VERSION 5.8 ;
BUSBITCHARS "[]" ;
DIVIDERCHAR "/" ;
UNITS
    DATABASE MICRONS 1000 ;
END UNITS

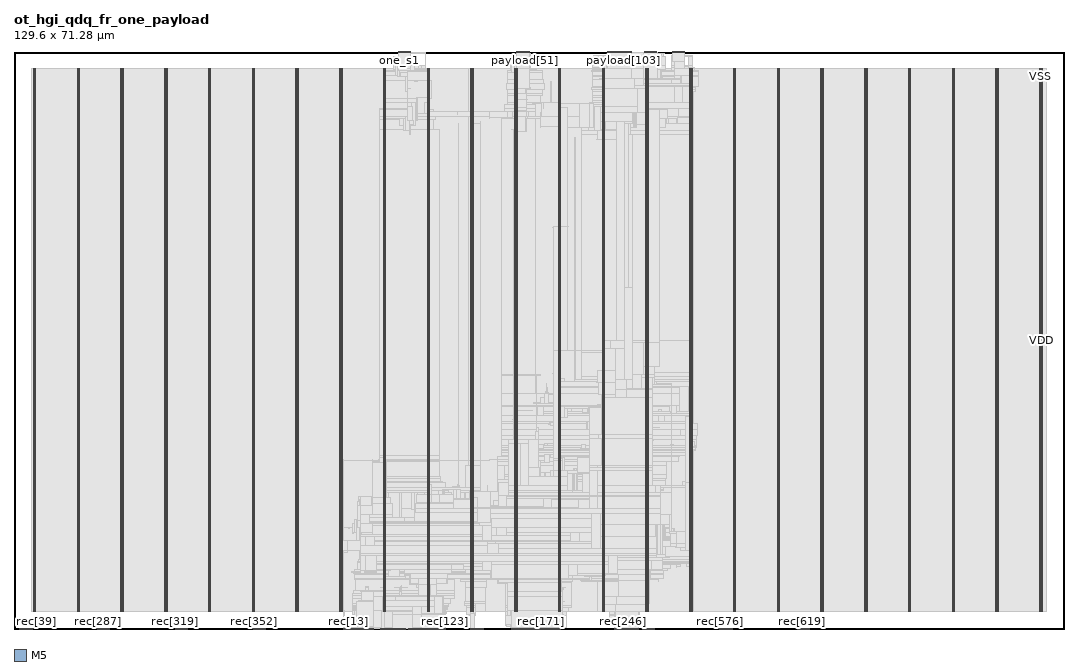
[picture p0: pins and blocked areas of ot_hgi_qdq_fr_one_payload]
MACRO ot_hgi_qdq_fr_one_payload
  FOREIGN ot_hgi_qdq_fr_one_payload 0 0 ;
  CLASS BLOCK ;
  SIZE 129.6 BY 71.28 ;
  PIN clk
    DIRECTION INPUT ;
    USE SIGNAL ;
    PORT
      LAYER M5 ;
        RECT  40.656 0 40.68 0.084 ;
    END
  END clk
  PIN nfault
    DIRECTION OUTPUT ;
    USE SIGNAL ;
    PORT
      LAYER M5 ;
        RECT  47.472 71.196 47.496 71.28 ;
    END
  END nfault
  PIN one_s1
    DIRECTION OUTPUT ;
    USE SIGNAL ;
    PORT
      LAYER M5 ;
        RECT  47.52 71.196 47.544 71.28 ;
    END
  END one_s1
  PIN payload[0]
    DIRECTION OUTPUT ;
    USE SIGNAL ;
    PORT
      LAYER M5 ;
        RECT  47.568 71.196 47.592 71.28 ;
    END
  END payload[0]
  PIN payload[100]
    DIRECTION OUTPUT ;
    USE SIGNAL ;
    PORT
      LAYER M5 ;
        RECT  75.024 71.196 75.048 71.28 ;
    END
  END payload[100]
  PIN payload[101]
    DIRECTION OUTPUT ;
    USE SIGNAL ;
    PORT
      LAYER M5 ;
        RECT  75.072 71.196 75.096 71.28 ;
    END
  END payload[101]
  PIN payload[102]
    DIRECTION OUTPUT ;
    USE SIGNAL ;
    PORT
      LAYER M5 ;
        RECT  75.12 71.196 75.144 71.28 ;
    END
  END payload[102]
  PIN payload[103]
    DIRECTION OUTPUT ;
    USE SIGNAL ;
    PORT
      LAYER M5 ;
        RECT  75.168 71.196 75.192 71.28 ;
    END
  END payload[103]
  PIN payload[104]
    DIRECTION OUTPUT ;
    USE SIGNAL ;
    PORT
      LAYER M5 ;
        RECT  75.216 71.196 75.24 71.28 ;
    END
  END payload[104]
  PIN payload[105]
    DIRECTION OUTPUT ;
    USE SIGNAL ;
    PORT
      LAYER M5 ;
        RECT  75.264 71.196 75.288 71.28 ;
    END
  END payload[105]
  PIN payload[106]
    DIRECTION OUTPUT ;
    USE SIGNAL ;
    PORT
      LAYER M5 ;
        RECT  75.312 71.196 75.336 71.28 ;
    END
  END payload[106]
  PIN payload[107]
    DIRECTION OUTPUT ;
    USE SIGNAL ;
    PORT
      LAYER M5 ;
        RECT  75.36 71.196 75.384 71.28 ;
    END
  END payload[107]
  PIN payload[108]
    DIRECTION OUTPUT ;
    USE SIGNAL ;
    PORT
      LAYER M5 ;
        RECT  75.408 71.196 75.432 71.28 ;
    END
  END payload[108]
  PIN payload[109]
    DIRECTION OUTPUT ;
    USE SIGNAL ;
    PORT
      LAYER M5 ;
        RECT  75.456 71.196 75.48 71.28 ;
    END
  END payload[109]
  PIN payload[10]
    DIRECTION OUTPUT ;
    USE SIGNAL ;
    PORT
      LAYER M5 ;
        RECT  48.048 71.196 48.072 71.28 ;
    END
  END payload[10]
  PIN payload[110]
    DIRECTION OUTPUT ;
    USE SIGNAL ;
    PORT
      LAYER M5 ;
        RECT  75.504 71.196 75.528 71.28 ;
    END
  END payload[110]
  PIN payload[111]
    DIRECTION OUTPUT ;
    USE SIGNAL ;
    PORT
      LAYER M5 ;
        RECT  75.552 71.196 75.576 71.28 ;
    END
  END payload[111]
  PIN payload[112]
    DIRECTION OUTPUT ;
    USE SIGNAL ;
    PORT
      LAYER M5 ;
        RECT  75.6 71.196 75.624 71.28 ;
    END
  END payload[112]
  PIN payload[113]
    DIRECTION OUTPUT ;
    USE SIGNAL ;
    PORT
      LAYER M5 ;
        RECT  75.648 71.196 75.672 71.28 ;
    END
  END payload[113]
  PIN payload[114]
    DIRECTION OUTPUT ;
    USE SIGNAL ;
    PORT
      LAYER M5 ;
        RECT  75.696 71.196 75.72 71.28 ;
    END
  END payload[114]
  PIN payload[115]
    DIRECTION OUTPUT ;
    USE SIGNAL ;
    PORT
      LAYER M5 ;
        RECT  75.744 71.196 75.768 71.28 ;
    END
  END payload[115]
  PIN payload[116]
    DIRECTION OUTPUT ;
    USE SIGNAL ;
    PORT
      LAYER M5 ;
        RECT  75.792 71.196 75.816 71.28 ;
    END
  END payload[116]
  PIN payload[117]
    DIRECTION OUTPUT ;
    USE SIGNAL ;
    PORT
      LAYER M5 ;
        RECT  75.84 71.196 75.864 71.28 ;
    END
  END payload[117]
  PIN payload[118]
    DIRECTION OUTPUT ;
    USE SIGNAL ;
    PORT
      LAYER M5 ;
        RECT  75.888 71.196 75.912 71.28 ;
    END
  END payload[118]
  PIN payload[119]
    DIRECTION OUTPUT ;
    USE SIGNAL ;
    PORT
      LAYER M5 ;
        RECT  75.936 71.196 75.96 71.28 ;
    END
  END payload[119]
  PIN payload[11]
    DIRECTION OUTPUT ;
    USE SIGNAL ;
    PORT
      LAYER M5 ;
        RECT  48.096 71.196 48.12 71.28 ;
    END
  END payload[11]
  PIN payload[120]
    DIRECTION OUTPUT ;
    USE SIGNAL ;
    PORT
      LAYER M5 ;
        RECT  75.984 71.196 76.008 71.28 ;
    END
  END payload[120]
  PIN payload[121]
    DIRECTION OUTPUT ;
    USE SIGNAL ;
    PORT
      LAYER M5 ;
        RECT  76.032 71.196 76.056 71.28 ;
    END
  END payload[121]
  PIN payload[122]
    DIRECTION OUTPUT ;
    USE SIGNAL ;
    PORT
      LAYER M5 ;
        RECT  76.08 71.196 76.104 71.28 ;
    END
  END payload[122]
  PIN payload[123]
    DIRECTION OUTPUT ;
    USE SIGNAL ;
    PORT
      LAYER M5 ;
        RECT  76.128 71.196 76.152 71.28 ;
    END
  END payload[123]
  PIN payload[124]
    DIRECTION OUTPUT ;
    USE SIGNAL ;
    PORT
      LAYER M5 ;
        RECT  76.176 71.196 76.2 71.28 ;
    END
  END payload[124]
  PIN payload[125]
    DIRECTION OUTPUT ;
    USE SIGNAL ;
    PORT
      LAYER M5 ;
        RECT  76.224 71.196 76.248 71.28 ;
    END
  END payload[125]
  PIN payload[126]
    DIRECTION OUTPUT ;
    USE SIGNAL ;
    PORT
      LAYER M5 ;
        RECT  77.808 71.196 77.832 71.28 ;
    END
  END payload[126]
  PIN payload[127]
    DIRECTION OUTPUT ;
    USE SIGNAL ;
    PORT
      LAYER M5 ;
        RECT  77.856 71.196 77.88 71.28 ;
    END
  END payload[127]
  PIN payload[128]
    DIRECTION OUTPUT ;
    USE SIGNAL ;
    PORT
      LAYER M5 ;
        RECT  77.904 71.196 77.928 71.28 ;
    END
  END payload[128]
  PIN payload[129]
    DIRECTION OUTPUT ;
    USE SIGNAL ;
    PORT
      LAYER M5 ;
        RECT  77.952 71.196 77.976 71.28 ;
    END
  END payload[129]
  PIN payload[12]
    DIRECTION OUTPUT ;
    USE SIGNAL ;
    PORT
      LAYER M5 ;
        RECT  48.144 71.196 48.168 71.28 ;
    END
  END payload[12]
  PIN payload[130]
    DIRECTION OUTPUT ;
    USE SIGNAL ;
    PORT
      LAYER M5 ;
        RECT  78 71.196 78.024 71.28 ;
    END
  END payload[130]
  PIN payload[131]
    DIRECTION OUTPUT ;
    USE SIGNAL ;
    PORT
      LAYER M5 ;
        RECT  78.048 71.196 78.072 71.28 ;
    END
  END payload[131]
  PIN payload[132]
    DIRECTION OUTPUT ;
    USE SIGNAL ;
    PORT
      LAYER M5 ;
        RECT  78.096 71.196 78.12 71.28 ;
    END
  END payload[132]
  PIN payload[133]
    DIRECTION OUTPUT ;
    USE SIGNAL ;
    PORT
      LAYER M5 ;
        RECT  78.144 71.196 78.168 71.28 ;
    END
  END payload[133]
  PIN payload[134]
    DIRECTION OUTPUT ;
    USE SIGNAL ;
    PORT
      LAYER M5 ;
        RECT  78.192 71.196 78.216 71.28 ;
    END
  END payload[134]
  PIN payload[135]
    DIRECTION OUTPUT ;
    USE SIGNAL ;
    PORT
      LAYER M5 ;
        RECT  78.24 71.196 78.264 71.28 ;
    END
  END payload[135]
  PIN payload[136]
    DIRECTION OUTPUT ;
    USE SIGNAL ;
    PORT
      LAYER M5 ;
        RECT  78.288 71.196 78.312 71.28 ;
    END
  END payload[136]
  PIN payload[137]
    DIRECTION OUTPUT ;
    USE SIGNAL ;
    PORT
      LAYER M5 ;
        RECT  78.336 71.196 78.36 71.28 ;
    END
  END payload[137]
  PIN payload[138]
    DIRECTION OUTPUT ;
    USE SIGNAL ;
    PORT
      LAYER M5 ;
        RECT  78.384 71.196 78.408 71.28 ;
    END
  END payload[138]
  PIN payload[139]
    DIRECTION OUTPUT ;
    USE SIGNAL ;
    PORT
      LAYER M5 ;
        RECT  78.432 71.196 78.456 71.28 ;
    END
  END payload[139]
  PIN payload[13]
    DIRECTION OUTPUT ;
    USE SIGNAL ;
    PORT
      LAYER M5 ;
        RECT  48.192 71.196 48.216 71.28 ;
    END
  END payload[13]
  PIN payload[140]
    DIRECTION OUTPUT ;
    USE SIGNAL ;
    PORT
      LAYER M5 ;
        RECT  78.48 71.196 78.504 71.28 ;
    END
  END payload[140]
  PIN payload[141]
    DIRECTION OUTPUT ;
    USE SIGNAL ;
    PORT
      LAYER M5 ;
        RECT  78.528 71.196 78.552 71.28 ;
    END
  END payload[141]
  PIN payload[142]
    DIRECTION OUTPUT ;
    USE SIGNAL ;
    PORT
      LAYER M5 ;
        RECT  78.576 71.196 78.6 71.28 ;
    END
  END payload[142]
  PIN payload[143]
    DIRECTION OUTPUT ;
    USE SIGNAL ;
    PORT
      LAYER M5 ;
        RECT  78.624 71.196 78.648 71.28 ;
    END
  END payload[143]
  PIN payload[144]
    DIRECTION OUTPUT ;
    USE SIGNAL ;
    PORT
      LAYER M5 ;
        RECT  78.672 71.196 78.696 71.28 ;
    END
  END payload[144]
  PIN payload[145]
    DIRECTION OUTPUT ;
    USE SIGNAL ;
    PORT
      LAYER M5 ;
        RECT  78.72 71.196 78.744 71.28 ;
    END
  END payload[145]
  PIN payload[146]
    DIRECTION OUTPUT ;
    USE SIGNAL ;
    PORT
      LAYER M5 ;
        RECT  78.768 71.196 78.792 71.28 ;
    END
  END payload[146]
  PIN payload[147]
    DIRECTION OUTPUT ;
    USE SIGNAL ;
    PORT
      LAYER M5 ;
        RECT  78.816 71.196 78.84 71.28 ;
    END
  END payload[147]
  PIN payload[148]
    DIRECTION OUTPUT ;
    USE SIGNAL ;
    PORT
      LAYER M5 ;
        RECT  78.864 71.196 78.888 71.28 ;
    END
  END payload[148]
  PIN payload[149]
    DIRECTION OUTPUT ;
    USE SIGNAL ;
    PORT
      LAYER M5 ;
        RECT  78.912 71.196 78.936 71.28 ;
    END
  END payload[149]
  PIN payload[14]
    DIRECTION OUTPUT ;
    USE SIGNAL ;
    PORT
      LAYER M5 ;
        RECT  48.24 71.196 48.264 71.28 ;
    END
  END payload[14]
  PIN payload[150]
    DIRECTION OUTPUT ;
    USE SIGNAL ;
    PORT
      LAYER M5 ;
        RECT  78.96 71.196 78.984 71.28 ;
    END
  END payload[150]
  PIN payload[151]
    DIRECTION OUTPUT ;
    USE SIGNAL ;
    PORT
      LAYER M5 ;
        RECT  79.008 71.196 79.032 71.28 ;
    END
  END payload[151]
  PIN payload[152]
    DIRECTION OUTPUT ;
    USE SIGNAL ;
    PORT
      LAYER M5 ;
        RECT  79.056 71.196 79.08 71.28 ;
    END
  END payload[152]
  PIN payload[153]
    DIRECTION OUTPUT ;
    USE SIGNAL ;
    PORT
      LAYER M5 ;
        RECT  79.104 71.196 79.128 71.28 ;
    END
  END payload[153]
  PIN payload[154]
    DIRECTION OUTPUT ;
    USE SIGNAL ;
    PORT
      LAYER M5 ;
        RECT  79.152 71.196 79.176 71.28 ;
    END
  END payload[154]
  PIN payload[155]
    DIRECTION OUTPUT ;
    USE SIGNAL ;
    PORT
      LAYER M5 ;
        RECT  79.2 71.196 79.224 71.28 ;
    END
  END payload[155]
  PIN payload[156]
    DIRECTION OUTPUT ;
    USE SIGNAL ;
    PORT
      LAYER M5 ;
        RECT  79.248 71.196 79.272 71.28 ;
    END
  END payload[156]
  PIN payload[157]
    DIRECTION OUTPUT ;
    USE SIGNAL ;
    PORT
      LAYER M5 ;
        RECT  79.296 71.196 79.32 71.28 ;
    END
  END payload[157]
  PIN payload[158]
    DIRECTION OUTPUT ;
    USE SIGNAL ;
    PORT
      LAYER M5 ;
        RECT  81.264 71.196 81.288 71.28 ;
    END
  END payload[158]
  PIN payload[159]
    DIRECTION OUTPUT ;
    USE SIGNAL ;
    PORT
      LAYER M5 ;
        RECT  81.312 71.196 81.336 71.28 ;
    END
  END payload[159]
  PIN payload[15]
    DIRECTION OUTPUT ;
    USE SIGNAL ;
    PORT
      LAYER M5 ;
        RECT  48.288 71.196 48.312 71.28 ;
    END
  END payload[15]
  PIN payload[160]
    DIRECTION OUTPUT ;
    USE SIGNAL ;
    PORT
      LAYER M5 ;
        RECT  81.36 71.196 81.384 71.28 ;
    END
  END payload[160]
  PIN payload[161]
    DIRECTION OUTPUT ;
    USE SIGNAL ;
    PORT
      LAYER M5 ;
        RECT  81.408 71.196 81.432 71.28 ;
    END
  END payload[161]
  PIN payload[162]
    DIRECTION OUTPUT ;
    USE SIGNAL ;
    PORT
      LAYER M5 ;
        RECT  81.456 71.196 81.48 71.28 ;
    END
  END payload[162]
  PIN payload[163]
    DIRECTION OUTPUT ;
    USE SIGNAL ;
    PORT
      LAYER M5 ;
        RECT  81.504 71.196 81.528 71.28 ;
    END
  END payload[163]
  PIN payload[164]
    DIRECTION OUTPUT ;
    USE SIGNAL ;
    PORT
      LAYER M5 ;
        RECT  81.552 71.196 81.576 71.28 ;
    END
  END payload[164]
  PIN payload[165]
    DIRECTION OUTPUT ;
    USE SIGNAL ;
    PORT
      LAYER M5 ;
        RECT  81.6 71.196 81.624 71.28 ;
    END
  END payload[165]
  PIN payload[166]
    DIRECTION OUTPUT ;
    USE SIGNAL ;
    PORT
      LAYER M5 ;
        RECT  81.648 71.196 81.672 71.28 ;
    END
  END payload[166]
  PIN payload[167]
    DIRECTION OUTPUT ;
    USE SIGNAL ;
    PORT
      LAYER M5 ;
        RECT  81.696 71.196 81.72 71.28 ;
    END
  END payload[167]
  PIN payload[168]
    DIRECTION OUTPUT ;
    USE SIGNAL ;
    PORT
      LAYER M5 ;
        RECT  81.744 71.196 81.768 71.28 ;
    END
  END payload[168]
  PIN payload[169]
    DIRECTION OUTPUT ;
    USE SIGNAL ;
    PORT
      LAYER M5 ;
        RECT  81.792 71.196 81.816 71.28 ;
    END
  END payload[169]
  PIN payload[16]
    DIRECTION OUTPUT ;
    USE SIGNAL ;
    PORT
      LAYER M5 ;
        RECT  48.336 71.196 48.36 71.28 ;
    END
  END payload[16]
  PIN payload[170]
    DIRECTION OUTPUT ;
    USE SIGNAL ;
    PORT
      LAYER M5 ;
        RECT  81.84 71.196 81.864 71.28 ;
    END
  END payload[170]
  PIN payload[171]
    DIRECTION OUTPUT ;
    USE SIGNAL ;
    PORT
      LAYER M5 ;
        RECT  81.888 71.196 81.912 71.28 ;
    END
  END payload[171]
  PIN payload[172]
    DIRECTION OUTPUT ;
    USE SIGNAL ;
    PORT
      LAYER M5 ;
        RECT  81.936 71.196 81.96 71.28 ;
    END
  END payload[172]
  PIN payload[173]
    DIRECTION OUTPUT ;
    USE SIGNAL ;
    PORT
      LAYER M5 ;
        RECT  81.984 71.196 82.008 71.28 ;
    END
  END payload[173]
  PIN payload[174]
    DIRECTION OUTPUT ;
    USE SIGNAL ;
    PORT
      LAYER M5 ;
        RECT  82.032 71.196 82.056 71.28 ;
    END
  END payload[174]
  PIN payload[175]
    DIRECTION OUTPUT ;
    USE SIGNAL ;
    PORT
      LAYER M5 ;
        RECT  82.08 71.196 82.104 71.28 ;
    END
  END payload[175]
  PIN payload[176]
    DIRECTION OUTPUT ;
    USE SIGNAL ;
    PORT
      LAYER M5 ;
        RECT  82.128 71.196 82.152 71.28 ;
    END
  END payload[176]
  PIN payload[177]
    DIRECTION OUTPUT ;
    USE SIGNAL ;
    PORT
      LAYER M5 ;
        RECT  82.176 71.196 82.2 71.28 ;
    END
  END payload[177]
  PIN payload[178]
    DIRECTION OUTPUT ;
    USE SIGNAL ;
    PORT
      LAYER M5 ;
        RECT  82.224 71.196 82.248 71.28 ;
    END
  END payload[178]
  PIN payload[179]
    DIRECTION OUTPUT ;
    USE SIGNAL ;
    PORT
      LAYER M5 ;
        RECT  82.272 71.196 82.296 71.28 ;
    END
  END payload[179]
  PIN payload[17]
    DIRECTION OUTPUT ;
    USE SIGNAL ;
    PORT
      LAYER M5 ;
        RECT  48.384 71.196 48.408 71.28 ;
    END
  END payload[17]
  PIN payload[180]
    DIRECTION OUTPUT ;
    USE SIGNAL ;
    PORT
      LAYER M5 ;
        RECT  82.32 71.196 82.344 71.28 ;
    END
  END payload[180]
  PIN payload[181]
    DIRECTION OUTPUT ;
    USE SIGNAL ;
    PORT
      LAYER M5 ;
        RECT  82.368 71.196 82.392 71.28 ;
    END
  END payload[181]
  PIN payload[182]
    DIRECTION OUTPUT ;
    USE SIGNAL ;
    PORT
      LAYER M5 ;
        RECT  82.416 71.196 82.44 71.28 ;
    END
  END payload[182]
  PIN payload[183]
    DIRECTION OUTPUT ;
    USE SIGNAL ;
    PORT
      LAYER M5 ;
        RECT  82.464 71.196 82.488 71.28 ;
    END
  END payload[183]
  PIN payload[184]
    DIRECTION OUTPUT ;
    USE SIGNAL ;
    PORT
      LAYER M5 ;
        RECT  82.512 71.196 82.536 71.28 ;
    END
  END payload[184]
  PIN payload[185]
    DIRECTION OUTPUT ;
    USE SIGNAL ;
    PORT
      LAYER M5 ;
        RECT  82.56 71.196 82.584 71.28 ;
    END
  END payload[185]
  PIN payload[186]
    DIRECTION OUTPUT ;
    USE SIGNAL ;
    PORT
      LAYER M5 ;
        RECT  82.608 71.196 82.632 71.28 ;
    END
  END payload[186]
  PIN payload[187]
    DIRECTION OUTPUT ;
    USE SIGNAL ;
    PORT
      LAYER M5 ;
        RECT  82.656 71.196 82.68 71.28 ;
    END
  END payload[187]
  PIN payload[188]
    DIRECTION OUTPUT ;
    USE SIGNAL ;
    PORT
      LAYER M5 ;
        RECT  82.704 71.196 82.728 71.28 ;
    END
  END payload[188]
  PIN payload[189]
    DIRECTION OUTPUT ;
    USE SIGNAL ;
    PORT
      LAYER M5 ;
        RECT  82.752 71.196 82.776 71.28 ;
    END
  END payload[189]
  PIN payload[18]
    DIRECTION OUTPUT ;
    USE SIGNAL ;
    PORT
      LAYER M5 ;
        RECT  48.432 71.196 48.456 71.28 ;
    END
  END payload[18]
  PIN payload[19]
    DIRECTION OUTPUT ;
    USE SIGNAL ;
    PORT
      LAYER M5 ;
        RECT  48.48 71.196 48.504 71.28 ;
    END
  END payload[19]
  PIN payload[1]
    DIRECTION OUTPUT ;
    USE SIGNAL ;
    PORT
      LAYER M5 ;
        RECT  47.616 71.196 47.64 71.28 ;
    END
  END payload[1]
  PIN payload[20]
    DIRECTION OUTPUT ;
    USE SIGNAL ;
    PORT
      LAYER M5 ;
        RECT  48.528 71.196 48.552 71.28 ;
    END
  END payload[20]
  PIN payload[21]
    DIRECTION OUTPUT ;
    USE SIGNAL ;
    PORT
      LAYER M5 ;
        RECT  48.576 71.196 48.6 71.28 ;
    END
  END payload[21]
  PIN payload[22]
    DIRECTION OUTPUT ;
    USE SIGNAL ;
    PORT
      LAYER M5 ;
        RECT  48.624 71.196 48.648 71.28 ;
    END
  END payload[22]
  PIN payload[23]
    DIRECTION OUTPUT ;
    USE SIGNAL ;
    PORT
      LAYER M5 ;
        RECT  48.672 71.196 48.696 71.28 ;
    END
  END payload[23]
  PIN payload[24]
    DIRECTION OUTPUT ;
    USE SIGNAL ;
    PORT
      LAYER M5 ;
        RECT  48.72 71.196 48.744 71.28 ;
    END
  END payload[24]
  PIN payload[25]
    DIRECTION OUTPUT ;
    USE SIGNAL ;
    PORT
      LAYER M5 ;
        RECT  48.768 71.196 48.792 71.28 ;
    END
  END payload[25]
  PIN payload[26]
    DIRECTION OUTPUT ;
    USE SIGNAL ;
    PORT
      LAYER M5 ;
        RECT  48.816 71.196 48.84 71.28 ;
    END
  END payload[26]
  PIN payload[27]
    DIRECTION OUTPUT ;
    USE SIGNAL ;
    PORT
      LAYER M5 ;
        RECT  48.864 71.196 48.888 71.28 ;
    END
  END payload[27]
  PIN payload[28]
    DIRECTION OUTPUT ;
    USE SIGNAL ;
    PORT
      LAYER M5 ;
        RECT  48.912 71.196 48.936 71.28 ;
    END
  END payload[28]
  PIN payload[29]
    DIRECTION OUTPUT ;
    USE SIGNAL ;
    PORT
      LAYER M5 ;
        RECT  48.96 71.196 48.984 71.28 ;
    END
  END payload[29]
  PIN payload[2]
    DIRECTION OUTPUT ;
    USE SIGNAL ;
    PORT
      LAYER M5 ;
        RECT  47.664 71.196 47.688 71.28 ;
    END
  END payload[2]
  PIN payload[30]
    DIRECTION OUTPUT ;
    USE SIGNAL ;
    PORT
      LAYER M5 ;
        RECT  62.064 71.196 62.088 71.28 ;
    END
  END payload[30]
  PIN payload[31]
    DIRECTION OUTPUT ;
    USE SIGNAL ;
    PORT
      LAYER M5 ;
        RECT  62.112 71.196 62.136 71.28 ;
    END
  END payload[31]
  PIN payload[32]
    DIRECTION OUTPUT ;
    USE SIGNAL ;
    PORT
      LAYER M5 ;
        RECT  62.16 71.196 62.184 71.28 ;
    END
  END payload[32]
  PIN payload[33]
    DIRECTION OUTPUT ;
    USE SIGNAL ;
    PORT
      LAYER M5 ;
        RECT  62.208 71.196 62.232 71.28 ;
    END
  END payload[33]
  PIN payload[34]
    DIRECTION OUTPUT ;
    USE SIGNAL ;
    PORT
      LAYER M5 ;
        RECT  62.256 71.196 62.28 71.28 ;
    END
  END payload[34]
  PIN payload[35]
    DIRECTION OUTPUT ;
    USE SIGNAL ;
    PORT
      LAYER M5 ;
        RECT  62.304 71.196 62.328 71.28 ;
    END
  END payload[35]
  PIN payload[36]
    DIRECTION OUTPUT ;
    USE SIGNAL ;
    PORT
      LAYER M5 ;
        RECT  62.352 71.196 62.376 71.28 ;
    END
  END payload[36]
  PIN payload[37]
    DIRECTION OUTPUT ;
    USE SIGNAL ;
    PORT
      LAYER M5 ;
        RECT  62.4 71.196 62.424 71.28 ;
    END
  END payload[37]
  PIN payload[38]
    DIRECTION OUTPUT ;
    USE SIGNAL ;
    PORT
      LAYER M5 ;
        RECT  62.448 71.196 62.472 71.28 ;
    END
  END payload[38]
  PIN payload[39]
    DIRECTION OUTPUT ;
    USE SIGNAL ;
    PORT
      LAYER M5 ;
        RECT  62.496 71.196 62.52 71.28 ;
    END
  END payload[39]
  PIN payload[3]
    DIRECTION OUTPUT ;
    USE SIGNAL ;
    PORT
      LAYER M5 ;
        RECT  47.712 71.196 47.736 71.28 ;
    END
  END payload[3]
  PIN payload[40]
    DIRECTION OUTPUT ;
    USE SIGNAL ;
    PORT
      LAYER M5 ;
        RECT  62.544 71.196 62.568 71.28 ;
    END
  END payload[40]
  PIN payload[41]
    DIRECTION OUTPUT ;
    USE SIGNAL ;
    PORT
      LAYER M5 ;
        RECT  62.592 71.196 62.616 71.28 ;
    END
  END payload[41]
  PIN payload[42]
    DIRECTION OUTPUT ;
    USE SIGNAL ;
    PORT
      LAYER M5 ;
        RECT  62.64 71.196 62.664 71.28 ;
    END
  END payload[42]
  PIN payload[43]
    DIRECTION OUTPUT ;
    USE SIGNAL ;
    PORT
      LAYER M5 ;
        RECT  62.688 71.196 62.712 71.28 ;
    END
  END payload[43]
  PIN payload[44]
    DIRECTION OUTPUT ;
    USE SIGNAL ;
    PORT
      LAYER M5 ;
        RECT  62.736 71.196 62.76 71.28 ;
    END
  END payload[44]
  PIN payload[45]
    DIRECTION OUTPUT ;
    USE SIGNAL ;
    PORT
      LAYER M5 ;
        RECT  62.784 71.196 62.808 71.28 ;
    END
  END payload[45]
  PIN payload[46]
    DIRECTION OUTPUT ;
    USE SIGNAL ;
    PORT
      LAYER M5 ;
        RECT  62.832 71.196 62.856 71.28 ;
    END
  END payload[46]
  PIN payload[47]
    DIRECTION OUTPUT ;
    USE SIGNAL ;
    PORT
      LAYER M5 ;
        RECT  62.88 71.196 62.904 71.28 ;
    END
  END payload[47]
  PIN payload[48]
    DIRECTION OUTPUT ;
    USE SIGNAL ;
    PORT
      LAYER M5 ;
        RECT  62.928 71.196 62.952 71.28 ;
    END
  END payload[48]
  PIN payload[49]
    DIRECTION OUTPUT ;
    USE SIGNAL ;
    PORT
      LAYER M5 ;
        RECT  62.976 71.196 63 71.28 ;
    END
  END payload[49]
  PIN payload[4]
    DIRECTION OUTPUT ;
    USE SIGNAL ;
    PORT
      LAYER M5 ;
        RECT  47.76 71.196 47.784 71.28 ;
    END
  END payload[4]
  PIN payload[50]
    DIRECTION OUTPUT ;
    USE SIGNAL ;
    PORT
      LAYER M5 ;
        RECT  63.024 71.196 63.048 71.28 ;
    END
  END payload[50]
  PIN payload[51]
    DIRECTION OUTPUT ;
    USE SIGNAL ;
    PORT
      LAYER M5 ;
        RECT  63.072 71.196 63.096 71.28 ;
    END
  END payload[51]
  PIN payload[52]
    DIRECTION OUTPUT ;
    USE SIGNAL ;
    PORT
      LAYER M5 ;
        RECT  63.12 71.196 63.144 71.28 ;
    END
  END payload[52]
  PIN payload[53]
    DIRECTION OUTPUT ;
    USE SIGNAL ;
    PORT
      LAYER M5 ;
        RECT  63.168 71.196 63.192 71.28 ;
    END
  END payload[53]
  PIN payload[54]
    DIRECTION OUTPUT ;
    USE SIGNAL ;
    PORT
      LAYER M5 ;
        RECT  63.216 71.196 63.24 71.28 ;
    END
  END payload[54]
  PIN payload[55]
    DIRECTION OUTPUT ;
    USE SIGNAL ;
    PORT
      LAYER M5 ;
        RECT  63.264 71.196 63.288 71.28 ;
    END
  END payload[55]
  PIN payload[56]
    DIRECTION OUTPUT ;
    USE SIGNAL ;
    PORT
      LAYER M5 ;
        RECT  63.312 71.196 63.336 71.28 ;
    END
  END payload[56]
  PIN payload[57]
    DIRECTION OUTPUT ;
    USE SIGNAL ;
    PORT
      LAYER M5 ;
        RECT  63.36 71.196 63.384 71.28 ;
    END
  END payload[57]
  PIN payload[58]
    DIRECTION OUTPUT ;
    USE SIGNAL ;
    PORT
      LAYER M5 ;
        RECT  63.408 71.196 63.432 71.28 ;
    END
  END payload[58]
  PIN payload[59]
    DIRECTION OUTPUT ;
    USE SIGNAL ;
    PORT
      LAYER M5 ;
        RECT  63.456 71.196 63.48 71.28 ;
    END
  END payload[59]
  PIN payload[5]
    DIRECTION OUTPUT ;
    USE SIGNAL ;
    PORT
      LAYER M5 ;
        RECT  47.808 71.196 47.832 71.28 ;
    END
  END payload[5]
  PIN payload[60]
    DIRECTION OUTPUT ;
    USE SIGNAL ;
    PORT
      LAYER M5 ;
        RECT  63.504 71.196 63.528 71.28 ;
    END
  END payload[60]
  PIN payload[61]
    DIRECTION OUTPUT ;
    USE SIGNAL ;
    PORT
      LAYER M5 ;
        RECT  63.552 71.196 63.576 71.28 ;
    END
  END payload[61]
  PIN payload[62]
    DIRECTION OUTPUT ;
    USE SIGNAL ;
    PORT
      LAYER M5 ;
        RECT  73.2 71.196 73.224 71.28 ;
    END
  END payload[62]
  PIN payload[63]
    DIRECTION OUTPUT ;
    USE SIGNAL ;
    PORT
      LAYER M5 ;
        RECT  73.248 71.196 73.272 71.28 ;
    END
  END payload[63]
  PIN payload[64]
    DIRECTION OUTPUT ;
    USE SIGNAL ;
    PORT
      LAYER M5 ;
        RECT  73.296 71.196 73.32 71.28 ;
    END
  END payload[64]
  PIN payload[65]
    DIRECTION OUTPUT ;
    USE SIGNAL ;
    PORT
      LAYER M5 ;
        RECT  73.344 71.196 73.368 71.28 ;
    END
  END payload[65]
  PIN payload[66]
    DIRECTION OUTPUT ;
    USE SIGNAL ;
    PORT
      LAYER M5 ;
        RECT  73.392 71.196 73.416 71.28 ;
    END
  END payload[66]
  PIN payload[67]
    DIRECTION OUTPUT ;
    USE SIGNAL ;
    PORT
      LAYER M5 ;
        RECT  73.44 71.196 73.464 71.28 ;
    END
  END payload[67]
  PIN payload[68]
    DIRECTION OUTPUT ;
    USE SIGNAL ;
    PORT
      LAYER M5 ;
        RECT  73.488 71.196 73.512 71.28 ;
    END
  END payload[68]
  PIN payload[69]
    DIRECTION OUTPUT ;
    USE SIGNAL ;
    PORT
      LAYER M5 ;
        RECT  73.536 71.196 73.56 71.28 ;
    END
  END payload[69]
  PIN payload[6]
    DIRECTION OUTPUT ;
    USE SIGNAL ;
    PORT
      LAYER M5 ;
        RECT  47.856 71.196 47.88 71.28 ;
    END
  END payload[6]
  PIN payload[70]
    DIRECTION OUTPUT ;
    USE SIGNAL ;
    PORT
      LAYER M5 ;
        RECT  73.584 71.196 73.608 71.28 ;
    END
  END payload[70]
  PIN payload[71]
    DIRECTION OUTPUT ;
    USE SIGNAL ;
    PORT
      LAYER M5 ;
        RECT  73.632 71.196 73.656 71.28 ;
    END
  END payload[71]
  PIN payload[72]
    DIRECTION OUTPUT ;
    USE SIGNAL ;
    PORT
      LAYER M5 ;
        RECT  73.68 71.196 73.704 71.28 ;
    END
  END payload[72]
  PIN payload[73]
    DIRECTION OUTPUT ;
    USE SIGNAL ;
    PORT
      LAYER M5 ;
        RECT  73.728 71.196 73.752 71.28 ;
    END
  END payload[73]
  PIN payload[74]
    DIRECTION OUTPUT ;
    USE SIGNAL ;
    PORT
      LAYER M5 ;
        RECT  73.776 71.196 73.8 71.28 ;
    END
  END payload[74]
  PIN payload[75]
    DIRECTION OUTPUT ;
    USE SIGNAL ;
    PORT
      LAYER M5 ;
        RECT  73.824 71.196 73.848 71.28 ;
    END
  END payload[75]
  PIN payload[76]
    DIRECTION OUTPUT ;
    USE SIGNAL ;
    PORT
      LAYER M5 ;
        RECT  73.872 71.196 73.896 71.28 ;
    END
  END payload[76]
  PIN payload[77]
    DIRECTION OUTPUT ;
    USE SIGNAL ;
    PORT
      LAYER M5 ;
        RECT  73.92 71.196 73.944 71.28 ;
    END
  END payload[77]
  PIN payload[78]
    DIRECTION OUTPUT ;
    USE SIGNAL ;
    PORT
      LAYER M5 ;
        RECT  73.968 71.196 73.992 71.28 ;
    END
  END payload[78]
  PIN payload[79]
    DIRECTION OUTPUT ;
    USE SIGNAL ;
    PORT
      LAYER M5 ;
        RECT  74.016 71.196 74.04 71.28 ;
    END
  END payload[79]
  PIN payload[7]
    DIRECTION OUTPUT ;
    USE SIGNAL ;
    PORT
      LAYER M5 ;
        RECT  47.904 71.196 47.928 71.28 ;
    END
  END payload[7]
  PIN payload[80]
    DIRECTION OUTPUT ;
    USE SIGNAL ;
    PORT
      LAYER M5 ;
        RECT  74.064 71.196 74.088 71.28 ;
    END
  END payload[80]
  PIN payload[81]
    DIRECTION OUTPUT ;
    USE SIGNAL ;
    PORT
      LAYER M5 ;
        RECT  74.112 71.196 74.136 71.28 ;
    END
  END payload[81]
  PIN payload[82]
    DIRECTION OUTPUT ;
    USE SIGNAL ;
    PORT
      LAYER M5 ;
        RECT  74.16 71.196 74.184 71.28 ;
    END
  END payload[82]
  PIN payload[83]
    DIRECTION OUTPUT ;
    USE SIGNAL ;
    PORT
      LAYER M5 ;
        RECT  74.208 71.196 74.232 71.28 ;
    END
  END payload[83]
  PIN payload[84]
    DIRECTION OUTPUT ;
    USE SIGNAL ;
    PORT
      LAYER M5 ;
        RECT  74.256 71.196 74.28 71.28 ;
    END
  END payload[84]
  PIN payload[85]
    DIRECTION OUTPUT ;
    USE SIGNAL ;
    PORT
      LAYER M5 ;
        RECT  74.304 71.196 74.328 71.28 ;
    END
  END payload[85]
  PIN payload[86]
    DIRECTION OUTPUT ;
    USE SIGNAL ;
    PORT
      LAYER M5 ;
        RECT  74.352 71.196 74.376 71.28 ;
    END
  END payload[86]
  PIN payload[87]
    DIRECTION OUTPUT ;
    USE SIGNAL ;
    PORT
      LAYER M5 ;
        RECT  74.4 71.196 74.424 71.28 ;
    END
  END payload[87]
  PIN payload[88]
    DIRECTION OUTPUT ;
    USE SIGNAL ;
    PORT
      LAYER M5 ;
        RECT  74.448 71.196 74.472 71.28 ;
    END
  END payload[88]
  PIN payload[89]
    DIRECTION OUTPUT ;
    USE SIGNAL ;
    PORT
      LAYER M5 ;
        RECT  74.496 71.196 74.52 71.28 ;
    END
  END payload[89]
  PIN payload[8]
    DIRECTION OUTPUT ;
    USE SIGNAL ;
    PORT
      LAYER M5 ;
        RECT  47.952 71.196 47.976 71.28 ;
    END
  END payload[8]
  PIN payload[90]
    DIRECTION OUTPUT ;
    USE SIGNAL ;
    PORT
      LAYER M5 ;
        RECT  74.544 71.196 74.568 71.28 ;
    END
  END payload[90]
  PIN payload[91]
    DIRECTION OUTPUT ;
    USE SIGNAL ;
    PORT
      LAYER M5 ;
        RECT  74.592 71.196 74.616 71.28 ;
    END
  END payload[91]
  PIN payload[92]
    DIRECTION OUTPUT ;
    USE SIGNAL ;
    PORT
      LAYER M5 ;
        RECT  74.64 71.196 74.664 71.28 ;
    END
  END payload[92]
  PIN payload[93]
    DIRECTION OUTPUT ;
    USE SIGNAL ;
    PORT
      LAYER M5 ;
        RECT  74.688 71.196 74.712 71.28 ;
    END
  END payload[93]
  PIN payload[94]
    DIRECTION OUTPUT ;
    USE SIGNAL ;
    PORT
      LAYER M5 ;
        RECT  74.736 71.196 74.76 71.28 ;
    END
  END payload[94]
  PIN payload[95]
    DIRECTION OUTPUT ;
    USE SIGNAL ;
    PORT
      LAYER M5 ;
        RECT  74.784 71.196 74.808 71.28 ;
    END
  END payload[95]
  PIN payload[96]
    DIRECTION OUTPUT ;
    USE SIGNAL ;
    PORT
      LAYER M5 ;
        RECT  74.832 71.196 74.856 71.28 ;
    END
  END payload[96]
  PIN payload[97]
    DIRECTION OUTPUT ;
    USE SIGNAL ;
    PORT
      LAYER M5 ;
        RECT  74.88 71.196 74.904 71.28 ;
    END
  END payload[97]
  PIN payload[98]
    DIRECTION OUTPUT ;
    USE SIGNAL ;
    PORT
      LAYER M5 ;
        RECT  74.928 71.196 74.952 71.28 ;
    END
  END payload[98]
  PIN payload[99]
    DIRECTION OUTPUT ;
    USE SIGNAL ;
    PORT
      LAYER M5 ;
        RECT  74.976 71.196 75 71.28 ;
    END
  END payload[99]
  PIN payload[9]
    DIRECTION OUTPUT ;
    USE SIGNAL ;
    PORT
      LAYER M5 ;
        RECT  48 71.196 48.024 71.28 ;
    END
  END payload[9]
  PIN rec[0]
    DIRECTION INPUT ;
    USE SIGNAL ;
    PORT
      LAYER M5 ;
        RECT  40.704 0 40.728 0.084 ;
    END
  END rec[0]
  PIN rec[100]
    DIRECTION INPUT ;
    USE SIGNAL ;
    PORT
      LAYER M5 ;
        RECT  52.032 0 52.056 0.084 ;
    END
  END rec[100]
  PIN rec[101]
    DIRECTION INPUT ;
    USE SIGNAL ;
    PORT
      LAYER M5 ;
        RECT  52.08 0 52.104 0.084 ;
    END
  END rec[101]
  PIN rec[102]
    DIRECTION INPUT ;
    USE SIGNAL ;
    PORT
      LAYER M5 ;
        RECT  52.128 0 52.152 0.084 ;
    END
  END rec[102]
  PIN rec[103]
    DIRECTION INPUT ;
    USE SIGNAL ;
    PORT
      LAYER M5 ;
        RECT  52.176 0 52.2 0.084 ;
    END
  END rec[103]
  PIN rec[104]
    DIRECTION INPUT ;
    USE SIGNAL ;
    PORT
      LAYER M5 ;
        RECT  52.224 0 52.248 0.084 ;
    END
  END rec[104]
  PIN rec[105]
    DIRECTION INPUT ;
    USE SIGNAL ;
    PORT
      LAYER M5 ;
        RECT  52.272 0 52.296 0.084 ;
    END
  END rec[105]
  PIN rec[106]
    DIRECTION INPUT ;
    USE SIGNAL ;
    PORT
      LAYER M5 ;
        RECT  52.32 0 52.344 0.084 ;
    END
  END rec[106]
  PIN rec[107]
    DIRECTION INPUT ;
    USE SIGNAL ;
    PORT
      LAYER M5 ;
        RECT  52.368 0 52.392 0.084 ;
    END
  END rec[107]
  PIN rec[108]
    DIRECTION INPUT ;
    USE SIGNAL ;
    PORT
      LAYER M5 ;
        RECT  52.416 0 52.44 0.084 ;
    END
  END rec[108]
  PIN rec[109]
    DIRECTION INPUT ;
    USE SIGNAL ;
    PORT
      LAYER M5 ;
        RECT  52.464 0 52.488 0.084 ;
    END
  END rec[109]
  PIN rec[10]
    DIRECTION INPUT ;
    USE SIGNAL ;
    PORT
      LAYER M5 ;
        RECT  41.184 0 41.208 0.084 ;
    END
  END rec[10]
  PIN rec[110]
    DIRECTION INPUT ;
    USE SIGNAL ;
    PORT
      LAYER M5 ;
        RECT  52.512 0 52.536 0.084 ;
    END
  END rec[110]
  PIN rec[111]
    DIRECTION INPUT ;
    USE SIGNAL ;
    PORT
      LAYER M5 ;
        RECT  52.56 0 52.584 0.084 ;
    END
  END rec[111]
  PIN rec[112]
    DIRECTION INPUT ;
    USE SIGNAL ;
    PORT
      LAYER M5 ;
        RECT  52.608 0 52.632 0.084 ;
    END
  END rec[112]
  PIN rec[113]
    DIRECTION INPUT ;
    USE SIGNAL ;
    PORT
      LAYER M5 ;
        RECT  52.656 0 52.68 0.084 ;
    END
  END rec[113]
  PIN rec[114]
    DIRECTION INPUT ;
    USE SIGNAL ;
    PORT
      LAYER M5 ;
        RECT  52.704 0 52.728 0.084 ;
    END
  END rec[114]
  PIN rec[115]
    DIRECTION INPUT ;
    USE SIGNAL ;
    PORT
      LAYER M5 ;
        RECT  52.752 0 52.776 0.084 ;
    END
  END rec[115]
  PIN rec[116]
    DIRECTION INPUT ;
    USE SIGNAL ;
    PORT
      LAYER M5 ;
        RECT  52.8 0 52.824 0.084 ;
    END
  END rec[116]
  PIN rec[117]
    DIRECTION INPUT ;
    USE SIGNAL ;
    PORT
      LAYER M5 ;
        RECT  52.848 0 52.872 0.084 ;
    END
  END rec[117]
  PIN rec[118]
    DIRECTION INPUT ;
    USE SIGNAL ;
    PORT
      LAYER M5 ;
        RECT  52.896 0 52.92 0.084 ;
    END
  END rec[118]
  PIN rec[119]
    DIRECTION INPUT ;
    USE SIGNAL ;
    PORT
      LAYER M5 ;
        RECT  52.944 0 52.968 0.084 ;
    END
  END rec[119]
  PIN rec[11]
    DIRECTION INPUT ;
    USE SIGNAL ;
    PORT
      LAYER M5 ;
        RECT  41.232 0 41.256 0.084 ;
    END
  END rec[11]
  PIN rec[120]
    DIRECTION INPUT ;
    USE SIGNAL ;
    PORT
      LAYER M5 ;
        RECT  52.992 0 53.016 0.084 ;
    END
  END rec[120]
  PIN rec[121]
    DIRECTION INPUT ;
    USE SIGNAL ;
    PORT
      LAYER M5 ;
        RECT  53.04 0 53.064 0.084 ;
    END
  END rec[121]
  PIN rec[122]
    DIRECTION INPUT ;
    USE SIGNAL ;
    PORT
      LAYER M5 ;
        RECT  53.088 0 53.112 0.084 ;
    END
  END rec[122]
  PIN rec[123]
    DIRECTION INPUT ;
    USE SIGNAL ;
    PORT
      LAYER M5 ;
        RECT  53.136 0 53.16 0.084 ;
    END
  END rec[123]
  PIN rec[124]
    DIRECTION INPUT ;
    USE SIGNAL ;
    PORT
      LAYER M5 ;
        RECT  53.184 0 53.208 0.084 ;
    END
  END rec[124]
  PIN rec[125]
    DIRECTION INPUT ;
    USE SIGNAL ;
    PORT
      LAYER M5 ;
        RECT  53.232 0 53.256 0.084 ;
    END
  END rec[125]
  PIN rec[126]
    DIRECTION INPUT ;
    USE SIGNAL ;
    PORT
      LAYER M5 ;
        RECT  53.28 0 53.304 0.084 ;
    END
  END rec[126]
  PIN rec[127]
    DIRECTION INPUT ;
    USE SIGNAL ;
    PORT
      LAYER M5 ;
        RECT  62.928 0 62.952 0.084 ;
    END
  END rec[127]
  PIN rec[128]
    DIRECTION INPUT ;
    USE SIGNAL ;
    PORT
      LAYER M5 ;
        RECT  62.976 0 63 0.084 ;
    END
  END rec[128]
  PIN rec[129]
    DIRECTION INPUT ;
    USE SIGNAL ;
    PORT
      LAYER M5 ;
        RECT  63.024 0 63.048 0.084 ;
    END
  END rec[129]
  PIN rec[12]
    DIRECTION INPUT ;
    USE SIGNAL ;
    PORT
      LAYER M5 ;
        RECT  41.28 0 41.304 0.084 ;
    END
  END rec[12]
  PIN rec[130]
    DIRECTION INPUT ;
    USE SIGNAL ;
    PORT
      LAYER M5 ;
        RECT  63.072 0 63.096 0.084 ;
    END
  END rec[130]
  PIN rec[131]
    DIRECTION INPUT ;
    USE SIGNAL ;
    PORT
      LAYER M5 ;
        RECT  63.12 0 63.144 0.084 ;
    END
  END rec[131]
  PIN rec[132]
    DIRECTION INPUT ;
    USE SIGNAL ;
    PORT
      LAYER M5 ;
        RECT  63.168 0 63.192 0.084 ;
    END
  END rec[132]
  PIN rec[133]
    DIRECTION INPUT ;
    USE SIGNAL ;
    PORT
      LAYER M5 ;
        RECT  63.216 0 63.24 0.084 ;
    END
  END rec[133]
  PIN rec[134]
    DIRECTION INPUT ;
    USE SIGNAL ;
    PORT
      LAYER M5 ;
        RECT  63.264 0 63.288 0.084 ;
    END
  END rec[134]
  PIN rec[135]
    DIRECTION INPUT ;
    USE SIGNAL ;
    PORT
      LAYER M5 ;
        RECT  63.312 0 63.336 0.084 ;
    END
  END rec[135]
  PIN rec[136]
    DIRECTION INPUT ;
    USE SIGNAL ;
    PORT
      LAYER M5 ;
        RECT  63.36 0 63.384 0.084 ;
    END
  END rec[136]
  PIN rec[137]
    DIRECTION INPUT ;
    USE SIGNAL ;
    PORT
      LAYER M5 ;
        RECT  63.408 0 63.432 0.084 ;
    END
  END rec[137]
  PIN rec[138]
    DIRECTION INPUT ;
    USE SIGNAL ;
    PORT
      LAYER M5 ;
        RECT  63.456 0 63.48 0.084 ;
    END
  END rec[138]
  PIN rec[139]
    DIRECTION INPUT ;
    USE SIGNAL ;
    PORT
      LAYER M5 ;
        RECT  63.504 0 63.528 0.084 ;
    END
  END rec[139]
  PIN rec[13]
    DIRECTION INPUT ;
    USE SIGNAL ;
    PORT
      LAYER M5 ;
        RECT  41.328 0 41.352 0.084 ;
    END
  END rec[13]
  PIN rec[140]
    DIRECTION INPUT ;
    USE SIGNAL ;
    PORT
      LAYER M5 ;
        RECT  63.552 0 63.576 0.084 ;
    END
  END rec[140]
  PIN rec[141]
    DIRECTION INPUT ;
    USE SIGNAL ;
    PORT
      LAYER M5 ;
        RECT  63.6 0 63.624 0.084 ;
    END
  END rec[141]
  PIN rec[142]
    DIRECTION INPUT ;
    USE SIGNAL ;
    PORT
      LAYER M5 ;
        RECT  63.648 0 63.672 0.084 ;
    END
  END rec[142]
  PIN rec[143]
    DIRECTION INPUT ;
    USE SIGNAL ;
    PORT
      LAYER M5 ;
        RECT  63.696 0 63.72 0.084 ;
    END
  END rec[143]
  PIN rec[144]
    DIRECTION INPUT ;
    USE SIGNAL ;
    PORT
      LAYER M5 ;
        RECT  63.744 0 63.768 0.084 ;
    END
  END rec[144]
  PIN rec[145]
    DIRECTION INPUT ;
    USE SIGNAL ;
    PORT
      LAYER M5 ;
        RECT  63.792 0 63.816 0.084 ;
    END
  END rec[145]
  PIN rec[146]
    DIRECTION INPUT ;
    USE SIGNAL ;
    PORT
      LAYER M5 ;
        RECT  63.84 0 63.864 0.084 ;
    END
  END rec[146]
  PIN rec[147]
    DIRECTION INPUT ;
    USE SIGNAL ;
    PORT
      LAYER M5 ;
        RECT  63.888 0 63.912 0.084 ;
    END
  END rec[147]
  PIN rec[148]
    DIRECTION INPUT ;
    USE SIGNAL ;
    PORT
      LAYER M5 ;
        RECT  63.936 0 63.96 0.084 ;
    END
  END rec[148]
  PIN rec[149]
    DIRECTION INPUT ;
    USE SIGNAL ;
    PORT
      LAYER M5 ;
        RECT  63.984 0 64.008 0.084 ;
    END
  END rec[149]
  PIN rec[14]
    DIRECTION INPUT ;
    USE SIGNAL ;
    PORT
      LAYER M5 ;
        RECT  41.376 0 41.4 0.084 ;
    END
  END rec[14]
  PIN rec[150]
    DIRECTION INPUT ;
    USE SIGNAL ;
    PORT
      LAYER M5 ;
        RECT  64.032 0 64.056 0.084 ;
    END
  END rec[150]
  PIN rec[151]
    DIRECTION INPUT ;
    USE SIGNAL ;
    PORT
      LAYER M5 ;
        RECT  64.08 0 64.104 0.084 ;
    END
  END rec[151]
  PIN rec[152]
    DIRECTION INPUT ;
    USE SIGNAL ;
    PORT
      LAYER M5 ;
        RECT  64.128 0 64.152 0.084 ;
    END
  END rec[152]
  PIN rec[153]
    DIRECTION INPUT ;
    USE SIGNAL ;
    PORT
      LAYER M5 ;
        RECT  64.176 0 64.2 0.084 ;
    END
  END rec[153]
  PIN rec[154]
    DIRECTION INPUT ;
    USE SIGNAL ;
    PORT
      LAYER M5 ;
        RECT  64.224 0 64.248 0.084 ;
    END
  END rec[154]
  PIN rec[155]
    DIRECTION INPUT ;
    USE SIGNAL ;
    PORT
      LAYER M5 ;
        RECT  64.272 0 64.296 0.084 ;
    END
  END rec[155]
  PIN rec[156]
    DIRECTION INPUT ;
    USE SIGNAL ;
    PORT
      LAYER M5 ;
        RECT  64.32 0 64.344 0.084 ;
    END
  END rec[156]
  PIN rec[157]
    DIRECTION INPUT ;
    USE SIGNAL ;
    PORT
      LAYER M5 ;
        RECT  64.368 0 64.392 0.084 ;
    END
  END rec[157]
  PIN rec[158]
    DIRECTION INPUT ;
    USE SIGNAL ;
    PORT
      LAYER M5 ;
        RECT  64.416 0 64.44 0.084 ;
    END
  END rec[158]
  PIN rec[159]
    DIRECTION INPUT ;
    USE SIGNAL ;
    PORT
      LAYER M5 ;
        RECT  64.464 0 64.488 0.084 ;
    END
  END rec[159]
  PIN rec[15]
    DIRECTION INPUT ;
    USE SIGNAL ;
    PORT
      LAYER M5 ;
        RECT  41.424 0 41.448 0.084 ;
    END
  END rec[15]
  PIN rec[160]
    DIRECTION INPUT ;
    USE SIGNAL ;
    PORT
      LAYER M5 ;
        RECT  64.512 0 64.536 0.084 ;
    END
  END rec[160]
  PIN rec[161]
    DIRECTION INPUT ;
    USE SIGNAL ;
    PORT
      LAYER M5 ;
        RECT  64.56 0 64.584 0.084 ;
    END
  END rec[161]
  PIN rec[162]
    DIRECTION INPUT ;
    USE SIGNAL ;
    PORT
      LAYER M5 ;
        RECT  64.608 0 64.632 0.084 ;
    END
  END rec[162]
  PIN rec[163]
    DIRECTION INPUT ;
    USE SIGNAL ;
    PORT
      LAYER M5 ;
        RECT  64.656 0 64.68 0.084 ;
    END
  END rec[163]
  PIN rec[164]
    DIRECTION INPUT ;
    USE SIGNAL ;
    PORT
      LAYER M5 ;
        RECT  64.704 0 64.728 0.084 ;
    END
  END rec[164]
  PIN rec[165]
    DIRECTION INPUT ;
    USE SIGNAL ;
    PORT
      LAYER M5 ;
        RECT  64.752 0 64.776 0.084 ;
    END
  END rec[165]
  PIN rec[166]
    DIRECTION INPUT ;
    USE SIGNAL ;
    PORT
      LAYER M5 ;
        RECT  64.8 0 64.824 0.084 ;
    END
  END rec[166]
  PIN rec[167]
    DIRECTION INPUT ;
    USE SIGNAL ;
    PORT
      LAYER M5 ;
        RECT  64.848 0 64.872 0.084 ;
    END
  END rec[167]
  PIN rec[168]
    DIRECTION INPUT ;
    USE SIGNAL ;
    PORT
      LAYER M5 ;
        RECT  64.896 0 64.92 0.084 ;
    END
  END rec[168]
  PIN rec[169]
    DIRECTION INPUT ;
    USE SIGNAL ;
    PORT
      LAYER M5 ;
        RECT  64.944 0 64.968 0.084 ;
    END
  END rec[169]
  PIN rec[16]
    DIRECTION INPUT ;
    USE SIGNAL ;
    PORT
      LAYER M5 ;
        RECT  41.472 0 41.496 0.084 ;
    END
  END rec[16]
  PIN rec[170]
    DIRECTION INPUT ;
    USE SIGNAL ;
    PORT
      LAYER M5 ;
        RECT  64.992 0 65.016 0.084 ;
    END
  END rec[170]
  PIN rec[171]
    DIRECTION INPUT ;
    USE SIGNAL ;
    PORT
      LAYER M5 ;
        RECT  65.04 0 65.064 0.084 ;
    END
  END rec[171]
  PIN rec[172]
    DIRECTION INPUT ;
    USE SIGNAL ;
    PORT
      LAYER M5 ;
        RECT  65.088 0 65.112 0.084 ;
    END
  END rec[172]
  PIN rec[173]
    DIRECTION INPUT ;
    USE SIGNAL ;
    PORT
      LAYER M5 ;
        RECT  65.136 0 65.16 0.084 ;
    END
  END rec[173]
  PIN rec[174]
    DIRECTION INPUT ;
    USE SIGNAL ;
    PORT
      LAYER M5 ;
        RECT  65.184 0 65.208 0.084 ;
    END
  END rec[174]
  PIN rec[175]
    DIRECTION INPUT ;
    USE SIGNAL ;
    PORT
      LAYER M5 ;
        RECT  65.232 0 65.256 0.084 ;
    END
  END rec[175]
  PIN rec[176]
    DIRECTION INPUT ;
    USE SIGNAL ;
    PORT
      LAYER M5 ;
        RECT  65.28 0 65.304 0.084 ;
    END
  END rec[176]
  PIN rec[177]
    DIRECTION INPUT ;
    USE SIGNAL ;
    PORT
      LAYER M5 ;
        RECT  65.328 0 65.352 0.084 ;
    END
  END rec[177]
  PIN rec[178]
    DIRECTION INPUT ;
    USE SIGNAL ;
    PORT
      LAYER M5 ;
        RECT  65.376 0 65.4 0.084 ;
    END
  END rec[178]
  PIN rec[179]
    DIRECTION INPUT ;
    USE SIGNAL ;
    PORT
      LAYER M5 ;
        RECT  65.424 0 65.448 0.084 ;
    END
  END rec[179]
  PIN rec[17]
    DIRECTION INPUT ;
    USE SIGNAL ;
    PORT
      LAYER M5 ;
        RECT  41.52 0 41.544 0.084 ;
    END
  END rec[17]
  PIN rec[180]
    DIRECTION INPUT ;
    USE SIGNAL ;
    PORT
      LAYER M5 ;
        RECT  65.472 0 65.496 0.084 ;
    END
  END rec[180]
  PIN rec[181]
    DIRECTION INPUT ;
    USE SIGNAL ;
    PORT
      LAYER M5 ;
        RECT  65.52 0 65.544 0.084 ;
    END
  END rec[181]
  PIN rec[182]
    DIRECTION INPUT ;
    USE SIGNAL ;
    PORT
      LAYER M5 ;
        RECT  65.568 0 65.592 0.084 ;
    END
  END rec[182]
  PIN rec[183]
    DIRECTION INPUT ;
    USE SIGNAL ;
    PORT
      LAYER M5 ;
        RECT  65.616 0 65.64 0.084 ;
    END
  END rec[183]
  PIN rec[184]
    DIRECTION INPUT ;
    USE SIGNAL ;
    PORT
      LAYER M5 ;
        RECT  65.664 0 65.688 0.084 ;
    END
  END rec[184]
  PIN rec[185]
    DIRECTION INPUT ;
    USE SIGNAL ;
    PORT
      LAYER M5 ;
        RECT  65.712 0 65.736 0.084 ;
    END
  END rec[185]
  PIN rec[186]
    DIRECTION INPUT ;
    USE SIGNAL ;
    PORT
      LAYER M5 ;
        RECT  65.76 0 65.784 0.084 ;
    END
  END rec[186]
  PIN rec[187]
    DIRECTION INPUT ;
    USE SIGNAL ;
    PORT
      LAYER M5 ;
        RECT  65.808 0 65.832 0.084 ;
    END
  END rec[187]
  PIN rec[188]
    DIRECTION INPUT ;
    USE SIGNAL ;
    PORT
      LAYER M5 ;
        RECT  65.856 0 65.88 0.084 ;
    END
  END rec[188]
  PIN rec[189]
    DIRECTION INPUT ;
    USE SIGNAL ;
    PORT
      LAYER M5 ;
        RECT  65.904 0 65.928 0.084 ;
    END
  END rec[189]
  PIN rec[18]
    DIRECTION INPUT ;
    USE SIGNAL ;
    PORT
      LAYER M5 ;
        RECT  41.568 0 41.592 0.084 ;
    END
  END rec[18]
  PIN rec[190]
    DIRECTION INPUT ;
    USE SIGNAL ;
    PORT
      LAYER M5 ;
        RECT  65.952 0 65.976 0.084 ;
    END
  END rec[190]
  PIN rec[191]
    DIRECTION INPUT ;
    USE SIGNAL ;
    PORT
      LAYER M5 ;
        RECT  42.192 0 42.216 0.084 ;
    END
  END rec[191]
  PIN rec[192]
    DIRECTION INPUT ;
    USE SIGNAL ;
    PORT
      LAYER M5 ;
        RECT  42.24 0 42.264 0.084 ;
    END
  END rec[192]
  PIN rec[193]
    DIRECTION INPUT ;
    USE SIGNAL ;
    PORT
      LAYER M5 ;
        RECT  42.288 0 42.312 0.084 ;
    END
  END rec[193]
  PIN rec[194]
    DIRECTION INPUT ;
    USE SIGNAL ;
    PORT
      LAYER M5 ;
        RECT  42.336 0 42.36 0.084 ;
    END
  END rec[194]
  PIN rec[195]
    DIRECTION INPUT ;
    USE SIGNAL ;
    PORT
      LAYER M5 ;
        RECT  42.384 0 42.408 0.084 ;
    END
  END rec[195]
  PIN rec[196]
    DIRECTION INPUT ;
    USE SIGNAL ;
    PORT
      LAYER M5 ;
        RECT  42.432 0 42.456 0.084 ;
    END
  END rec[196]
  PIN rec[197]
    DIRECTION INPUT ;
    USE SIGNAL ;
    PORT
      LAYER M5 ;
        RECT  42.48 0 42.504 0.084 ;
    END
  END rec[197]
  PIN rec[198]
    DIRECTION INPUT ;
    USE SIGNAL ;
    PORT
      LAYER M5 ;
        RECT  42.528 0 42.552 0.084 ;
    END
  END rec[198]
  PIN rec[199]
    DIRECTION INPUT ;
    USE SIGNAL ;
    PORT
      LAYER M5 ;
        RECT  42.576 0 42.6 0.084 ;
    END
  END rec[199]
  PIN rec[19]
    DIRECTION INPUT ;
    USE SIGNAL ;
    PORT
      LAYER M5 ;
        RECT  41.616 0 41.64 0.084 ;
    END
  END rec[19]
  PIN rec[1]
    DIRECTION INPUT ;
    USE SIGNAL ;
    PORT
      LAYER M5 ;
        RECT  40.752 0 40.776 0.084 ;
    END
  END rec[1]
  PIN rec[200]
    DIRECTION INPUT ;
    USE SIGNAL ;
    PORT
      LAYER M5 ;
        RECT  42.624 0 42.648 0.084 ;
    END
  END rec[200]
  PIN rec[201]
    DIRECTION INPUT ;
    USE SIGNAL ;
    PORT
      LAYER M5 ;
        RECT  42.672 0 42.696 0.084 ;
    END
  END rec[201]
  PIN rec[202]
    DIRECTION INPUT ;
    USE SIGNAL ;
    PORT
      LAYER M5 ;
        RECT  42.72 0 42.744 0.084 ;
    END
  END rec[202]
  PIN rec[203]
    DIRECTION INPUT ;
    USE SIGNAL ;
    PORT
      LAYER M5 ;
        RECT  42.768 0 42.792 0.084 ;
    END
  END rec[203]
  PIN rec[204]
    DIRECTION INPUT ;
    USE SIGNAL ;
    PORT
      LAYER M5 ;
        RECT  42.816 0 42.84 0.084 ;
    END
  END rec[204]
  PIN rec[205]
    DIRECTION INPUT ;
    USE SIGNAL ;
    PORT
      LAYER M5 ;
        RECT  42.864 0 42.888 0.084 ;
    END
  END rec[205]
  PIN rec[206]
    DIRECTION INPUT ;
    USE SIGNAL ;
    PORT
      LAYER M5 ;
        RECT  42.912 0 42.936 0.084 ;
    END
  END rec[206]
  PIN rec[207]
    DIRECTION INPUT ;
    USE SIGNAL ;
    PORT
      LAYER M5 ;
        RECT  42.96 0 42.984 0.084 ;
    END
  END rec[207]
  PIN rec[208]
    DIRECTION INPUT ;
    USE SIGNAL ;
    PORT
      LAYER M5 ;
        RECT  43.008 0 43.032 0.084 ;
    END
  END rec[208]
  PIN rec[209]
    DIRECTION INPUT ;
    USE SIGNAL ;
    PORT
      LAYER M5 ;
        RECT  43.056 0 43.08 0.084 ;
    END
  END rec[209]
  PIN rec[20]
    DIRECTION INPUT ;
    USE SIGNAL ;
    PORT
      LAYER M5 ;
        RECT  41.664 0 41.688 0.084 ;
    END
  END rec[20]
  PIN rec[210]
    DIRECTION INPUT ;
    USE SIGNAL ;
    PORT
      LAYER M5 ;
        RECT  43.104 0 43.128 0.084 ;
    END
  END rec[210]
  PIN rec[211]
    DIRECTION INPUT ;
    USE SIGNAL ;
    PORT
      LAYER M5 ;
        RECT  43.152 0 43.176 0.084 ;
    END
  END rec[211]
  PIN rec[212]
    DIRECTION INPUT ;
    USE SIGNAL ;
    PORT
      LAYER M5 ;
        RECT  43.2 0 43.224 0.084 ;
    END
  END rec[212]
  PIN rec[213]
    DIRECTION INPUT ;
    USE SIGNAL ;
    PORT
      LAYER M5 ;
        RECT  43.248 0 43.272 0.084 ;
    END
  END rec[213]
  PIN rec[214]
    DIRECTION INPUT ;
    USE SIGNAL ;
    PORT
      LAYER M5 ;
        RECT  43.296 0 43.32 0.084 ;
    END
  END rec[214]
  PIN rec[215]
    DIRECTION INPUT ;
    USE SIGNAL ;
    PORT
      LAYER M5 ;
        RECT  43.344 0 43.368 0.084 ;
    END
  END rec[215]
  PIN rec[216]
    DIRECTION INPUT ;
    USE SIGNAL ;
    PORT
      LAYER M5 ;
        RECT  43.392 0 43.416 0.084 ;
    END
  END rec[216]
  PIN rec[217]
    DIRECTION INPUT ;
    USE SIGNAL ;
    PORT
      LAYER M5 ;
        RECT  43.44 0 43.464 0.084 ;
    END
  END rec[217]
  PIN rec[218]
    DIRECTION INPUT ;
    USE SIGNAL ;
    PORT
      LAYER M5 ;
        RECT  43.488 0 43.512 0.084 ;
    END
  END rec[218]
  PIN rec[219]
    DIRECTION INPUT ;
    USE SIGNAL ;
    PORT
      LAYER M5 ;
        RECT  43.536 0 43.56 0.084 ;
    END
  END rec[219]
  PIN rec[21]
    DIRECTION INPUT ;
    USE SIGNAL ;
    PORT
      LAYER M5 ;
        RECT  41.712 0 41.736 0.084 ;
    END
  END rec[21]
  PIN rec[220]
    DIRECTION INPUT ;
    USE SIGNAL ;
    PORT
      LAYER M5 ;
        RECT  43.584 0 43.608 0.084 ;
    END
  END rec[220]
  PIN rec[221]
    DIRECTION INPUT ;
    USE SIGNAL ;
    PORT
      LAYER M5 ;
        RECT  43.632 0 43.656 0.084 ;
    END
  END rec[221]
  PIN rec[222]
    DIRECTION INPUT ;
    USE SIGNAL ;
    PORT
      LAYER M5 ;
        RECT  43.68 0 43.704 0.084 ;
    END
  END rec[222]
  PIN rec[223]
    DIRECTION INPUT ;
    USE SIGNAL ;
    PORT
      LAYER M5 ;
        RECT  74.064 0 74.088 0.084 ;
    END
  END rec[223]
  PIN rec[224]
    DIRECTION INPUT ;
    USE SIGNAL ;
    PORT
      LAYER M5 ;
        RECT  74.112 0 74.136 0.084 ;
    END
  END rec[224]
  PIN rec[225]
    DIRECTION INPUT ;
    USE SIGNAL ;
    PORT
      LAYER M5 ;
        RECT  74.16 0 74.184 0.084 ;
    END
  END rec[225]
  PIN rec[226]
    DIRECTION INPUT ;
    USE SIGNAL ;
    PORT
      LAYER M5 ;
        RECT  74.208 0 74.232 0.084 ;
    END
  END rec[226]
  PIN rec[227]
    DIRECTION INPUT ;
    USE SIGNAL ;
    PORT
      LAYER M5 ;
        RECT  74.256 0 74.28 0.084 ;
    END
  END rec[227]
  PIN rec[228]
    DIRECTION INPUT ;
    USE SIGNAL ;
    PORT
      LAYER M5 ;
        RECT  74.304 0 74.328 0.084 ;
    END
  END rec[228]
  PIN rec[229]
    DIRECTION INPUT ;
    USE SIGNAL ;
    PORT
      LAYER M5 ;
        RECT  74.352 0 74.376 0.084 ;
    END
  END rec[229]
  PIN rec[22]
    DIRECTION INPUT ;
    USE SIGNAL ;
    PORT
      LAYER M5 ;
        RECT  41.76 0 41.784 0.084 ;
    END
  END rec[22]
  PIN rec[230]
    DIRECTION INPUT ;
    USE SIGNAL ;
    PORT
      LAYER M5 ;
        RECT  74.4 0 74.424 0.084 ;
    END
  END rec[230]
  PIN rec[231]
    DIRECTION INPUT ;
    USE SIGNAL ;
    PORT
      LAYER M5 ;
        RECT  74.448 0 74.472 0.084 ;
    END
  END rec[231]
  PIN rec[232]
    DIRECTION INPUT ;
    USE SIGNAL ;
    PORT
      LAYER M5 ;
        RECT  74.496 0 74.52 0.084 ;
    END
  END rec[232]
  PIN rec[233]
    DIRECTION INPUT ;
    USE SIGNAL ;
    PORT
      LAYER M5 ;
        RECT  74.544 0 74.568 0.084 ;
    END
  END rec[233]
  PIN rec[234]
    DIRECTION INPUT ;
    USE SIGNAL ;
    PORT
      LAYER M5 ;
        RECT  74.592 0 74.616 0.084 ;
    END
  END rec[234]
  PIN rec[235]
    DIRECTION INPUT ;
    USE SIGNAL ;
    PORT
      LAYER M5 ;
        RECT  74.64 0 74.664 0.084 ;
    END
  END rec[235]
  PIN rec[236]
    DIRECTION INPUT ;
    USE SIGNAL ;
    PORT
      LAYER M5 ;
        RECT  74.688 0 74.712 0.084 ;
    END
  END rec[236]
  PIN rec[237]
    DIRECTION INPUT ;
    USE SIGNAL ;
    PORT
      LAYER M5 ;
        RECT  74.736 0 74.76 0.084 ;
    END
  END rec[237]
  PIN rec[238]
    DIRECTION INPUT ;
    USE SIGNAL ;
    PORT
      LAYER M5 ;
        RECT  74.784 0 74.808 0.084 ;
    END
  END rec[238]
  PIN rec[239]
    DIRECTION INPUT ;
    USE SIGNAL ;
    PORT
      LAYER M5 ;
        RECT  74.832 0 74.856 0.084 ;
    END
  END rec[239]
  PIN rec[23]
    DIRECTION INPUT ;
    USE SIGNAL ;
    PORT
      LAYER M5 ;
        RECT  41.808 0 41.832 0.084 ;
    END
  END rec[23]
  PIN rec[240]
    DIRECTION INPUT ;
    USE SIGNAL ;
    PORT
      LAYER M5 ;
        RECT  74.88 0 74.904 0.084 ;
    END
  END rec[240]
  PIN rec[241]
    DIRECTION INPUT ;
    USE SIGNAL ;
    PORT
      LAYER M5 ;
        RECT  74.928 0 74.952 0.084 ;
    END
  END rec[241]
  PIN rec[242]
    DIRECTION INPUT ;
    USE SIGNAL ;
    PORT
      LAYER M5 ;
        RECT  74.976 0 75 0.084 ;
    END
  END rec[242]
  PIN rec[243]
    DIRECTION INPUT ;
    USE SIGNAL ;
    PORT
      LAYER M5 ;
        RECT  75.024 0 75.048 0.084 ;
    END
  END rec[243]
  PIN rec[244]
    DIRECTION INPUT ;
    USE SIGNAL ;
    PORT
      LAYER M5 ;
        RECT  75.072 0 75.096 0.084 ;
    END
  END rec[244]
  PIN rec[245]
    DIRECTION INPUT ;
    USE SIGNAL ;
    PORT
      LAYER M5 ;
        RECT  75.12 0 75.144 0.084 ;
    END
  END rec[245]
  PIN rec[246]
    DIRECTION INPUT ;
    USE SIGNAL ;
    PORT
      LAYER M5 ;
        RECT  75.168 0 75.192 0.084 ;
    END
  END rec[246]
  PIN rec[247]
    DIRECTION INPUT ;
    USE SIGNAL ;
    PORT
      LAYER M5 ;
        RECT  75.216 0 75.24 0.084 ;
    END
  END rec[247]
  PIN rec[248]
    DIRECTION INPUT ;
    USE SIGNAL ;
    PORT
      LAYER M5 ;
        RECT  75.264 0 75.288 0.084 ;
    END
  END rec[248]
  PIN rec[249]
    DIRECTION INPUT ;
    USE SIGNAL ;
    PORT
      LAYER M5 ;
        RECT  75.312 0 75.336 0.084 ;
    END
  END rec[249]
  PIN rec[24]
    DIRECTION INPUT ;
    USE SIGNAL ;
    PORT
      LAYER M5 ;
        RECT  41.856 0 41.88 0.084 ;
    END
  END rec[24]
  PIN rec[250]
    DIRECTION INPUT ;
    USE SIGNAL ;
    PORT
      LAYER M5 ;
        RECT  75.36 0 75.384 0.084 ;
    END
  END rec[250]
  PIN rec[251]
    DIRECTION INPUT ;
    USE SIGNAL ;
    PORT
      LAYER M5 ;
        RECT  75.408 0 75.432 0.084 ;
    END
  END rec[251]
  PIN rec[252]
    DIRECTION INPUT ;
    USE SIGNAL ;
    PORT
      LAYER M5 ;
        RECT  75.456 0 75.48 0.084 ;
    END
  END rec[252]
  PIN rec[253]
    DIRECTION INPUT ;
    USE SIGNAL ;
    PORT
      LAYER M5 ;
        RECT  75.504 0 75.528 0.084 ;
    END
  END rec[253]
  PIN rec[254]
    DIRECTION INPUT ;
    USE SIGNAL ;
    PORT
      LAYER M5 ;
        RECT  75.552 0 75.576 0.084 ;
    END
  END rec[254]
  PIN rec[255]
    DIRECTION INPUT ;
    USE SIGNAL ;
    PORT
      LAYER M5 ;
        RECT  56.4 0 56.424 0.084 ;
    END
  END rec[255]
  PIN rec[256]
    DIRECTION INPUT ;
    USE SIGNAL ;
    PORT
      LAYER M5 ;
        RECT  56.448 0 56.472 0.084 ;
    END
  END rec[256]
  PIN rec[257]
    DIRECTION INPUT ;
    USE SIGNAL ;
    PORT
      LAYER M5 ;
        RECT  56.496 0 56.52 0.084 ;
    END
  END rec[257]
  PIN rec[258]
    DIRECTION INPUT ;
    USE SIGNAL ;
    PORT
      LAYER M5 ;
        RECT  56.544 0 56.568 0.084 ;
    END
  END rec[258]
  PIN rec[259]
    DIRECTION INPUT ;
    USE SIGNAL ;
    PORT
      LAYER M5 ;
        RECT  56.592 0 56.616 0.084 ;
    END
  END rec[259]
  PIN rec[25]
    DIRECTION INPUT ;
    USE SIGNAL ;
    PORT
      LAYER M5 ;
        RECT  41.904 0 41.928 0.084 ;
    END
  END rec[25]
  PIN rec[260]
    DIRECTION INPUT ;
    USE SIGNAL ;
    PORT
      LAYER M5 ;
        RECT  56.64 0 56.664 0.084 ;
    END
  END rec[260]
  PIN rec[261]
    DIRECTION INPUT ;
    USE SIGNAL ;
    PORT
      LAYER M5 ;
        RECT  56.688 0 56.712 0.084 ;
    END
  END rec[261]
  PIN rec[262]
    DIRECTION INPUT ;
    USE SIGNAL ;
    PORT
      LAYER M5 ;
        RECT  56.736 0 56.76 0.084 ;
    END
  END rec[262]
  PIN rec[263]
    DIRECTION INPUT ;
    USE SIGNAL ;
    PORT
      LAYER M5 ;
        RECT  56.784 0 56.808 0.084 ;
    END
  END rec[263]
  PIN rec[264]
    DIRECTION INPUT ;
    USE SIGNAL ;
    PORT
      LAYER M5 ;
        RECT  56.832 0 56.856 0.084 ;
    END
  END rec[264]
  PIN rec[265]
    DIRECTION INPUT ;
    USE SIGNAL ;
    PORT
      LAYER M5 ;
        RECT  56.88 0 56.904 0.084 ;
    END
  END rec[265]
  PIN rec[266]
    DIRECTION INPUT ;
    USE SIGNAL ;
    PORT
      LAYER M5 ;
        RECT  56.928 0 56.952 0.084 ;
    END
  END rec[266]
  PIN rec[267]
    DIRECTION INPUT ;
    USE SIGNAL ;
    PORT
      LAYER M5 ;
        RECT  56.976 0 57 0.084 ;
    END
  END rec[267]
  PIN rec[268]
    DIRECTION INPUT ;
    USE SIGNAL ;
    PORT
      LAYER M5 ;
        RECT  57.024 0 57.048 0.084 ;
    END
  END rec[268]
  PIN rec[269]
    DIRECTION INPUT ;
    USE SIGNAL ;
    PORT
      LAYER M5 ;
        RECT  57.072 0 57.096 0.084 ;
    END
  END rec[269]
  PIN rec[26]
    DIRECTION INPUT ;
    USE SIGNAL ;
    PORT
      LAYER M5 ;
        RECT  41.952 0 41.976 0.084 ;
    END
  END rec[26]
  PIN rec[270]
    DIRECTION INPUT ;
    USE SIGNAL ;
    PORT
      LAYER M5 ;
        RECT  57.12 0 57.144 0.084 ;
    END
  END rec[270]
  PIN rec[271]
    DIRECTION INPUT ;
    USE SIGNAL ;
    PORT
      LAYER M5 ;
        RECT  57.168 0 57.192 0.084 ;
    END
  END rec[271]
  PIN rec[272]
    DIRECTION INPUT ;
    USE SIGNAL ;
    PORT
      LAYER M5 ;
        RECT  57.216 0 57.24 0.084 ;
    END
  END rec[272]
  PIN rec[273]
    DIRECTION INPUT ;
    USE SIGNAL ;
    PORT
      LAYER M5 ;
        RECT  57.264 0 57.288 0.084 ;
    END
  END rec[273]
  PIN rec[274]
    DIRECTION INPUT ;
    USE SIGNAL ;
    PORT
      LAYER M5 ;
        RECT  57.312 0 57.336 0.084 ;
    END
  END rec[274]
  PIN rec[275]
    DIRECTION INPUT ;
    USE SIGNAL ;
    PORT
      LAYER M5 ;
        RECT  57.36 0 57.384 0.084 ;
    END
  END rec[275]
  PIN rec[276]
    DIRECTION INPUT ;
    USE SIGNAL ;
    PORT
      LAYER M5 ;
        RECT  57.408 0 57.432 0.084 ;
    END
  END rec[276]
  PIN rec[277]
    DIRECTION INPUT ;
    USE SIGNAL ;
    PORT
      LAYER M5 ;
        RECT  57.456 0 57.48 0.084 ;
    END
  END rec[277]
  PIN rec[278]
    DIRECTION INPUT ;
    USE SIGNAL ;
    PORT
      LAYER M5 ;
        RECT  57.504 0 57.528 0.084 ;
    END
  END rec[278]
  PIN rec[279]
    DIRECTION INPUT ;
    USE SIGNAL ;
    PORT
      LAYER M5 ;
        RECT  57.552 0 57.576 0.084 ;
    END
  END rec[279]
  PIN rec[27]
    DIRECTION INPUT ;
    USE SIGNAL ;
    PORT
      LAYER M5 ;
        RECT  42 0 42.024 0.084 ;
    END
  END rec[27]
  PIN rec[280]
    DIRECTION INPUT ;
    USE SIGNAL ;
    PORT
      LAYER M5 ;
        RECT  57.6 0 57.624 0.084 ;
    END
  END rec[280]
  PIN rec[281]
    DIRECTION INPUT ;
    USE SIGNAL ;
    PORT
      LAYER M5 ;
        RECT  57.648 0 57.672 0.084 ;
    END
  END rec[281]
  PIN rec[282]
    DIRECTION INPUT ;
    USE SIGNAL ;
    PORT
      LAYER M5 ;
        RECT  57.696 0 57.72 0.084 ;
    END
  END rec[282]
  PIN rec[283]
    DIRECTION INPUT ;
    USE SIGNAL ;
    PORT
      LAYER M5 ;
        RECT  57.744 0 57.768 0.084 ;
    END
  END rec[283]
  PIN rec[284]
    DIRECTION INPUT ;
    USE SIGNAL ;
    PORT
      LAYER M5 ;
        RECT  57.792 0 57.816 0.084 ;
    END
  END rec[284]
  PIN rec[285]
    DIRECTION INPUT ;
    USE SIGNAL ;
    PORT
      LAYER M5 ;
        RECT  57.84 0 57.864 0.084 ;
    END
  END rec[285]
  PIN rec[286]
    DIRECTION INPUT ;
    USE SIGNAL ;
    PORT
      LAYER M5 ;
        RECT  57.888 0 57.912 0.084 ;
    END
  END rec[286]
  PIN rec[287]
    DIRECTION INPUT ;
    USE SIGNAL ;
    PORT
      LAYER M5 ;
        RECT  10.32 0 10.344 0.084 ;
    END
  END rec[287]
  PIN rec[288]
    DIRECTION INPUT ;
    USE SIGNAL ;
    PORT
      LAYER M5 ;
        RECT  10.368 0 10.392 0.084 ;
    END
  END rec[288]
  PIN rec[289]
    DIRECTION INPUT ;
    USE SIGNAL ;
    PORT
      LAYER M5 ;
        RECT  10.416 0 10.44 0.084 ;
    END
  END rec[289]
  PIN rec[28]
    DIRECTION INPUT ;
    USE SIGNAL ;
    PORT
      LAYER M5 ;
        RECT  42.048 0 42.072 0.084 ;
    END
  END rec[28]
  PIN rec[290]
    DIRECTION INPUT ;
    USE SIGNAL ;
    PORT
      LAYER M5 ;
        RECT  10.464 0 10.488 0.084 ;
    END
  END rec[290]
  PIN rec[291]
    DIRECTION INPUT ;
    USE SIGNAL ;
    PORT
      LAYER M5 ;
        RECT  10.512 0 10.536 0.084 ;
    END
  END rec[291]
  PIN rec[292]
    DIRECTION INPUT ;
    USE SIGNAL ;
    PORT
      LAYER M5 ;
        RECT  10.56 0 10.584 0.084 ;
    END
  END rec[292]
  PIN rec[293]
    DIRECTION INPUT ;
    USE SIGNAL ;
    PORT
      LAYER M5 ;
        RECT  10.608 0 10.632 0.084 ;
    END
  END rec[293]
  PIN rec[294]
    DIRECTION INPUT ;
    USE SIGNAL ;
    PORT
      LAYER M5 ;
        RECT  10.656 0 10.68 0.084 ;
    END
  END rec[294]
  PIN rec[295]
    DIRECTION INPUT ;
    USE SIGNAL ;
    PORT
      LAYER M5 ;
        RECT  10.704 0 10.728 0.084 ;
    END
  END rec[295]
  PIN rec[296]
    DIRECTION INPUT ;
    USE SIGNAL ;
    PORT
      LAYER M5 ;
        RECT  10.752 0 10.776 0.084 ;
    END
  END rec[296]
  PIN rec[297]
    DIRECTION INPUT ;
    USE SIGNAL ;
    PORT
      LAYER M5 ;
        RECT  10.8 0 10.824 0.084 ;
    END
  END rec[297]
  PIN rec[298]
    DIRECTION INPUT ;
    USE SIGNAL ;
    PORT
      LAYER M5 ;
        RECT  10.848 0 10.872 0.084 ;
    END
  END rec[298]
  PIN rec[299]
    DIRECTION INPUT ;
    USE SIGNAL ;
    PORT
      LAYER M5 ;
        RECT  10.896 0 10.92 0.084 ;
    END
  END rec[299]
  PIN rec[29]
    DIRECTION INPUT ;
    USE SIGNAL ;
    PORT
      LAYER M5 ;
        RECT  42.096 0 42.12 0.084 ;
    END
  END rec[29]
  PIN rec[2]
    DIRECTION INPUT ;
    USE SIGNAL ;
    PORT
      LAYER M5 ;
        RECT  40.8 0 40.824 0.084 ;
    END
  END rec[2]
  PIN rec[300]
    DIRECTION INPUT ;
    USE SIGNAL ;
    PORT
      LAYER M5 ;
        RECT  10.944 0 10.968 0.084 ;
    END
  END rec[300]
  PIN rec[301]
    DIRECTION INPUT ;
    USE SIGNAL ;
    PORT
      LAYER M5 ;
        RECT  10.992 0 11.016 0.084 ;
    END
  END rec[301]
  PIN rec[302]
    DIRECTION INPUT ;
    USE SIGNAL ;
    PORT
      LAYER M5 ;
        RECT  11.04 0 11.064 0.084 ;
    END
  END rec[302]
  PIN rec[303]
    DIRECTION INPUT ;
    USE SIGNAL ;
    PORT
      LAYER M5 ;
        RECT  11.088 0 11.112 0.084 ;
    END
  END rec[303]
  PIN rec[304]
    DIRECTION INPUT ;
    USE SIGNAL ;
    PORT
      LAYER M5 ;
        RECT  11.136 0 11.16 0.084 ;
    END
  END rec[304]
  PIN rec[305]
    DIRECTION INPUT ;
    USE SIGNAL ;
    PORT
      LAYER M5 ;
        RECT  11.184 0 11.208 0.084 ;
    END
  END rec[305]
  PIN rec[306]
    DIRECTION INPUT ;
    USE SIGNAL ;
    PORT
      LAYER M5 ;
        RECT  11.232 0 11.256 0.084 ;
    END
  END rec[306]
  PIN rec[307]
    DIRECTION INPUT ;
    USE SIGNAL ;
    PORT
      LAYER M5 ;
        RECT  11.28 0 11.304 0.084 ;
    END
  END rec[307]
  PIN rec[308]
    DIRECTION INPUT ;
    USE SIGNAL ;
    PORT
      LAYER M5 ;
        RECT  11.328 0 11.352 0.084 ;
    END
  END rec[308]
  PIN rec[309]
    DIRECTION INPUT ;
    USE SIGNAL ;
    PORT
      LAYER M5 ;
        RECT  11.376 0 11.4 0.084 ;
    END
  END rec[309]
  PIN rec[30]
    DIRECTION INPUT ;
    USE SIGNAL ;
    PORT
      LAYER M5 ;
        RECT  42.144 0 42.168 0.084 ;
    END
  END rec[30]
  PIN rec[310]
    DIRECTION INPUT ;
    USE SIGNAL ;
    PORT
      LAYER M5 ;
        RECT  11.424 0 11.448 0.084 ;
    END
  END rec[310]
  PIN rec[311]
    DIRECTION INPUT ;
    USE SIGNAL ;
    PORT
      LAYER M5 ;
        RECT  11.472 0 11.496 0.084 ;
    END
  END rec[311]
  PIN rec[312]
    DIRECTION INPUT ;
    USE SIGNAL ;
    PORT
      LAYER M5 ;
        RECT  11.52 0 11.544 0.084 ;
    END
  END rec[312]
  PIN rec[313]
    DIRECTION INPUT ;
    USE SIGNAL ;
    PORT
      LAYER M5 ;
        RECT  11.568 0 11.592 0.084 ;
    END
  END rec[313]
  PIN rec[314]
    DIRECTION INPUT ;
    USE SIGNAL ;
    PORT
      LAYER M5 ;
        RECT  11.616 0 11.64 0.084 ;
    END
  END rec[314]
  PIN rec[315]
    DIRECTION INPUT ;
    USE SIGNAL ;
    PORT
      LAYER M5 ;
        RECT  11.664 0 11.688 0.084 ;
    END
  END rec[315]
  PIN rec[316]
    DIRECTION INPUT ;
    USE SIGNAL ;
    PORT
      LAYER M5 ;
        RECT  11.712 0 11.736 0.084 ;
    END
  END rec[316]
  PIN rec[317]
    DIRECTION INPUT ;
    USE SIGNAL ;
    PORT
      LAYER M5 ;
        RECT  11.76 0 11.784 0.084 ;
    END
  END rec[317]
  PIN rec[318]
    DIRECTION INPUT ;
    USE SIGNAL ;
    PORT
      LAYER M5 ;
        RECT  11.808 0 11.832 0.084 ;
    END
  END rec[318]
  PIN rec[319]
    DIRECTION INPUT ;
    USE SIGNAL ;
    PORT
      LAYER M5 ;
        RECT  19.92 0 19.944 0.084 ;
    END
  END rec[319]
  PIN rec[31]
    DIRECTION INPUT ;
    USE SIGNAL ;
    PORT
      LAYER M5 ;
        RECT  0.72 0 0.744 0.084 ;
    END
  END rec[31]
  PIN rec[320]
    DIRECTION INPUT ;
    USE SIGNAL ;
    PORT
      LAYER M5 ;
        RECT  19.968 0 19.992 0.084 ;
    END
  END rec[320]
  PIN rec[321]
    DIRECTION INPUT ;
    USE SIGNAL ;
    PORT
      LAYER M5 ;
        RECT  20.016 0 20.04 0.084 ;
    END
  END rec[321]
  PIN rec[322]
    DIRECTION INPUT ;
    USE SIGNAL ;
    PORT
      LAYER M5 ;
        RECT  20.064 0 20.088 0.084 ;
    END
  END rec[322]
  PIN rec[323]
    DIRECTION INPUT ;
    USE SIGNAL ;
    PORT
      LAYER M5 ;
        RECT  20.112 0 20.136 0.084 ;
    END
  END rec[323]
  PIN rec[324]
    DIRECTION INPUT ;
    USE SIGNAL ;
    PORT
      LAYER M5 ;
        RECT  20.16 0 20.184 0.084 ;
    END
  END rec[324]
  PIN rec[325]
    DIRECTION INPUT ;
    USE SIGNAL ;
    PORT
      LAYER M5 ;
        RECT  20.208 0 20.232 0.084 ;
    END
  END rec[325]
  PIN rec[326]
    DIRECTION INPUT ;
    USE SIGNAL ;
    PORT
      LAYER M5 ;
        RECT  20.256 0 20.28 0.084 ;
    END
  END rec[326]
  PIN rec[327]
    DIRECTION INPUT ;
    USE SIGNAL ;
    PORT
      LAYER M5 ;
        RECT  20.304 0 20.328 0.084 ;
    END
  END rec[327]
  PIN rec[328]
    DIRECTION INPUT ;
    USE SIGNAL ;
    PORT
      LAYER M5 ;
        RECT  20.352 0 20.376 0.084 ;
    END
  END rec[328]
  PIN rec[329]
    DIRECTION INPUT ;
    USE SIGNAL ;
    PORT
      LAYER M5 ;
        RECT  20.4 0 20.424 0.084 ;
    END
  END rec[329]
  PIN rec[32]
    DIRECTION INPUT ;
    USE SIGNAL ;
    PORT
      LAYER M5 ;
        RECT  0.768 0 0.792 0.084 ;
    END
  END rec[32]
  PIN rec[330]
    DIRECTION INPUT ;
    USE SIGNAL ;
    PORT
      LAYER M5 ;
        RECT  20.448 0 20.472 0.084 ;
    END
  END rec[330]
  PIN rec[331]
    DIRECTION INPUT ;
    USE SIGNAL ;
    PORT
      LAYER M5 ;
        RECT  20.496 0 20.52 0.084 ;
    END
  END rec[331]
  PIN rec[332]
    DIRECTION INPUT ;
    USE SIGNAL ;
    PORT
      LAYER M5 ;
        RECT  20.544 0 20.568 0.084 ;
    END
  END rec[332]
  PIN rec[333]
    DIRECTION INPUT ;
    USE SIGNAL ;
    PORT
      LAYER M5 ;
        RECT  20.592 0 20.616 0.084 ;
    END
  END rec[333]
  PIN rec[334]
    DIRECTION INPUT ;
    USE SIGNAL ;
    PORT
      LAYER M5 ;
        RECT  20.64 0 20.664 0.084 ;
    END
  END rec[334]
  PIN rec[335]
    DIRECTION INPUT ;
    USE SIGNAL ;
    PORT
      LAYER M5 ;
        RECT  20.688 0 20.712 0.084 ;
    END
  END rec[335]
  PIN rec[336]
    DIRECTION INPUT ;
    USE SIGNAL ;
    PORT
      LAYER M5 ;
        RECT  20.736 0 20.76 0.084 ;
    END
  END rec[336]
  PIN rec[337]
    DIRECTION INPUT ;
    USE SIGNAL ;
    PORT
      LAYER M5 ;
        RECT  20.784 0 20.808 0.084 ;
    END
  END rec[337]
  PIN rec[338]
    DIRECTION INPUT ;
    USE SIGNAL ;
    PORT
      LAYER M5 ;
        RECT  20.832 0 20.856 0.084 ;
    END
  END rec[338]
  PIN rec[339]
    DIRECTION INPUT ;
    USE SIGNAL ;
    PORT
      LAYER M5 ;
        RECT  20.88 0 20.904 0.084 ;
    END
  END rec[339]
  PIN rec[33]
    DIRECTION INPUT ;
    USE SIGNAL ;
    PORT
      LAYER M5 ;
        RECT  0.816 0 0.84 0.084 ;
    END
  END rec[33]
  PIN rec[340]
    DIRECTION INPUT ;
    USE SIGNAL ;
    PORT
      LAYER M5 ;
        RECT  20.928 0 20.952 0.084 ;
    END
  END rec[340]
  PIN rec[341]
    DIRECTION INPUT ;
    USE SIGNAL ;
    PORT
      LAYER M5 ;
        RECT  20.976 0 21 0.084 ;
    END
  END rec[341]
  PIN rec[342]
    DIRECTION INPUT ;
    USE SIGNAL ;
    PORT
      LAYER M5 ;
        RECT  21.024 0 21.048 0.084 ;
    END
  END rec[342]
  PIN rec[343]
    DIRECTION INPUT ;
    USE SIGNAL ;
    PORT
      LAYER M5 ;
        RECT  21.072 0 21.096 0.084 ;
    END
  END rec[343]
  PIN rec[344]
    DIRECTION INPUT ;
    USE SIGNAL ;
    PORT
      LAYER M5 ;
        RECT  21.12 0 21.144 0.084 ;
    END
  END rec[344]
  PIN rec[345]
    DIRECTION INPUT ;
    USE SIGNAL ;
    PORT
      LAYER M5 ;
        RECT  21.168 0 21.192 0.084 ;
    END
  END rec[345]
  PIN rec[346]
    DIRECTION INPUT ;
    USE SIGNAL ;
    PORT
      LAYER M5 ;
        RECT  21.216 0 21.24 0.084 ;
    END
  END rec[346]
  PIN rec[347]
    DIRECTION INPUT ;
    USE SIGNAL ;
    PORT
      LAYER M5 ;
        RECT  21.264 0 21.288 0.084 ;
    END
  END rec[347]
  PIN rec[348]
    DIRECTION INPUT ;
    USE SIGNAL ;
    PORT
      LAYER M5 ;
        RECT  21.312 0 21.336 0.084 ;
    END
  END rec[348]
  PIN rec[349]
    DIRECTION INPUT ;
    USE SIGNAL ;
    PORT
      LAYER M5 ;
        RECT  21.36 0 21.384 0.084 ;
    END
  END rec[349]
  PIN rec[34]
    DIRECTION INPUT ;
    USE SIGNAL ;
    PORT
      LAYER M5 ;
        RECT  0.864 0 0.888 0.084 ;
    END
  END rec[34]
  PIN rec[350]
    DIRECTION INPUT ;
    USE SIGNAL ;
    PORT
      LAYER M5 ;
        RECT  21.408 0 21.432 0.084 ;
    END
  END rec[350]
  PIN rec[351]
    DIRECTION INPUT ;
    USE SIGNAL ;
    PORT
      LAYER M5 ;
        RECT  29.52 0 29.544 0.084 ;
    END
  END rec[351]
  PIN rec[352]
    DIRECTION INPUT ;
    USE SIGNAL ;
    PORT
      LAYER M5 ;
        RECT  29.568 0 29.592 0.084 ;
    END
  END rec[352]
  PIN rec[353]
    DIRECTION INPUT ;
    USE SIGNAL ;
    PORT
      LAYER M5 ;
        RECT  29.616 0 29.64 0.084 ;
    END
  END rec[353]
  PIN rec[354]
    DIRECTION INPUT ;
    USE SIGNAL ;
    PORT
      LAYER M5 ;
        RECT  29.664 0 29.688 0.084 ;
    END
  END rec[354]
  PIN rec[355]
    DIRECTION INPUT ;
    USE SIGNAL ;
    PORT
      LAYER M5 ;
        RECT  29.712 0 29.736 0.084 ;
    END
  END rec[355]
  PIN rec[356]
    DIRECTION INPUT ;
    USE SIGNAL ;
    PORT
      LAYER M5 ;
        RECT  29.76 0 29.784 0.084 ;
    END
  END rec[356]
  PIN rec[357]
    DIRECTION INPUT ;
    USE SIGNAL ;
    PORT
      LAYER M5 ;
        RECT  29.808 0 29.832 0.084 ;
    END
  END rec[357]
  PIN rec[358]
    DIRECTION INPUT ;
    USE SIGNAL ;
    PORT
      LAYER M5 ;
        RECT  29.856 0 29.88 0.084 ;
    END
  END rec[358]
  PIN rec[359]
    DIRECTION INPUT ;
    USE SIGNAL ;
    PORT
      LAYER M5 ;
        RECT  29.904 0 29.928 0.084 ;
    END
  END rec[359]
  PIN rec[35]
    DIRECTION INPUT ;
    USE SIGNAL ;
    PORT
      LAYER M5 ;
        RECT  0.912 0 0.936 0.084 ;
    END
  END rec[35]
  PIN rec[360]
    DIRECTION INPUT ;
    USE SIGNAL ;
    PORT
      LAYER M5 ;
        RECT  29.952 0 29.976 0.084 ;
    END
  END rec[360]
  PIN rec[361]
    DIRECTION INPUT ;
    USE SIGNAL ;
    PORT
      LAYER M5 ;
        RECT  30 0 30.024 0.084 ;
    END
  END rec[361]
  PIN rec[362]
    DIRECTION INPUT ;
    USE SIGNAL ;
    PORT
      LAYER M5 ;
        RECT  30.048 0 30.072 0.084 ;
    END
  END rec[362]
  PIN rec[363]
    DIRECTION INPUT ;
    USE SIGNAL ;
    PORT
      LAYER M5 ;
        RECT  30.096 0 30.12 0.084 ;
    END
  END rec[363]
  PIN rec[364]
    DIRECTION INPUT ;
    USE SIGNAL ;
    PORT
      LAYER M5 ;
        RECT  30.144 0 30.168 0.084 ;
    END
  END rec[364]
  PIN rec[365]
    DIRECTION INPUT ;
    USE SIGNAL ;
    PORT
      LAYER M5 ;
        RECT  30.192 0 30.216 0.084 ;
    END
  END rec[365]
  PIN rec[366]
    DIRECTION INPUT ;
    USE SIGNAL ;
    PORT
      LAYER M5 ;
        RECT  30.24 0 30.264 0.084 ;
    END
  END rec[366]
  PIN rec[367]
    DIRECTION INPUT ;
    USE SIGNAL ;
    PORT
      LAYER M5 ;
        RECT  30.288 0 30.312 0.084 ;
    END
  END rec[367]
  PIN rec[368]
    DIRECTION INPUT ;
    USE SIGNAL ;
    PORT
      LAYER M5 ;
        RECT  30.336 0 30.36 0.084 ;
    END
  END rec[368]
  PIN rec[369]
    DIRECTION INPUT ;
    USE SIGNAL ;
    PORT
      LAYER M5 ;
        RECT  30.384 0 30.408 0.084 ;
    END
  END rec[369]
  PIN rec[36]
    DIRECTION INPUT ;
    USE SIGNAL ;
    PORT
      LAYER M5 ;
        RECT  0.96 0 0.984 0.084 ;
    END
  END rec[36]
  PIN rec[370]
    DIRECTION INPUT ;
    USE SIGNAL ;
    PORT
      LAYER M5 ;
        RECT  30.432 0 30.456 0.084 ;
    END
  END rec[370]
  PIN rec[371]
    DIRECTION INPUT ;
    USE SIGNAL ;
    PORT
      LAYER M5 ;
        RECT  30.48 0 30.504 0.084 ;
    END
  END rec[371]
  PIN rec[372]
    DIRECTION INPUT ;
    USE SIGNAL ;
    PORT
      LAYER M5 ;
        RECT  30.528 0 30.552 0.084 ;
    END
  END rec[372]
  PIN rec[373]
    DIRECTION INPUT ;
    USE SIGNAL ;
    PORT
      LAYER M5 ;
        RECT  30.576 0 30.6 0.084 ;
    END
  END rec[373]
  PIN rec[374]
    DIRECTION INPUT ;
    USE SIGNAL ;
    PORT
      LAYER M5 ;
        RECT  30.624 0 30.648 0.084 ;
    END
  END rec[374]
  PIN rec[375]
    DIRECTION INPUT ;
    USE SIGNAL ;
    PORT
      LAYER M5 ;
        RECT  30.672 0 30.696 0.084 ;
    END
  END rec[375]
  PIN rec[376]
    DIRECTION INPUT ;
    USE SIGNAL ;
    PORT
      LAYER M5 ;
        RECT  30.72 0 30.744 0.084 ;
    END
  END rec[376]
  PIN rec[377]
    DIRECTION INPUT ;
    USE SIGNAL ;
    PORT
      LAYER M5 ;
        RECT  30.768 0 30.792 0.084 ;
    END
  END rec[377]
  PIN rec[378]
    DIRECTION INPUT ;
    USE SIGNAL ;
    PORT
      LAYER M5 ;
        RECT  30.816 0 30.84 0.084 ;
    END
  END rec[378]
  PIN rec[379]
    DIRECTION INPUT ;
    USE SIGNAL ;
    PORT
      LAYER M5 ;
        RECT  30.864 0 30.888 0.084 ;
    END
  END rec[379]
  PIN rec[37]
    DIRECTION INPUT ;
    USE SIGNAL ;
    PORT
      LAYER M5 ;
        RECT  1.008 0 1.032 0.084 ;
    END
  END rec[37]
  PIN rec[380]
    DIRECTION INPUT ;
    USE SIGNAL ;
    PORT
      LAYER M5 ;
        RECT  30.912 0 30.936 0.084 ;
    END
  END rec[380]
  PIN rec[381]
    DIRECTION INPUT ;
    USE SIGNAL ;
    PORT
      LAYER M5 ;
        RECT  30.96 0 30.984 0.084 ;
    END
  END rec[381]
  PIN rec[382]
    DIRECTION INPUT ;
    USE SIGNAL ;
    PORT
      LAYER M5 ;
        RECT  31.008 0 31.032 0.084 ;
    END
  END rec[382]
  PIN rec[383]
    DIRECTION INPUT ;
    USE SIGNAL ;
    PORT
      LAYER M5 ;
        RECT  66 0 66.024 0.084 ;
    END
  END rec[383]
  PIN rec[384]
    DIRECTION INPUT ;
    USE SIGNAL ;
    PORT
      LAYER M5 ;
        RECT  66.048 0 66.072 0.084 ;
    END
  END rec[384]
  PIN rec[385]
    DIRECTION INPUT ;
    USE SIGNAL ;
    PORT
      LAYER M5 ;
        RECT  66.096 0 66.12 0.084 ;
    END
  END rec[385]
  PIN rec[386]
    DIRECTION INPUT ;
    USE SIGNAL ;
    PORT
      LAYER M5 ;
        RECT  66.144 0 66.168 0.084 ;
    END
  END rec[386]
  PIN rec[387]
    DIRECTION INPUT ;
    USE SIGNAL ;
    PORT
      LAYER M5 ;
        RECT  66.192 0 66.216 0.084 ;
    END
  END rec[387]
  PIN rec[388]
    DIRECTION INPUT ;
    USE SIGNAL ;
    PORT
      LAYER M5 ;
        RECT  66.24 0 66.264 0.084 ;
    END
  END rec[388]
  PIN rec[389]
    DIRECTION INPUT ;
    USE SIGNAL ;
    PORT
      LAYER M5 ;
        RECT  66.288 0 66.312 0.084 ;
    END
  END rec[389]
  PIN rec[38]
    DIRECTION INPUT ;
    USE SIGNAL ;
    PORT
      LAYER M5 ;
        RECT  1.056 0 1.08 0.084 ;
    END
  END rec[38]
  PIN rec[390]
    DIRECTION INPUT ;
    USE SIGNAL ;
    PORT
      LAYER M5 ;
        RECT  66.336 0 66.36 0.084 ;
    END
  END rec[390]
  PIN rec[391]
    DIRECTION INPUT ;
    USE SIGNAL ;
    PORT
      LAYER M5 ;
        RECT  66.384 0 66.408 0.084 ;
    END
  END rec[391]
  PIN rec[392]
    DIRECTION INPUT ;
    USE SIGNAL ;
    PORT
      LAYER M5 ;
        RECT  66.432 0 66.456 0.084 ;
    END
  END rec[392]
  PIN rec[393]
    DIRECTION INPUT ;
    USE SIGNAL ;
    PORT
      LAYER M5 ;
        RECT  66.48 0 66.504 0.084 ;
    END
  END rec[393]
  PIN rec[394]
    DIRECTION INPUT ;
    USE SIGNAL ;
    PORT
      LAYER M5 ;
        RECT  66.528 0 66.552 0.084 ;
    END
  END rec[394]
  PIN rec[395]
    DIRECTION INPUT ;
    USE SIGNAL ;
    PORT
      LAYER M5 ;
        RECT  66.576 0 66.6 0.084 ;
    END
  END rec[395]
  PIN rec[396]
    DIRECTION INPUT ;
    USE SIGNAL ;
    PORT
      LAYER M5 ;
        RECT  66.624 0 66.648 0.084 ;
    END
  END rec[396]
  PIN rec[397]
    DIRECTION INPUT ;
    USE SIGNAL ;
    PORT
      LAYER M5 ;
        RECT  66.672 0 66.696 0.084 ;
    END
  END rec[397]
  PIN rec[398]
    DIRECTION INPUT ;
    USE SIGNAL ;
    PORT
      LAYER M5 ;
        RECT  66.72 0 66.744 0.084 ;
    END
  END rec[398]
  PIN rec[399]
    DIRECTION INPUT ;
    USE SIGNAL ;
    PORT
      LAYER M5 ;
        RECT  66.768 0 66.792 0.084 ;
    END
  END rec[399]
  PIN rec[39]
    DIRECTION INPUT ;
    USE SIGNAL ;
    PORT
      LAYER M5 ;
        RECT  1.104 0 1.128 0.084 ;
    END
  END rec[39]
  PIN rec[3]
    DIRECTION INPUT ;
    USE SIGNAL ;
    PORT
      LAYER M5 ;
        RECT  40.848 0 40.872 0.084 ;
    END
  END rec[3]
  PIN rec[400]
    DIRECTION INPUT ;
    USE SIGNAL ;
    PORT
      LAYER M5 ;
        RECT  66.816 0 66.84 0.084 ;
    END
  END rec[400]
  PIN rec[401]
    DIRECTION INPUT ;
    USE SIGNAL ;
    PORT
      LAYER M5 ;
        RECT  66.864 0 66.888 0.084 ;
    END
  END rec[401]
  PIN rec[402]
    DIRECTION INPUT ;
    USE SIGNAL ;
    PORT
      LAYER M5 ;
        RECT  66.912 0 66.936 0.084 ;
    END
  END rec[402]
  PIN rec[403]
    DIRECTION INPUT ;
    USE SIGNAL ;
    PORT
      LAYER M5 ;
        RECT  66.96 0 66.984 0.084 ;
    END
  END rec[403]
  PIN rec[404]
    DIRECTION INPUT ;
    USE SIGNAL ;
    PORT
      LAYER M5 ;
        RECT  67.008 0 67.032 0.084 ;
    END
  END rec[404]
  PIN rec[405]
    DIRECTION INPUT ;
    USE SIGNAL ;
    PORT
      LAYER M5 ;
        RECT  67.056 0 67.08 0.084 ;
    END
  END rec[405]
  PIN rec[406]
    DIRECTION INPUT ;
    USE SIGNAL ;
    PORT
      LAYER M5 ;
        RECT  67.104 0 67.128 0.084 ;
    END
  END rec[406]
  PIN rec[407]
    DIRECTION INPUT ;
    USE SIGNAL ;
    PORT
      LAYER M5 ;
        RECT  67.152 0 67.176 0.084 ;
    END
  END rec[407]
  PIN rec[408]
    DIRECTION INPUT ;
    USE SIGNAL ;
    PORT
      LAYER M5 ;
        RECT  67.2 0 67.224 0.084 ;
    END
  END rec[408]
  PIN rec[409]
    DIRECTION INPUT ;
    USE SIGNAL ;
    PORT
      LAYER M5 ;
        RECT  67.248 0 67.272 0.084 ;
    END
  END rec[409]
  PIN rec[40]
    DIRECTION INPUT ;
    USE SIGNAL ;
    PORT
      LAYER M5 ;
        RECT  1.152 0 1.176 0.084 ;
    END
  END rec[40]
  PIN rec[410]
    DIRECTION INPUT ;
    USE SIGNAL ;
    PORT
      LAYER M5 ;
        RECT  67.296 0 67.32 0.084 ;
    END
  END rec[410]
  PIN rec[411]
    DIRECTION INPUT ;
    USE SIGNAL ;
    PORT
      LAYER M5 ;
        RECT  67.344 0 67.368 0.084 ;
    END
  END rec[411]
  PIN rec[412]
    DIRECTION INPUT ;
    USE SIGNAL ;
    PORT
      LAYER M5 ;
        RECT  67.392 0 67.416 0.084 ;
    END
  END rec[412]
  PIN rec[413]
    DIRECTION INPUT ;
    USE SIGNAL ;
    PORT
      LAYER M5 ;
        RECT  67.44 0 67.464 0.084 ;
    END
  END rec[413]
  PIN rec[414]
    DIRECTION INPUT ;
    USE SIGNAL ;
    PORT
      LAYER M5 ;
        RECT  67.488 0 67.512 0.084 ;
    END
  END rec[414]
  PIN rec[415]
    DIRECTION INPUT ;
    USE SIGNAL ;
    PORT
      LAYER M5 ;
        RECT  61.392 0 61.416 0.084 ;
    END
  END rec[415]
  PIN rec[416]
    DIRECTION INPUT ;
    USE SIGNAL ;
    PORT
      LAYER M5 ;
        RECT  61.44 0 61.464 0.084 ;
    END
  END rec[416]
  PIN rec[417]
    DIRECTION INPUT ;
    USE SIGNAL ;
    PORT
      LAYER M5 ;
        RECT  61.488 0 61.512 0.084 ;
    END
  END rec[417]
  PIN rec[418]
    DIRECTION INPUT ;
    USE SIGNAL ;
    PORT
      LAYER M5 ;
        RECT  61.536 0 61.56 0.084 ;
    END
  END rec[418]
  PIN rec[419]
    DIRECTION INPUT ;
    USE SIGNAL ;
    PORT
      LAYER M5 ;
        RECT  61.584 0 61.608 0.084 ;
    END
  END rec[419]
  PIN rec[41]
    DIRECTION INPUT ;
    USE SIGNAL ;
    PORT
      LAYER M5 ;
        RECT  1.2 0 1.224 0.084 ;
    END
  END rec[41]
  PIN rec[420]
    DIRECTION INPUT ;
    USE SIGNAL ;
    PORT
      LAYER M5 ;
        RECT  61.632 0 61.656 0.084 ;
    END
  END rec[420]
  PIN rec[421]
    DIRECTION INPUT ;
    USE SIGNAL ;
    PORT
      LAYER M5 ;
        RECT  61.68 0 61.704 0.084 ;
    END
  END rec[421]
  PIN rec[422]
    DIRECTION INPUT ;
    USE SIGNAL ;
    PORT
      LAYER M5 ;
        RECT  61.728 0 61.752 0.084 ;
    END
  END rec[422]
  PIN rec[423]
    DIRECTION INPUT ;
    USE SIGNAL ;
    PORT
      LAYER M5 ;
        RECT  61.776 0 61.8 0.084 ;
    END
  END rec[423]
  PIN rec[424]
    DIRECTION INPUT ;
    USE SIGNAL ;
    PORT
      LAYER M5 ;
        RECT  61.824 0 61.848 0.084 ;
    END
  END rec[424]
  PIN rec[425]
    DIRECTION INPUT ;
    USE SIGNAL ;
    PORT
      LAYER M5 ;
        RECT  61.872 0 61.896 0.084 ;
    END
  END rec[425]
  PIN rec[426]
    DIRECTION INPUT ;
    USE SIGNAL ;
    PORT
      LAYER M5 ;
        RECT  61.92 0 61.944 0.084 ;
    END
  END rec[426]
  PIN rec[427]
    DIRECTION INPUT ;
    USE SIGNAL ;
    PORT
      LAYER M5 ;
        RECT  61.968 0 61.992 0.084 ;
    END
  END rec[427]
  PIN rec[428]
    DIRECTION INPUT ;
    USE SIGNAL ;
    PORT
      LAYER M5 ;
        RECT  62.016 0 62.04 0.084 ;
    END
  END rec[428]
  PIN rec[429]
    DIRECTION INPUT ;
    USE SIGNAL ;
    PORT
      LAYER M5 ;
        RECT  62.064 0 62.088 0.084 ;
    END
  END rec[429]
  PIN rec[42]
    DIRECTION INPUT ;
    USE SIGNAL ;
    PORT
      LAYER M5 ;
        RECT  1.248 0 1.272 0.084 ;
    END
  END rec[42]
  PIN rec[430]
    DIRECTION INPUT ;
    USE SIGNAL ;
    PORT
      LAYER M5 ;
        RECT  62.112 0 62.136 0.084 ;
    END
  END rec[430]
  PIN rec[431]
    DIRECTION INPUT ;
    USE SIGNAL ;
    PORT
      LAYER M5 ;
        RECT  62.16 0 62.184 0.084 ;
    END
  END rec[431]
  PIN rec[432]
    DIRECTION INPUT ;
    USE SIGNAL ;
    PORT
      LAYER M5 ;
        RECT  62.208 0 62.232 0.084 ;
    END
  END rec[432]
  PIN rec[433]
    DIRECTION INPUT ;
    USE SIGNAL ;
    PORT
      LAYER M5 ;
        RECT  62.256 0 62.28 0.084 ;
    END
  END rec[433]
  PIN rec[434]
    DIRECTION INPUT ;
    USE SIGNAL ;
    PORT
      LAYER M5 ;
        RECT  62.304 0 62.328 0.084 ;
    END
  END rec[434]
  PIN rec[435]
    DIRECTION INPUT ;
    USE SIGNAL ;
    PORT
      LAYER M5 ;
        RECT  62.352 0 62.376 0.084 ;
    END
  END rec[435]
  PIN rec[436]
    DIRECTION INPUT ;
    USE SIGNAL ;
    PORT
      LAYER M5 ;
        RECT  62.4 0 62.424 0.084 ;
    END
  END rec[436]
  PIN rec[437]
    DIRECTION INPUT ;
    USE SIGNAL ;
    PORT
      LAYER M5 ;
        RECT  62.448 0 62.472 0.084 ;
    END
  END rec[437]
  PIN rec[438]
    DIRECTION INPUT ;
    USE SIGNAL ;
    PORT
      LAYER M5 ;
        RECT  62.496 0 62.52 0.084 ;
    END
  END rec[438]
  PIN rec[439]
    DIRECTION INPUT ;
    USE SIGNAL ;
    PORT
      LAYER M5 ;
        RECT  62.544 0 62.568 0.084 ;
    END
  END rec[439]
  PIN rec[43]
    DIRECTION INPUT ;
    USE SIGNAL ;
    PORT
      LAYER M5 ;
        RECT  1.296 0 1.32 0.084 ;
    END
  END rec[43]
  PIN rec[440]
    DIRECTION INPUT ;
    USE SIGNAL ;
    PORT
      LAYER M5 ;
        RECT  62.592 0 62.616 0.084 ;
    END
  END rec[440]
  PIN rec[441]
    DIRECTION INPUT ;
    USE SIGNAL ;
    PORT
      LAYER M5 ;
        RECT  62.64 0 62.664 0.084 ;
    END
  END rec[441]
  PIN rec[442]
    DIRECTION INPUT ;
    USE SIGNAL ;
    PORT
      LAYER M5 ;
        RECT  62.688 0 62.712 0.084 ;
    END
  END rec[442]
  PIN rec[443]
    DIRECTION INPUT ;
    USE SIGNAL ;
    PORT
      LAYER M5 ;
        RECT  62.736 0 62.76 0.084 ;
    END
  END rec[443]
  PIN rec[444]
    DIRECTION INPUT ;
    USE SIGNAL ;
    PORT
      LAYER M5 ;
        RECT  62.784 0 62.808 0.084 ;
    END
  END rec[444]
  PIN rec[445]
    DIRECTION INPUT ;
    USE SIGNAL ;
    PORT
      LAYER M5 ;
        RECT  62.832 0 62.856 0.084 ;
    END
  END rec[445]
  PIN rec[446]
    DIRECTION INPUT ;
    USE SIGNAL ;
    PORT
      LAYER M5 ;
        RECT  62.88 0 62.904 0.084 ;
    END
  END rec[446]
  PIN rec[447]
    DIRECTION INPUT ;
    USE SIGNAL ;
    PORT
      LAYER M5 ;
        RECT  50.256 0 50.28 0.084 ;
    END
  END rec[447]
  PIN rec[448]
    DIRECTION INPUT ;
    USE SIGNAL ;
    PORT
      LAYER M5 ;
        RECT  50.304 0 50.328 0.084 ;
    END
  END rec[448]
  PIN rec[449]
    DIRECTION INPUT ;
    USE SIGNAL ;
    PORT
      LAYER M5 ;
        RECT  50.352 0 50.376 0.084 ;
    END
  END rec[449]
  PIN rec[44]
    DIRECTION INPUT ;
    USE SIGNAL ;
    PORT
      LAYER M5 ;
        RECT  1.344 0 1.368 0.084 ;
    END
  END rec[44]
  PIN rec[450]
    DIRECTION INPUT ;
    USE SIGNAL ;
    PORT
      LAYER M5 ;
        RECT  50.4 0 50.424 0.084 ;
    END
  END rec[450]
  PIN rec[451]
    DIRECTION INPUT ;
    USE SIGNAL ;
    PORT
      LAYER M5 ;
        RECT  50.448 0 50.472 0.084 ;
    END
  END rec[451]
  PIN rec[452]
    DIRECTION INPUT ;
    USE SIGNAL ;
    PORT
      LAYER M5 ;
        RECT  50.496 0 50.52 0.084 ;
    END
  END rec[452]
  PIN rec[453]
    DIRECTION INPUT ;
    USE SIGNAL ;
    PORT
      LAYER M5 ;
        RECT  50.544 0 50.568 0.084 ;
    END
  END rec[453]
  PIN rec[454]
    DIRECTION INPUT ;
    USE SIGNAL ;
    PORT
      LAYER M5 ;
        RECT  50.592 0 50.616 0.084 ;
    END
  END rec[454]
  PIN rec[455]
    DIRECTION INPUT ;
    USE SIGNAL ;
    PORT
      LAYER M5 ;
        RECT  50.64 0 50.664 0.084 ;
    END
  END rec[455]
  PIN rec[456]
    DIRECTION INPUT ;
    USE SIGNAL ;
    PORT
      LAYER M5 ;
        RECT  50.688 0 50.712 0.084 ;
    END
  END rec[456]
  PIN rec[457]
    DIRECTION INPUT ;
    USE SIGNAL ;
    PORT
      LAYER M5 ;
        RECT  50.736 0 50.76 0.084 ;
    END
  END rec[457]
  PIN rec[458]
    DIRECTION INPUT ;
    USE SIGNAL ;
    PORT
      LAYER M5 ;
        RECT  50.784 0 50.808 0.084 ;
    END
  END rec[458]
  PIN rec[459]
    DIRECTION INPUT ;
    USE SIGNAL ;
    PORT
      LAYER M5 ;
        RECT  50.832 0 50.856 0.084 ;
    END
  END rec[459]
  PIN rec[45]
    DIRECTION INPUT ;
    USE SIGNAL ;
    PORT
      LAYER M5 ;
        RECT  1.392 0 1.416 0.084 ;
    END
  END rec[45]
  PIN rec[460]
    DIRECTION INPUT ;
    USE SIGNAL ;
    PORT
      LAYER M5 ;
        RECT  50.88 0 50.904 0.084 ;
    END
  END rec[460]
  PIN rec[461]
    DIRECTION INPUT ;
    USE SIGNAL ;
    PORT
      LAYER M5 ;
        RECT  50.928 0 50.952 0.084 ;
    END
  END rec[461]
  PIN rec[462]
    DIRECTION INPUT ;
    USE SIGNAL ;
    PORT
      LAYER M5 ;
        RECT  50.976 0 51 0.084 ;
    END
  END rec[462]
  PIN rec[463]
    DIRECTION INPUT ;
    USE SIGNAL ;
    PORT
      LAYER M5 ;
        RECT  51.024 0 51.048 0.084 ;
    END
  END rec[463]
  PIN rec[464]
    DIRECTION INPUT ;
    USE SIGNAL ;
    PORT
      LAYER M5 ;
        RECT  51.072 0 51.096 0.084 ;
    END
  END rec[464]
  PIN rec[465]
    DIRECTION INPUT ;
    USE SIGNAL ;
    PORT
      LAYER M5 ;
        RECT  51.12 0 51.144 0.084 ;
    END
  END rec[465]
  PIN rec[466]
    DIRECTION INPUT ;
    USE SIGNAL ;
    PORT
      LAYER M5 ;
        RECT  51.168 0 51.192 0.084 ;
    END
  END rec[466]
  PIN rec[467]
    DIRECTION INPUT ;
    USE SIGNAL ;
    PORT
      LAYER M5 ;
        RECT  51.216 0 51.24 0.084 ;
    END
  END rec[467]
  PIN rec[468]
    DIRECTION INPUT ;
    USE SIGNAL ;
    PORT
      LAYER M5 ;
        RECT  51.264 0 51.288 0.084 ;
    END
  END rec[468]
  PIN rec[469]
    DIRECTION INPUT ;
    USE SIGNAL ;
    PORT
      LAYER M5 ;
        RECT  51.312 0 51.336 0.084 ;
    END
  END rec[469]
  PIN rec[46]
    DIRECTION INPUT ;
    USE SIGNAL ;
    PORT
      LAYER M5 ;
        RECT  1.44 0 1.464 0.084 ;
    END
  END rec[46]
  PIN rec[470]
    DIRECTION INPUT ;
    USE SIGNAL ;
    PORT
      LAYER M5 ;
        RECT  51.36 0 51.384 0.084 ;
    END
  END rec[470]
  PIN rec[471]
    DIRECTION INPUT ;
    USE SIGNAL ;
    PORT
      LAYER M5 ;
        RECT  51.408 0 51.432 0.084 ;
    END
  END rec[471]
  PIN rec[472]
    DIRECTION INPUT ;
    USE SIGNAL ;
    PORT
      LAYER M5 ;
        RECT  51.456 0 51.48 0.084 ;
    END
  END rec[472]
  PIN rec[473]
    DIRECTION INPUT ;
    USE SIGNAL ;
    PORT
      LAYER M5 ;
        RECT  51.504 0 51.528 0.084 ;
    END
  END rec[473]
  PIN rec[474]
    DIRECTION INPUT ;
    USE SIGNAL ;
    PORT
      LAYER M5 ;
        RECT  51.552 0 51.576 0.084 ;
    END
  END rec[474]
  PIN rec[475]
    DIRECTION INPUT ;
    USE SIGNAL ;
    PORT
      LAYER M5 ;
        RECT  51.6 0 51.624 0.084 ;
    END
  END rec[475]
  PIN rec[476]
    DIRECTION INPUT ;
    USE SIGNAL ;
    PORT
      LAYER M5 ;
        RECT  51.648 0 51.672 0.084 ;
    END
  END rec[476]
  PIN rec[477]
    DIRECTION INPUT ;
    USE SIGNAL ;
    PORT
      LAYER M5 ;
        RECT  51.696 0 51.72 0.084 ;
    END
  END rec[477]
  PIN rec[478]
    DIRECTION INPUT ;
    USE SIGNAL ;
    PORT
      LAYER M5 ;
        RECT  51.744 0 51.768 0.084 ;
    END
  END rec[478]
  PIN rec[479]
    DIRECTION INPUT ;
    USE SIGNAL ;
    PORT
      LAYER M5 ;
        RECT  75.6 0 75.624 0.084 ;
    END
  END rec[479]
  PIN rec[47]
    DIRECTION INPUT ;
    USE SIGNAL ;
    PORT
      LAYER M5 ;
        RECT  1.488 0 1.512 0.084 ;
    END
  END rec[47]
  PIN rec[480]
    DIRECTION INPUT ;
    USE SIGNAL ;
    PORT
      LAYER M5 ;
        RECT  75.648 0 75.672 0.084 ;
    END
  END rec[480]
  PIN rec[481]
    DIRECTION INPUT ;
    USE SIGNAL ;
    PORT
      LAYER M5 ;
        RECT  75.696 0 75.72 0.084 ;
    END
  END rec[481]
  PIN rec[482]
    DIRECTION INPUT ;
    USE SIGNAL ;
    PORT
      LAYER M5 ;
        RECT  75.744 0 75.768 0.084 ;
    END
  END rec[482]
  PIN rec[483]
    DIRECTION INPUT ;
    USE SIGNAL ;
    PORT
      LAYER M5 ;
        RECT  75.792 0 75.816 0.084 ;
    END
  END rec[483]
  PIN rec[484]
    DIRECTION INPUT ;
    USE SIGNAL ;
    PORT
      LAYER M5 ;
        RECT  75.84 0 75.864 0.084 ;
    END
  END rec[484]
  PIN rec[485]
    DIRECTION INPUT ;
    USE SIGNAL ;
    PORT
      LAYER M5 ;
        RECT  75.888 0 75.912 0.084 ;
    END
  END rec[485]
  PIN rec[486]
    DIRECTION INPUT ;
    USE SIGNAL ;
    PORT
      LAYER M5 ;
        RECT  75.936 0 75.96 0.084 ;
    END
  END rec[486]
  PIN rec[487]
    DIRECTION INPUT ;
    USE SIGNAL ;
    PORT
      LAYER M5 ;
        RECT  75.984 0 76.008 0.084 ;
    END
  END rec[487]
  PIN rec[488]
    DIRECTION INPUT ;
    USE SIGNAL ;
    PORT
      LAYER M5 ;
        RECT  76.032 0 76.056 0.084 ;
    END
  END rec[488]
  PIN rec[489]
    DIRECTION INPUT ;
    USE SIGNAL ;
    PORT
      LAYER M5 ;
        RECT  76.08 0 76.104 0.084 ;
    END
  END rec[489]
  PIN rec[48]
    DIRECTION INPUT ;
    USE SIGNAL ;
    PORT
      LAYER M5 ;
        RECT  1.536 0 1.56 0.084 ;
    END
  END rec[48]
  PIN rec[490]
    DIRECTION INPUT ;
    USE SIGNAL ;
    PORT
      LAYER M5 ;
        RECT  76.128 0 76.152 0.084 ;
    END
  END rec[490]
  PIN rec[491]
    DIRECTION INPUT ;
    USE SIGNAL ;
    PORT
      LAYER M5 ;
        RECT  76.176 0 76.2 0.084 ;
    END
  END rec[491]
  PIN rec[492]
    DIRECTION INPUT ;
    USE SIGNAL ;
    PORT
      LAYER M5 ;
        RECT  76.224 0 76.248 0.084 ;
    END
  END rec[492]
  PIN rec[493]
    DIRECTION INPUT ;
    USE SIGNAL ;
    PORT
      LAYER M5 ;
        RECT  76.272 0 76.296 0.084 ;
    END
  END rec[493]
  PIN rec[494]
    DIRECTION INPUT ;
    USE SIGNAL ;
    PORT
      LAYER M5 ;
        RECT  76.32 0 76.344 0.084 ;
    END
  END rec[494]
  PIN rec[495]
    DIRECTION INPUT ;
    USE SIGNAL ;
    PORT
      LAYER M5 ;
        RECT  76.368 0 76.392 0.084 ;
    END
  END rec[495]
  PIN rec[496]
    DIRECTION INPUT ;
    USE SIGNAL ;
    PORT
      LAYER M5 ;
        RECT  76.416 0 76.44 0.084 ;
    END
  END rec[496]
  PIN rec[497]
    DIRECTION INPUT ;
    USE SIGNAL ;
    PORT
      LAYER M5 ;
        RECT  76.464 0 76.488 0.084 ;
    END
  END rec[497]
  PIN rec[498]
    DIRECTION INPUT ;
    USE SIGNAL ;
    PORT
      LAYER M5 ;
        RECT  76.512 0 76.536 0.084 ;
    END
  END rec[498]
  PIN rec[499]
    DIRECTION INPUT ;
    USE SIGNAL ;
    PORT
      LAYER M5 ;
        RECT  76.56 0 76.584 0.084 ;
    END
  END rec[499]
  PIN rec[49]
    DIRECTION INPUT ;
    USE SIGNAL ;
    PORT
      LAYER M5 ;
        RECT  1.584 0 1.608 0.084 ;
    END
  END rec[49]
  PIN rec[4]
    DIRECTION INPUT ;
    USE SIGNAL ;
    PORT
      LAYER M5 ;
        RECT  40.896 0 40.92 0.084 ;
    END
  END rec[4]
  PIN rec[500]
    DIRECTION INPUT ;
    USE SIGNAL ;
    PORT
      LAYER M5 ;
        RECT  76.608 0 76.632 0.084 ;
    END
  END rec[500]
  PIN rec[501]
    DIRECTION INPUT ;
    USE SIGNAL ;
    PORT
      LAYER M5 ;
        RECT  76.656 0 76.68 0.084 ;
    END
  END rec[501]
  PIN rec[502]
    DIRECTION INPUT ;
    USE SIGNAL ;
    PORT
      LAYER M5 ;
        RECT  76.704 0 76.728 0.084 ;
    END
  END rec[502]
  PIN rec[503]
    DIRECTION INPUT ;
    USE SIGNAL ;
    PORT
      LAYER M5 ;
        RECT  76.752 0 76.776 0.084 ;
    END
  END rec[503]
  PIN rec[504]
    DIRECTION INPUT ;
    USE SIGNAL ;
    PORT
      LAYER M5 ;
        RECT  76.8 0 76.824 0.084 ;
    END
  END rec[504]
  PIN rec[505]
    DIRECTION INPUT ;
    USE SIGNAL ;
    PORT
      LAYER M5 ;
        RECT  76.848 0 76.872 0.084 ;
    END
  END rec[505]
  PIN rec[506]
    DIRECTION INPUT ;
    USE SIGNAL ;
    PORT
      LAYER M5 ;
        RECT  76.896 0 76.92 0.084 ;
    END
  END rec[506]
  PIN rec[507]
    DIRECTION INPUT ;
    USE SIGNAL ;
    PORT
      LAYER M5 ;
        RECT  76.944 0 76.968 0.084 ;
    END
  END rec[507]
  PIN rec[508]
    DIRECTION INPUT ;
    USE SIGNAL ;
    PORT
      LAYER M5 ;
        RECT  76.992 0 77.016 0.084 ;
    END
  END rec[508]
  PIN rec[509]
    DIRECTION INPUT ;
    USE SIGNAL ;
    PORT
      LAYER M5 ;
        RECT  77.04 0 77.064 0.084 ;
    END
  END rec[509]
  PIN rec[50]
    DIRECTION INPUT ;
    USE SIGNAL ;
    PORT
      LAYER M5 ;
        RECT  1.632 0 1.656 0.084 ;
    END
  END rec[50]
  PIN rec[510]
    DIRECTION INPUT ;
    USE SIGNAL ;
    PORT
      LAYER M5 ;
        RECT  77.088 0 77.112 0.084 ;
    END
  END rec[510]
  PIN rec[511]
    DIRECTION INPUT ;
    USE SIGNAL ;
    PORT
      LAYER M5 ;
        RECT  48.72 0 48.744 0.084 ;
    END
  END rec[511]
  PIN rec[512]
    DIRECTION INPUT ;
    USE SIGNAL ;
    PORT
      LAYER M5 ;
        RECT  48.768 0 48.792 0.084 ;
    END
  END rec[512]
  PIN rec[513]
    DIRECTION INPUT ;
    USE SIGNAL ;
    PORT
      LAYER M5 ;
        RECT  48.816 0 48.84 0.084 ;
    END
  END rec[513]
  PIN rec[514]
    DIRECTION INPUT ;
    USE SIGNAL ;
    PORT
      LAYER M5 ;
        RECT  48.864 0 48.888 0.084 ;
    END
  END rec[514]
  PIN rec[515]
    DIRECTION INPUT ;
    USE SIGNAL ;
    PORT
      LAYER M5 ;
        RECT  48.912 0 48.936 0.084 ;
    END
  END rec[515]
  PIN rec[516]
    DIRECTION INPUT ;
    USE SIGNAL ;
    PORT
      LAYER M5 ;
        RECT  48.96 0 48.984 0.084 ;
    END
  END rec[516]
  PIN rec[517]
    DIRECTION INPUT ;
    USE SIGNAL ;
    PORT
      LAYER M5 ;
        RECT  49.008 0 49.032 0.084 ;
    END
  END rec[517]
  PIN rec[518]
    DIRECTION INPUT ;
    USE SIGNAL ;
    PORT
      LAYER M5 ;
        RECT  49.056 0 49.08 0.084 ;
    END
  END rec[518]
  PIN rec[519]
    DIRECTION INPUT ;
    USE SIGNAL ;
    PORT
      LAYER M5 ;
        RECT  49.104 0 49.128 0.084 ;
    END
  END rec[519]
  PIN rec[51]
    DIRECTION INPUT ;
    USE SIGNAL ;
    PORT
      LAYER M5 ;
        RECT  1.68 0 1.704 0.084 ;
    END
  END rec[51]
  PIN rec[520]
    DIRECTION INPUT ;
    USE SIGNAL ;
    PORT
      LAYER M5 ;
        RECT  49.152 0 49.176 0.084 ;
    END
  END rec[520]
  PIN rec[521]
    DIRECTION INPUT ;
    USE SIGNAL ;
    PORT
      LAYER M5 ;
        RECT  49.2 0 49.224 0.084 ;
    END
  END rec[521]
  PIN rec[522]
    DIRECTION INPUT ;
    USE SIGNAL ;
    PORT
      LAYER M5 ;
        RECT  49.248 0 49.272 0.084 ;
    END
  END rec[522]
  PIN rec[523]
    DIRECTION INPUT ;
    USE SIGNAL ;
    PORT
      LAYER M5 ;
        RECT  49.296 0 49.32 0.084 ;
    END
  END rec[523]
  PIN rec[524]
    DIRECTION INPUT ;
    USE SIGNAL ;
    PORT
      LAYER M5 ;
        RECT  49.344 0 49.368 0.084 ;
    END
  END rec[524]
  PIN rec[525]
    DIRECTION INPUT ;
    USE SIGNAL ;
    PORT
      LAYER M5 ;
        RECT  49.392 0 49.416 0.084 ;
    END
  END rec[525]
  PIN rec[526]
    DIRECTION INPUT ;
    USE SIGNAL ;
    PORT
      LAYER M5 ;
        RECT  49.44 0 49.464 0.084 ;
    END
  END rec[526]
  PIN rec[527]
    DIRECTION INPUT ;
    USE SIGNAL ;
    PORT
      LAYER M5 ;
        RECT  49.488 0 49.512 0.084 ;
    END
  END rec[527]
  PIN rec[528]
    DIRECTION INPUT ;
    USE SIGNAL ;
    PORT
      LAYER M5 ;
        RECT  49.536 0 49.56 0.084 ;
    END
  END rec[528]
  PIN rec[529]
    DIRECTION INPUT ;
    USE SIGNAL ;
    PORT
      LAYER M5 ;
        RECT  49.584 0 49.608 0.084 ;
    END
  END rec[529]
  PIN rec[52]
    DIRECTION INPUT ;
    USE SIGNAL ;
    PORT
      LAYER M5 ;
        RECT  1.728 0 1.752 0.084 ;
    END
  END rec[52]
  PIN rec[530]
    DIRECTION INPUT ;
    USE SIGNAL ;
    PORT
      LAYER M5 ;
        RECT  49.632 0 49.656 0.084 ;
    END
  END rec[530]
  PIN rec[531]
    DIRECTION INPUT ;
    USE SIGNAL ;
    PORT
      LAYER M5 ;
        RECT  49.68 0 49.704 0.084 ;
    END
  END rec[531]
  PIN rec[532]
    DIRECTION INPUT ;
    USE SIGNAL ;
    PORT
      LAYER M5 ;
        RECT  49.728 0 49.752 0.084 ;
    END
  END rec[532]
  PIN rec[533]
    DIRECTION INPUT ;
    USE SIGNAL ;
    PORT
      LAYER M5 ;
        RECT  49.776 0 49.8 0.084 ;
    END
  END rec[533]
  PIN rec[534]
    DIRECTION INPUT ;
    USE SIGNAL ;
    PORT
      LAYER M5 ;
        RECT  49.824 0 49.848 0.084 ;
    END
  END rec[534]
  PIN rec[535]
    DIRECTION INPUT ;
    USE SIGNAL ;
    PORT
      LAYER M5 ;
        RECT  49.872 0 49.896 0.084 ;
    END
  END rec[535]
  PIN rec[536]
    DIRECTION INPUT ;
    USE SIGNAL ;
    PORT
      LAYER M5 ;
        RECT  49.92 0 49.944 0.084 ;
    END
  END rec[536]
  PIN rec[537]
    DIRECTION INPUT ;
    USE SIGNAL ;
    PORT
      LAYER M5 ;
        RECT  49.968 0 49.992 0.084 ;
    END
  END rec[537]
  PIN rec[538]
    DIRECTION INPUT ;
    USE SIGNAL ;
    PORT
      LAYER M5 ;
        RECT  50.016 0 50.04 0.084 ;
    END
  END rec[538]
  PIN rec[539]
    DIRECTION INPUT ;
    USE SIGNAL ;
    PORT
      LAYER M5 ;
        RECT  50.064 0 50.088 0.084 ;
    END
  END rec[539]
  PIN rec[53]
    DIRECTION INPUT ;
    USE SIGNAL ;
    PORT
      LAYER M5 ;
        RECT  1.776 0 1.8 0.084 ;
    END
  END rec[53]
  PIN rec[540]
    DIRECTION INPUT ;
    USE SIGNAL ;
    PORT
      LAYER M5 ;
        RECT  50.112 0 50.136 0.084 ;
    END
  END rec[540]
  PIN rec[541]
    DIRECTION INPUT ;
    USE SIGNAL ;
    PORT
      LAYER M5 ;
        RECT  50.16 0 50.184 0.084 ;
    END
  END rec[541]
  PIN rec[542]
    DIRECTION INPUT ;
    USE SIGNAL ;
    PORT
      LAYER M5 ;
        RECT  50.208 0 50.232 0.084 ;
    END
  END rec[542]
  PIN rec[543]
    DIRECTION INPUT ;
    USE SIGNAL ;
    PORT
      LAYER M5 ;
        RECT  77.52 0 77.544 0.084 ;
    END
  END rec[543]
  PIN rec[544]
    DIRECTION INPUT ;
    USE SIGNAL ;
    PORT
      LAYER M5 ;
        RECT  77.568 0 77.592 0.084 ;
    END
  END rec[544]
  PIN rec[545]
    DIRECTION INPUT ;
    USE SIGNAL ;
    PORT
      LAYER M5 ;
        RECT  77.616 0 77.64 0.084 ;
    END
  END rec[545]
  PIN rec[546]
    DIRECTION INPUT ;
    USE SIGNAL ;
    PORT
      LAYER M5 ;
        RECT  77.664 0 77.688 0.084 ;
    END
  END rec[546]
  PIN rec[547]
    DIRECTION INPUT ;
    USE SIGNAL ;
    PORT
      LAYER M5 ;
        RECT  77.712 0 77.736 0.084 ;
    END
  END rec[547]
  PIN rec[548]
    DIRECTION INPUT ;
    USE SIGNAL ;
    PORT
      LAYER M5 ;
        RECT  77.76 0 77.784 0.084 ;
    END
  END rec[548]
  PIN rec[549]
    DIRECTION INPUT ;
    USE SIGNAL ;
    PORT
      LAYER M5 ;
        RECT  77.808 0 77.832 0.084 ;
    END
  END rec[549]
  PIN rec[54]
    DIRECTION INPUT ;
    USE SIGNAL ;
    PORT
      LAYER M5 ;
        RECT  1.824 0 1.848 0.084 ;
    END
  END rec[54]
  PIN rec[550]
    DIRECTION INPUT ;
    USE SIGNAL ;
    PORT
      LAYER M5 ;
        RECT  77.856 0 77.88 0.084 ;
    END
  END rec[550]
  PIN rec[551]
    DIRECTION INPUT ;
    USE SIGNAL ;
    PORT
      LAYER M5 ;
        RECT  77.904 0 77.928 0.084 ;
    END
  END rec[551]
  PIN rec[552]
    DIRECTION INPUT ;
    USE SIGNAL ;
    PORT
      LAYER M5 ;
        RECT  77.952 0 77.976 0.084 ;
    END
  END rec[552]
  PIN rec[553]
    DIRECTION INPUT ;
    USE SIGNAL ;
    PORT
      LAYER M5 ;
        RECT  78 0 78.024 0.084 ;
    END
  END rec[553]
  PIN rec[554]
    DIRECTION INPUT ;
    USE SIGNAL ;
    PORT
      LAYER M5 ;
        RECT  78.048 0 78.072 0.084 ;
    END
  END rec[554]
  PIN rec[555]
    DIRECTION INPUT ;
    USE SIGNAL ;
    PORT
      LAYER M5 ;
        RECT  78.096 0 78.12 0.084 ;
    END
  END rec[555]
  PIN rec[556]
    DIRECTION INPUT ;
    USE SIGNAL ;
    PORT
      LAYER M5 ;
        RECT  78.144 0 78.168 0.084 ;
    END
  END rec[556]
  PIN rec[557]
    DIRECTION INPUT ;
    USE SIGNAL ;
    PORT
      LAYER M5 ;
        RECT  78.192 0 78.216 0.084 ;
    END
  END rec[557]
  PIN rec[558]
    DIRECTION INPUT ;
    USE SIGNAL ;
    PORT
      LAYER M5 ;
        RECT  78.24 0 78.264 0.084 ;
    END
  END rec[558]
  PIN rec[559]
    DIRECTION INPUT ;
    USE SIGNAL ;
    PORT
      LAYER M5 ;
        RECT  78.288 0 78.312 0.084 ;
    END
  END rec[559]
  PIN rec[55]
    DIRECTION INPUT ;
    USE SIGNAL ;
    PORT
      LAYER M5 ;
        RECT  1.872 0 1.896 0.084 ;
    END
  END rec[55]
  PIN rec[560]
    DIRECTION INPUT ;
    USE SIGNAL ;
    PORT
      LAYER M5 ;
        RECT  78.336 0 78.36 0.084 ;
    END
  END rec[560]
  PIN rec[561]
    DIRECTION INPUT ;
    USE SIGNAL ;
    PORT
      LAYER M5 ;
        RECT  78.384 0 78.408 0.084 ;
    END
  END rec[561]
  PIN rec[562]
    DIRECTION INPUT ;
    USE SIGNAL ;
    PORT
      LAYER M5 ;
        RECT  78.432 0 78.456 0.084 ;
    END
  END rec[562]
  PIN rec[563]
    DIRECTION INPUT ;
    USE SIGNAL ;
    PORT
      LAYER M5 ;
        RECT  78.48 0 78.504 0.084 ;
    END
  END rec[563]
  PIN rec[564]
    DIRECTION INPUT ;
    USE SIGNAL ;
    PORT
      LAYER M5 ;
        RECT  78.528 0 78.552 0.084 ;
    END
  END rec[564]
  PIN rec[565]
    DIRECTION INPUT ;
    USE SIGNAL ;
    PORT
      LAYER M5 ;
        RECT  78.576 0 78.6 0.084 ;
    END
  END rec[565]
  PIN rec[566]
    DIRECTION INPUT ;
    USE SIGNAL ;
    PORT
      LAYER M5 ;
        RECT  78.624 0 78.648 0.084 ;
    END
  END rec[566]
  PIN rec[567]
    DIRECTION INPUT ;
    USE SIGNAL ;
    PORT
      LAYER M5 ;
        RECT  78.672 0 78.696 0.084 ;
    END
  END rec[567]
  PIN rec[568]
    DIRECTION INPUT ;
    USE SIGNAL ;
    PORT
      LAYER M5 ;
        RECT  78.72 0 78.744 0.084 ;
    END
  END rec[568]
  PIN rec[569]
    DIRECTION INPUT ;
    USE SIGNAL ;
    PORT
      LAYER M5 ;
        RECT  78.768 0 78.792 0.084 ;
    END
  END rec[569]
  PIN rec[56]
    DIRECTION INPUT ;
    USE SIGNAL ;
    PORT
      LAYER M5 ;
        RECT  1.92 0 1.944 0.084 ;
    END
  END rec[56]
  PIN rec[570]
    DIRECTION INPUT ;
    USE SIGNAL ;
    PORT
      LAYER M5 ;
        RECT  78.816 0 78.84 0.084 ;
    END
  END rec[570]
  PIN rec[571]
    DIRECTION INPUT ;
    USE SIGNAL ;
    PORT
      LAYER M5 ;
        RECT  78.864 0 78.888 0.084 ;
    END
  END rec[571]
  PIN rec[572]
    DIRECTION INPUT ;
    USE SIGNAL ;
    PORT
      LAYER M5 ;
        RECT  78.912 0 78.936 0.084 ;
    END
  END rec[572]
  PIN rec[573]
    DIRECTION INPUT ;
    USE SIGNAL ;
    PORT
      LAYER M5 ;
        RECT  78.96 0 78.984 0.084 ;
    END
  END rec[573]
  PIN rec[574]
    DIRECTION INPUT ;
    USE SIGNAL ;
    PORT
      LAYER M5 ;
        RECT  79.008 0 79.032 0.084 ;
    END
  END rec[574]
  PIN rec[575]
    DIRECTION INPUT ;
    USE SIGNAL ;
    PORT
      LAYER M5 ;
        RECT  87.12 0 87.144 0.084 ;
    END
  END rec[575]
  PIN rec[576]
    DIRECTION INPUT ;
    USE SIGNAL ;
    PORT
      LAYER M5 ;
        RECT  87.168 0 87.192 0.084 ;
    END
  END rec[576]
  PIN rec[577]
    DIRECTION INPUT ;
    USE SIGNAL ;
    PORT
      LAYER M5 ;
        RECT  87.216 0 87.24 0.084 ;
    END
  END rec[577]
  PIN rec[578]
    DIRECTION INPUT ;
    USE SIGNAL ;
    PORT
      LAYER M5 ;
        RECT  87.264 0 87.288 0.084 ;
    END
  END rec[578]
  PIN rec[579]
    DIRECTION INPUT ;
    USE SIGNAL ;
    PORT
      LAYER M5 ;
        RECT  87.312 0 87.336 0.084 ;
    END
  END rec[579]
  PIN rec[57]
    DIRECTION INPUT ;
    USE SIGNAL ;
    PORT
      LAYER M5 ;
        RECT  1.968 0 1.992 0.084 ;
    END
  END rec[57]
  PIN rec[580]
    DIRECTION INPUT ;
    USE SIGNAL ;
    PORT
      LAYER M5 ;
        RECT  87.36 0 87.384 0.084 ;
    END
  END rec[580]
  PIN rec[581]
    DIRECTION INPUT ;
    USE SIGNAL ;
    PORT
      LAYER M5 ;
        RECT  87.408 0 87.432 0.084 ;
    END
  END rec[581]
  PIN rec[582]
    DIRECTION INPUT ;
    USE SIGNAL ;
    PORT
      LAYER M5 ;
        RECT  87.456 0 87.48 0.084 ;
    END
  END rec[582]
  PIN rec[583]
    DIRECTION INPUT ;
    USE SIGNAL ;
    PORT
      LAYER M5 ;
        RECT  87.504 0 87.528 0.084 ;
    END
  END rec[583]
  PIN rec[584]
    DIRECTION INPUT ;
    USE SIGNAL ;
    PORT
      LAYER M5 ;
        RECT  87.552 0 87.576 0.084 ;
    END
  END rec[584]
  PIN rec[585]
    DIRECTION INPUT ;
    USE SIGNAL ;
    PORT
      LAYER M5 ;
        RECT  87.6 0 87.624 0.084 ;
    END
  END rec[585]
  PIN rec[586]
    DIRECTION INPUT ;
    USE SIGNAL ;
    PORT
      LAYER M5 ;
        RECT  87.648 0 87.672 0.084 ;
    END
  END rec[586]
  PIN rec[587]
    DIRECTION INPUT ;
    USE SIGNAL ;
    PORT
      LAYER M5 ;
        RECT  87.696 0 87.72 0.084 ;
    END
  END rec[587]
  PIN rec[588]
    DIRECTION INPUT ;
    USE SIGNAL ;
    PORT
      LAYER M5 ;
        RECT  87.744 0 87.768 0.084 ;
    END
  END rec[588]
  PIN rec[589]
    DIRECTION INPUT ;
    USE SIGNAL ;
    PORT
      LAYER M5 ;
        RECT  87.792 0 87.816 0.084 ;
    END
  END rec[589]
  PIN rec[58]
    DIRECTION INPUT ;
    USE SIGNAL ;
    PORT
      LAYER M5 ;
        RECT  2.016 0 2.04 0.084 ;
    END
  END rec[58]
  PIN rec[590]
    DIRECTION INPUT ;
    USE SIGNAL ;
    PORT
      LAYER M5 ;
        RECT  87.84 0 87.864 0.084 ;
    END
  END rec[590]
  PIN rec[591]
    DIRECTION INPUT ;
    USE SIGNAL ;
    PORT
      LAYER M5 ;
        RECT  87.888 0 87.912 0.084 ;
    END
  END rec[591]
  PIN rec[592]
    DIRECTION INPUT ;
    USE SIGNAL ;
    PORT
      LAYER M5 ;
        RECT  87.936 0 87.96 0.084 ;
    END
  END rec[592]
  PIN rec[593]
    DIRECTION INPUT ;
    USE SIGNAL ;
    PORT
      LAYER M5 ;
        RECT  87.984 0 88.008 0.084 ;
    END
  END rec[593]
  PIN rec[594]
    DIRECTION INPUT ;
    USE SIGNAL ;
    PORT
      LAYER M5 ;
        RECT  88.032 0 88.056 0.084 ;
    END
  END rec[594]
  PIN rec[595]
    DIRECTION INPUT ;
    USE SIGNAL ;
    PORT
      LAYER M5 ;
        RECT  88.08 0 88.104 0.084 ;
    END
  END rec[595]
  PIN rec[596]
    DIRECTION INPUT ;
    USE SIGNAL ;
    PORT
      LAYER M5 ;
        RECT  88.128 0 88.152 0.084 ;
    END
  END rec[596]
  PIN rec[597]
    DIRECTION INPUT ;
    USE SIGNAL ;
    PORT
      LAYER M5 ;
        RECT  88.176 0 88.2 0.084 ;
    END
  END rec[597]
  PIN rec[598]
    DIRECTION INPUT ;
    USE SIGNAL ;
    PORT
      LAYER M5 ;
        RECT  88.224 0 88.248 0.084 ;
    END
  END rec[598]
  PIN rec[599]
    DIRECTION INPUT ;
    USE SIGNAL ;
    PORT
      LAYER M5 ;
        RECT  88.272 0 88.296 0.084 ;
    END
  END rec[599]
  PIN rec[59]
    DIRECTION INPUT ;
    USE SIGNAL ;
    PORT
      LAYER M5 ;
        RECT  2.064 0 2.088 0.084 ;
    END
  END rec[59]
  PIN rec[5]
    DIRECTION INPUT ;
    USE SIGNAL ;
    PORT
      LAYER M5 ;
        RECT  40.944 0 40.968 0.084 ;
    END
  END rec[5]
  PIN rec[600]
    DIRECTION INPUT ;
    USE SIGNAL ;
    PORT
      LAYER M5 ;
        RECT  88.32 0 88.344 0.084 ;
    END
  END rec[600]
  PIN rec[601]
    DIRECTION INPUT ;
    USE SIGNAL ;
    PORT
      LAYER M5 ;
        RECT  88.368 0 88.392 0.084 ;
    END
  END rec[601]
  PIN rec[602]
    DIRECTION INPUT ;
    USE SIGNAL ;
    PORT
      LAYER M5 ;
        RECT  88.416 0 88.44 0.084 ;
    END
  END rec[602]
  PIN rec[603]
    DIRECTION INPUT ;
    USE SIGNAL ;
    PORT
      LAYER M5 ;
        RECT  88.464 0 88.488 0.084 ;
    END
  END rec[603]
  PIN rec[604]
    DIRECTION INPUT ;
    USE SIGNAL ;
    PORT
      LAYER M5 ;
        RECT  88.512 0 88.536 0.084 ;
    END
  END rec[604]
  PIN rec[605]
    DIRECTION INPUT ;
    USE SIGNAL ;
    PORT
      LAYER M5 ;
        RECT  88.56 0 88.584 0.084 ;
    END
  END rec[605]
  PIN rec[606]
    DIRECTION INPUT ;
    USE SIGNAL ;
    PORT
      LAYER M5 ;
        RECT  88.608 0 88.632 0.084 ;
    END
  END rec[606]
  PIN rec[607]
    DIRECTION INPUT ;
    USE SIGNAL ;
    PORT
      LAYER M5 ;
        RECT  96.72 0 96.744 0.084 ;
    END
  END rec[607]
  PIN rec[608]
    DIRECTION INPUT ;
    USE SIGNAL ;
    PORT
      LAYER M5 ;
        RECT  96.768 0 96.792 0.084 ;
    END
  END rec[608]
  PIN rec[609]
    DIRECTION INPUT ;
    USE SIGNAL ;
    PORT
      LAYER M5 ;
        RECT  96.816 0 96.84 0.084 ;
    END
  END rec[609]
  PIN rec[60]
    DIRECTION INPUT ;
    USE SIGNAL ;
    PORT
      LAYER M5 ;
        RECT  2.112 0 2.136 0.084 ;
    END
  END rec[60]
  PIN rec[610]
    DIRECTION INPUT ;
    USE SIGNAL ;
    PORT
      LAYER M5 ;
        RECT  96.864 0 96.888 0.084 ;
    END
  END rec[610]
  PIN rec[611]
    DIRECTION INPUT ;
    USE SIGNAL ;
    PORT
      LAYER M5 ;
        RECT  96.912 0 96.936 0.084 ;
    END
  END rec[611]
  PIN rec[612]
    DIRECTION INPUT ;
    USE SIGNAL ;
    PORT
      LAYER M5 ;
        RECT  96.96 0 96.984 0.084 ;
    END
  END rec[612]
  PIN rec[613]
    DIRECTION INPUT ;
    USE SIGNAL ;
    PORT
      LAYER M5 ;
        RECT  97.008 0 97.032 0.084 ;
    END
  END rec[613]
  PIN rec[614]
    DIRECTION INPUT ;
    USE SIGNAL ;
    PORT
      LAYER M5 ;
        RECT  97.056 0 97.08 0.084 ;
    END
  END rec[614]
  PIN rec[615]
    DIRECTION INPUT ;
    USE SIGNAL ;
    PORT
      LAYER M5 ;
        RECT  97.104 0 97.128 0.084 ;
    END
  END rec[615]
  PIN rec[616]
    DIRECTION INPUT ;
    USE SIGNAL ;
    PORT
      LAYER M5 ;
        RECT  97.152 0 97.176 0.084 ;
    END
  END rec[616]
  PIN rec[617]
    DIRECTION INPUT ;
    USE SIGNAL ;
    PORT
      LAYER M5 ;
        RECT  97.2 0 97.224 0.084 ;
    END
  END rec[617]
  PIN rec[618]
    DIRECTION INPUT ;
    USE SIGNAL ;
    PORT
      LAYER M5 ;
        RECT  97.248 0 97.272 0.084 ;
    END
  END rec[618]
  PIN rec[619]
    DIRECTION INPUT ;
    USE SIGNAL ;
    PORT
      LAYER M5 ;
        RECT  97.296 0 97.32 0.084 ;
    END
  END rec[619]
  PIN rec[61]
    DIRECTION INPUT ;
    USE SIGNAL ;
    PORT
      LAYER M5 ;
        RECT  2.16 0 2.184 0.084 ;
    END
  END rec[61]
  PIN rec[620]
    DIRECTION INPUT ;
    USE SIGNAL ;
    PORT
      LAYER M5 ;
        RECT  97.344 0 97.368 0.084 ;
    END
  END rec[620]
  PIN rec[621]
    DIRECTION INPUT ;
    USE SIGNAL ;
    PORT
      LAYER M5 ;
        RECT  97.392 0 97.416 0.084 ;
    END
  END rec[621]
  PIN rec[622]
    DIRECTION INPUT ;
    USE SIGNAL ;
    PORT
      LAYER M5 ;
        RECT  97.44 0 97.464 0.084 ;
    END
  END rec[622]
  PIN rec[623]
    DIRECTION INPUT ;
    USE SIGNAL ;
    PORT
      LAYER M5 ;
        RECT  97.488 0 97.512 0.084 ;
    END
  END rec[623]
  PIN rec[624]
    DIRECTION INPUT ;
    USE SIGNAL ;
    PORT
      LAYER M5 ;
        RECT  97.536 0 97.56 0.084 ;
    END
  END rec[624]
  PIN rec[625]
    DIRECTION INPUT ;
    USE SIGNAL ;
    PORT
      LAYER M5 ;
        RECT  97.584 0 97.608 0.084 ;
    END
  END rec[625]
  PIN rec[626]
    DIRECTION INPUT ;
    USE SIGNAL ;
    PORT
      LAYER M5 ;
        RECT  97.632 0 97.656 0.084 ;
    END
  END rec[626]
  PIN rec[627]
    DIRECTION INPUT ;
    USE SIGNAL ;
    PORT
      LAYER M5 ;
        RECT  97.68 0 97.704 0.084 ;
    END
  END rec[627]
  PIN rec[628]
    DIRECTION INPUT ;
    USE SIGNAL ;
    PORT
      LAYER M5 ;
        RECT  97.728 0 97.752 0.084 ;
    END
  END rec[628]
  PIN rec[629]
    DIRECTION INPUT ;
    USE SIGNAL ;
    PORT
      LAYER M5 ;
        RECT  97.776 0 97.8 0.084 ;
    END
  END rec[629]
  PIN rec[62]
    DIRECTION INPUT ;
    USE SIGNAL ;
    PORT
      LAYER M5 ;
        RECT  2.208 0 2.232 0.084 ;
    END
  END rec[62]
  PIN rec[630]
    DIRECTION INPUT ;
    USE SIGNAL ;
    PORT
      LAYER M5 ;
        RECT  97.824 0 97.848 0.084 ;
    END
  END rec[630]
  PIN rec[631]
    DIRECTION INPUT ;
    USE SIGNAL ;
    PORT
      LAYER M5 ;
        RECT  97.872 0 97.896 0.084 ;
    END
  END rec[631]
  PIN rec[632]
    DIRECTION INPUT ;
    USE SIGNAL ;
    PORT
      LAYER M5 ;
        RECT  97.92 0 97.944 0.084 ;
    END
  END rec[632]
  PIN rec[633]
    DIRECTION INPUT ;
    USE SIGNAL ;
    PORT
      LAYER M5 ;
        RECT  97.968 0 97.992 0.084 ;
    END
  END rec[633]
  PIN rec[634]
    DIRECTION INPUT ;
    USE SIGNAL ;
    PORT
      LAYER M5 ;
        RECT  98.016 0 98.04 0.084 ;
    END
  END rec[634]
  PIN rec[635]
    DIRECTION INPUT ;
    USE SIGNAL ;
    PORT
      LAYER M5 ;
        RECT  98.064 0 98.088 0.084 ;
    END
  END rec[635]
  PIN rec[636]
    DIRECTION INPUT ;
    USE SIGNAL ;
    PORT
      LAYER M5 ;
        RECT  98.112 0 98.136 0.084 ;
    END
  END rec[636]
  PIN rec[637]
    DIRECTION INPUT ;
    USE SIGNAL ;
    PORT
      LAYER M5 ;
        RECT  98.16 0 98.184 0.084 ;
    END
  END rec[637]
  PIN rec[638]
    DIRECTION INPUT ;
    USE SIGNAL ;
    PORT
      LAYER M5 ;
        RECT  98.208 0 98.232 0.084 ;
    END
  END rec[638]
  PIN rec[639]
    DIRECTION INPUT ;
    USE SIGNAL ;
    PORT
      LAYER M5 ;
        RECT  46.8 0 46.824 0.084 ;
    END
  END rec[639]
  PIN rec[63]
    DIRECTION INPUT ;
    USE SIGNAL ;
    PORT
      LAYER M5 ;
        RECT  45.264 0 45.288 0.084 ;
    END
  END rec[63]
  PIN rec[640]
    DIRECTION INPUT ;
    USE SIGNAL ;
    PORT
      LAYER M5 ;
        RECT  46.848 0 46.872 0.084 ;
    END
  END rec[640]
  PIN rec[641]
    DIRECTION INPUT ;
    USE SIGNAL ;
    PORT
      LAYER M5 ;
        RECT  46.896 0 46.92 0.084 ;
    END
  END rec[641]
  PIN rec[642]
    DIRECTION INPUT ;
    USE SIGNAL ;
    PORT
      LAYER M5 ;
        RECT  46.944 0 46.968 0.084 ;
    END
  END rec[642]
  PIN rec[643]
    DIRECTION INPUT ;
    USE SIGNAL ;
    PORT
      LAYER M5 ;
        RECT  46.992 0 47.016 0.084 ;
    END
  END rec[643]
  PIN rec[644]
    DIRECTION INPUT ;
    USE SIGNAL ;
    PORT
      LAYER M5 ;
        RECT  47.04 0 47.064 0.084 ;
    END
  END rec[644]
  PIN rec[645]
    DIRECTION INPUT ;
    USE SIGNAL ;
    PORT
      LAYER M5 ;
        RECT  47.088 0 47.112 0.084 ;
    END
  END rec[645]
  PIN rec[646]
    DIRECTION INPUT ;
    USE SIGNAL ;
    PORT
      LAYER M5 ;
        RECT  47.136 0 47.16 0.084 ;
    END
  END rec[646]
  PIN rec[647]
    DIRECTION INPUT ;
    USE SIGNAL ;
    PORT
      LAYER M5 ;
        RECT  47.184 0 47.208 0.084 ;
    END
  END rec[647]
  PIN rec[648]
    DIRECTION INPUT ;
    USE SIGNAL ;
    PORT
      LAYER M5 ;
        RECT  47.232 0 47.256 0.084 ;
    END
  END rec[648]
  PIN rec[649]
    DIRECTION INPUT ;
    USE SIGNAL ;
    PORT
      LAYER M5 ;
        RECT  47.28 0 47.304 0.084 ;
    END
  END rec[649]
  PIN rec[64]
    DIRECTION INPUT ;
    USE SIGNAL ;
    PORT
      LAYER M5 ;
        RECT  45.312 0 45.336 0.084 ;
    END
  END rec[64]
  PIN rec[650]
    DIRECTION INPUT ;
    USE SIGNAL ;
    PORT
      LAYER M5 ;
        RECT  47.328 0 47.352 0.084 ;
    END
  END rec[650]
  PIN rec[651]
    DIRECTION INPUT ;
    USE SIGNAL ;
    PORT
      LAYER M5 ;
        RECT  47.376 0 47.4 0.084 ;
    END
  END rec[651]
  PIN rec[652]
    DIRECTION INPUT ;
    USE SIGNAL ;
    PORT
      LAYER M5 ;
        RECT  47.424 0 47.448 0.084 ;
    END
  END rec[652]
  PIN rec[653]
    DIRECTION INPUT ;
    USE SIGNAL ;
    PORT
      LAYER M5 ;
        RECT  47.472 0 47.496 0.084 ;
    END
  END rec[653]
  PIN rec[654]
    DIRECTION INPUT ;
    USE SIGNAL ;
    PORT
      LAYER M5 ;
        RECT  47.52 0 47.544 0.084 ;
    END
  END rec[654]
  PIN rec[655]
    DIRECTION INPUT ;
    USE SIGNAL ;
    PORT
      LAYER M5 ;
        RECT  47.568 0 47.592 0.084 ;
    END
  END rec[655]
  PIN rec[656]
    DIRECTION INPUT ;
    USE SIGNAL ;
    PORT
      LAYER M5 ;
        RECT  47.616 0 47.64 0.084 ;
    END
  END rec[656]
  PIN rec[657]
    DIRECTION INPUT ;
    USE SIGNAL ;
    PORT
      LAYER M5 ;
        RECT  47.664 0 47.688 0.084 ;
    END
  END rec[657]
  PIN rec[658]
    DIRECTION INPUT ;
    USE SIGNAL ;
    PORT
      LAYER M5 ;
        RECT  47.712 0 47.736 0.084 ;
    END
  END rec[658]
  PIN rec[659]
    DIRECTION INPUT ;
    USE SIGNAL ;
    PORT
      LAYER M5 ;
        RECT  47.76 0 47.784 0.084 ;
    END
  END rec[659]
  PIN rec[65]
    DIRECTION INPUT ;
    USE SIGNAL ;
    PORT
      LAYER M5 ;
        RECT  45.36 0 45.384 0.084 ;
    END
  END rec[65]
  PIN rec[660]
    DIRECTION INPUT ;
    USE SIGNAL ;
    PORT
      LAYER M5 ;
        RECT  47.808 0 47.832 0.084 ;
    END
  END rec[660]
  PIN rec[661]
    DIRECTION INPUT ;
    USE SIGNAL ;
    PORT
      LAYER M5 ;
        RECT  47.856 0 47.88 0.084 ;
    END
  END rec[661]
  PIN rec[662]
    DIRECTION INPUT ;
    USE SIGNAL ;
    PORT
      LAYER M5 ;
        RECT  47.904 0 47.928 0.084 ;
    END
  END rec[662]
  PIN rec[663]
    DIRECTION INPUT ;
    USE SIGNAL ;
    PORT
      LAYER M5 ;
        RECT  47.952 0 47.976 0.084 ;
    END
  END rec[663]
  PIN rec[664]
    DIRECTION INPUT ;
    USE SIGNAL ;
    PORT
      LAYER M5 ;
        RECT  48 0 48.024 0.084 ;
    END
  END rec[664]
  PIN rec[665]
    DIRECTION INPUT ;
    USE SIGNAL ;
    PORT
      LAYER M5 ;
        RECT  48.048 0 48.072 0.084 ;
    END
  END rec[665]
  PIN rec[666]
    DIRECTION INPUT ;
    USE SIGNAL ;
    PORT
      LAYER M5 ;
        RECT  48.096 0 48.12 0.084 ;
    END
  END rec[666]
  PIN rec[667]
    DIRECTION INPUT ;
    USE SIGNAL ;
    PORT
      LAYER M5 ;
        RECT  48.144 0 48.168 0.084 ;
    END
  END rec[667]
  PIN rec[668]
    DIRECTION INPUT ;
    USE SIGNAL ;
    PORT
      LAYER M5 ;
        RECT  48.192 0 48.216 0.084 ;
    END
  END rec[668]
  PIN rec[669]
    DIRECTION INPUT ;
    USE SIGNAL ;
    PORT
      LAYER M5 ;
        RECT  48.24 0 48.264 0.084 ;
    END
  END rec[669]
  PIN rec[66]
    DIRECTION INPUT ;
    USE SIGNAL ;
    PORT
      LAYER M5 ;
        RECT  45.408 0 45.432 0.084 ;
    END
  END rec[66]
  PIN rec[670]
    DIRECTION INPUT ;
    USE SIGNAL ;
    PORT
      LAYER M5 ;
        RECT  48.288 0 48.312 0.084 ;
    END
  END rec[670]
  PIN rec[671]
    DIRECTION INPUT ;
    USE SIGNAL ;
    PORT
      LAYER M5 ;
        RECT  43.728 0 43.752 0.084 ;
    END
  END rec[671]
  PIN rec[672]
    DIRECTION INPUT ;
    USE SIGNAL ;
    PORT
      LAYER M5 ;
        RECT  43.776 0 43.8 0.084 ;
    END
  END rec[672]
  PIN rec[673]
    DIRECTION INPUT ;
    USE SIGNAL ;
    PORT
      LAYER M5 ;
        RECT  43.824 0 43.848 0.084 ;
    END
  END rec[673]
  PIN rec[674]
    DIRECTION INPUT ;
    USE SIGNAL ;
    PORT
      LAYER M5 ;
        RECT  43.872 0 43.896 0.084 ;
    END
  END rec[674]
  PIN rec[675]
    DIRECTION INPUT ;
    USE SIGNAL ;
    PORT
      LAYER M5 ;
        RECT  43.92 0 43.944 0.084 ;
    END
  END rec[675]
  PIN rec[676]
    DIRECTION INPUT ;
    USE SIGNAL ;
    PORT
      LAYER M5 ;
        RECT  43.968 0 43.992 0.084 ;
    END
  END rec[676]
  PIN rec[677]
    DIRECTION INPUT ;
    USE SIGNAL ;
    PORT
      LAYER M5 ;
        RECT  44.016 0 44.04 0.084 ;
    END
  END rec[677]
  PIN rec[678]
    DIRECTION INPUT ;
    USE SIGNAL ;
    PORT
      LAYER M5 ;
        RECT  44.064 0 44.088 0.084 ;
    END
  END rec[678]
  PIN rec[679]
    DIRECTION INPUT ;
    USE SIGNAL ;
    PORT
      LAYER M5 ;
        RECT  44.112 0 44.136 0.084 ;
    END
  END rec[679]
  PIN rec[67]
    DIRECTION INPUT ;
    USE SIGNAL ;
    PORT
      LAYER M5 ;
        RECT  45.456 0 45.48 0.084 ;
    END
  END rec[67]
  PIN rec[680]
    DIRECTION INPUT ;
    USE SIGNAL ;
    PORT
      LAYER M5 ;
        RECT  44.16 0 44.184 0.084 ;
    END
  END rec[680]
  PIN rec[681]
    DIRECTION INPUT ;
    USE SIGNAL ;
    PORT
      LAYER M5 ;
        RECT  44.208 0 44.232 0.084 ;
    END
  END rec[681]
  PIN rec[682]
    DIRECTION INPUT ;
    USE SIGNAL ;
    PORT
      LAYER M5 ;
        RECT  44.256 0 44.28 0.084 ;
    END
  END rec[682]
  PIN rec[68]
    DIRECTION INPUT ;
    USE SIGNAL ;
    PORT
      LAYER M5 ;
        RECT  45.504 0 45.528 0.084 ;
    END
  END rec[68]
  PIN rec[69]
    DIRECTION INPUT ;
    USE SIGNAL ;
    PORT
      LAYER M5 ;
        RECT  45.552 0 45.576 0.084 ;
    END
  END rec[69]
  PIN rec[6]
    DIRECTION INPUT ;
    USE SIGNAL ;
    PORT
      LAYER M5 ;
        RECT  40.992 0 41.016 0.084 ;
    END
  END rec[6]
  PIN rec[70]
    DIRECTION INPUT ;
    USE SIGNAL ;
    PORT
      LAYER M5 ;
        RECT  45.6 0 45.624 0.084 ;
    END
  END rec[70]
  PIN rec[71]
    DIRECTION INPUT ;
    USE SIGNAL ;
    PORT
      LAYER M5 ;
        RECT  45.648 0 45.672 0.084 ;
    END
  END rec[71]
  PIN rec[72]
    DIRECTION INPUT ;
    USE SIGNAL ;
    PORT
      LAYER M5 ;
        RECT  45.696 0 45.72 0.084 ;
    END
  END rec[72]
  PIN rec[73]
    DIRECTION INPUT ;
    USE SIGNAL ;
    PORT
      LAYER M5 ;
        RECT  45.744 0 45.768 0.084 ;
    END
  END rec[73]
  PIN rec[74]
    DIRECTION INPUT ;
    USE SIGNAL ;
    PORT
      LAYER M5 ;
        RECT  45.792 0 45.816 0.084 ;
    END
  END rec[74]
  PIN rec[75]
    DIRECTION INPUT ;
    USE SIGNAL ;
    PORT
      LAYER M5 ;
        RECT  45.84 0 45.864 0.084 ;
    END
  END rec[75]
  PIN rec[76]
    DIRECTION INPUT ;
    USE SIGNAL ;
    PORT
      LAYER M5 ;
        RECT  45.888 0 45.912 0.084 ;
    END
  END rec[76]
  PIN rec[77]
    DIRECTION INPUT ;
    USE SIGNAL ;
    PORT
      LAYER M5 ;
        RECT  45.936 0 45.96 0.084 ;
    END
  END rec[77]
  PIN rec[78]
    DIRECTION INPUT ;
    USE SIGNAL ;
    PORT
      LAYER M5 ;
        RECT  45.984 0 46.008 0.084 ;
    END
  END rec[78]
  PIN rec[79]
    DIRECTION INPUT ;
    USE SIGNAL ;
    PORT
      LAYER M5 ;
        RECT  46.032 0 46.056 0.084 ;
    END
  END rec[79]
  PIN rec[7]
    DIRECTION INPUT ;
    USE SIGNAL ;
    PORT
      LAYER M5 ;
        RECT  41.04 0 41.064 0.084 ;
    END
  END rec[7]
  PIN rec[80]
    DIRECTION INPUT ;
    USE SIGNAL ;
    PORT
      LAYER M5 ;
        RECT  46.08 0 46.104 0.084 ;
    END
  END rec[80]
  PIN rec[81]
    DIRECTION INPUT ;
    USE SIGNAL ;
    PORT
      LAYER M5 ;
        RECT  46.128 0 46.152 0.084 ;
    END
  END rec[81]
  PIN rec[82]
    DIRECTION INPUT ;
    USE SIGNAL ;
    PORT
      LAYER M5 ;
        RECT  46.176 0 46.2 0.084 ;
    END
  END rec[82]
  PIN rec[83]
    DIRECTION INPUT ;
    USE SIGNAL ;
    PORT
      LAYER M5 ;
        RECT  46.224 0 46.248 0.084 ;
    END
  END rec[83]
  PIN rec[84]
    DIRECTION INPUT ;
    USE SIGNAL ;
    PORT
      LAYER M5 ;
        RECT  46.272 0 46.296 0.084 ;
    END
  END rec[84]
  PIN rec[85]
    DIRECTION INPUT ;
    USE SIGNAL ;
    PORT
      LAYER M5 ;
        RECT  46.32 0 46.344 0.084 ;
    END
  END rec[85]
  PIN rec[86]
    DIRECTION INPUT ;
    USE SIGNAL ;
    PORT
      LAYER M5 ;
        RECT  46.368 0 46.392 0.084 ;
    END
  END rec[86]
  PIN rec[87]
    DIRECTION INPUT ;
    USE SIGNAL ;
    PORT
      LAYER M5 ;
        RECT  46.416 0 46.44 0.084 ;
    END
  END rec[87]
  PIN rec[88]
    DIRECTION INPUT ;
    USE SIGNAL ;
    PORT
      LAYER M5 ;
        RECT  46.464 0 46.488 0.084 ;
    END
  END rec[88]
  PIN rec[89]
    DIRECTION INPUT ;
    USE SIGNAL ;
    PORT
      LAYER M5 ;
        RECT  46.512 0 46.536 0.084 ;
    END
  END rec[89]
  PIN rec[8]
    DIRECTION INPUT ;
    USE SIGNAL ;
    PORT
      LAYER M5 ;
        RECT  41.088 0 41.112 0.084 ;
    END
  END rec[8]
  PIN rec[90]
    DIRECTION INPUT ;
    USE SIGNAL ;
    PORT
      LAYER M5 ;
        RECT  46.56 0 46.584 0.084 ;
    END
  END rec[90]
  PIN rec[91]
    DIRECTION INPUT ;
    USE SIGNAL ;
    PORT
      LAYER M5 ;
        RECT  46.608 0 46.632 0.084 ;
    END
  END rec[91]
  PIN rec[92]
    DIRECTION INPUT ;
    USE SIGNAL ;
    PORT
      LAYER M5 ;
        RECT  46.656 0 46.68 0.084 ;
    END
  END rec[92]
  PIN rec[93]
    DIRECTION INPUT ;
    USE SIGNAL ;
    PORT
      LAYER M5 ;
        RECT  46.704 0 46.728 0.084 ;
    END
  END rec[93]
  PIN rec[94]
    DIRECTION INPUT ;
    USE SIGNAL ;
    PORT
      LAYER M5 ;
        RECT  46.752 0 46.776 0.084 ;
    END
  END rec[94]
  PIN rec[95]
    DIRECTION INPUT ;
    USE SIGNAL ;
    PORT
      LAYER M5 ;
        RECT  51.792 0 51.816 0.084 ;
    END
  END rec[95]
  PIN rec[96]
    DIRECTION INPUT ;
    USE SIGNAL ;
    PORT
      LAYER M5 ;
        RECT  51.84 0 51.864 0.084 ;
    END
  END rec[96]
  PIN rec[97]
    DIRECTION INPUT ;
    USE SIGNAL ;
    PORT
      LAYER M5 ;
        RECT  51.888 0 51.912 0.084 ;
    END
  END rec[97]
  PIN rec[98]
    DIRECTION INPUT ;
    USE SIGNAL ;
    PORT
      LAYER M5 ;
        RECT  51.936 0 51.96 0.084 ;
    END
  END rec[98]
  PIN rec[99]
    DIRECTION INPUT ;
    USE SIGNAL ;
    PORT
      LAYER M5 ;
        RECT  51.984 0 52.008 0.084 ;
    END
  END rec[99]
  PIN rec[9]
    DIRECTION INPUT ;
    USE SIGNAL ;
    PORT
      LAYER M5 ;
        RECT  41.136 0 41.16 0.084 ;
    END
  END rec[9]
  PIN rst_n
    DIRECTION INPUT ;
    USE SIGNAL ;
    PORT
      LAYER M5 ;
        RECT  44.304 0 44.328 0.084 ;
    END
  END rst_n
  PIN s1_v
    DIRECTION OUTPUT ;
    USE SIGNAL ;
    PORT
      LAYER M5 ;
        RECT  47.424 71.196 47.448 71.28 ;
    END
  END s1_v
  PIN VDD
    DIRECTION INOUT ;
    USE POWER ;
    PORT
      LAYER M5 ;
        RECT  126.792 2.151 126.912 69.129 ;
        RECT  121.392 2.151 121.512 69.129 ;
        RECT  115.992 2.151 116.112 69.129 ;
        RECT  110.592 2.151 110.712 69.129 ;
        RECT  105.192 2.151 105.312 69.129 ;
        RECT  99.792 2.151 99.912 69.129 ;
        RECT  94.392 2.151 94.512 69.129 ;
        RECT  88.992 2.151 89.112 69.129 ;
        RECT  83.592 2.151 83.712 69.129 ;
        RECT  78.192 2.151 78.312 69.129 ;
        RECT  72.792 2.151 72.912 69.129 ;
        RECT  67.392 2.151 67.512 69.129 ;
        RECT  61.992 2.151 62.112 69.129 ;
        RECT  56.592 2.151 56.712 69.129 ;
        RECT  51.192 2.151 51.312 69.129 ;
        RECT  45.792 2.151 45.912 69.129 ;
        RECT  40.392 2.151 40.512 69.129 ;
        RECT  34.992 2.151 35.112 69.129 ;
        RECT  29.592 2.151 29.712 69.129 ;
        RECT  24.192 2.151 24.312 69.129 ;
        RECT  18.792 2.151 18.912 69.129 ;
        RECT  13.392 2.151 13.512 69.129 ;
        RECT  7.992 2.151 8.112 69.129 ;
        RECT  2.592 2.151 2.712 69.129 ;
    END
  END VDD
  PIN VSS
    DIRECTION INOUT ;
    USE GROUND ;
    PORT
      LAYER M5 ;
        RECT  126.6 2.137 126.72 69.143 ;
        RECT  121.2 2.137 121.32 69.143 ;
        RECT  115.8 2.137 115.92 69.143 ;
        RECT  110.4 2.137 110.52 69.143 ;
        RECT  105 2.137 105.12 69.143 ;
        RECT  99.6 2.137 99.72 69.143 ;
        RECT  94.2 2.137 94.32 69.143 ;
        RECT  88.8 2.137 88.92 69.143 ;
        RECT  83.4 2.137 83.52 69.143 ;
        RECT  78 2.137 78.12 69.143 ;
        RECT  72.6 2.137 72.72 69.143 ;
        RECT  67.2 2.137 67.32 69.143 ;
        RECT  61.8 2.137 61.92 69.143 ;
        RECT  56.4 2.137 56.52 69.143 ;
        RECT  51 2.137 51.12 69.143 ;
        RECT  45.6 2.137 45.72 69.143 ;
        RECT  40.2 2.137 40.32 69.143 ;
        RECT  34.8 2.137 34.92 69.143 ;
        RECT  29.4 2.137 29.52 69.143 ;
        RECT  24 2.137 24.12 69.143 ;
        RECT  18.6 2.137 18.72 69.143 ;
        RECT  13.2 2.137 13.32 69.143 ;
        RECT  7.8 2.137 7.92 69.143 ;
        RECT  2.4 2.137 2.52 69.143 ;
    END
  END VSS
  # OT_OBS_CLOSED layer=M5 d_um=1.536 added=103
  OBS
    LAYER RVTN ;
     RECT  2.16 2.16 127.44 2.295 ;
     RECT  2.16 2.565 127.44 2.835 ;
     RECT  2.16 3.105 127.44 3.375 ;
     RECT  2.16 3.645 127.44 3.915 ;
     RECT  2.16 4.185 127.44 4.455 ;
     RECT  2.16 4.725 127.44 4.995 ;
     RECT  2.16 5.265 127.44 5.535 ;
     RECT  2.16 5.805 127.44 6.075 ;
     RECT  2.16 6.345 127.44 6.615 ;
     RECT  2.16 6.885 127.44 7.155 ;
     RECT  2.16 7.425 127.44 7.695 ;
     RECT  2.16 7.965 127.44 8.235 ;
     RECT  2.16 8.505 127.44 8.775 ;
     RECT  2.16 9.045 127.44 9.315 ;
     RECT  2.16 9.585 127.44 9.855 ;
     RECT  2.16 10.125 127.44 10.395 ;
     RECT  2.16 10.665 127.44 10.935 ;
     RECT  2.16 11.205 127.44 11.475 ;
     RECT  2.16 11.745 127.44 12.015 ;
     RECT  2.16 12.285 127.44 12.555 ;
     RECT  2.16 12.825 127.44 13.095 ;
     RECT  2.16 13.365 127.44 13.635 ;
     RECT  2.16 13.905 127.44 14.175 ;
     RECT  2.16 14.445 127.44 14.715 ;
     RECT  2.16 14.985 127.44 15.255 ;
     RECT  2.16 15.525 127.44 15.795 ;
     RECT  2.16 16.065 127.44 16.335 ;
     RECT  2.16 16.605 127.44 16.875 ;
     RECT  2.16 17.145 127.44 17.415 ;
     RECT  2.16 17.685 127.44 17.955 ;
     RECT  2.16 18.225 127.44 18.495 ;
     RECT  2.16 18.765 127.44 19.035 ;
     RECT  2.16 19.305 127.44 19.575 ;
     RECT  2.16 19.845 127.44 20.115 ;
     RECT  2.16 20.385 127.44 20.655 ;
     RECT  2.16 20.925 127.44 21.195 ;
     RECT  2.16 21.465 127.44 21.735 ;
     RECT  2.16 22.005 127.44 22.275 ;
     RECT  2.16 22.545 127.44 22.815 ;
     RECT  2.16 23.085 127.44 23.355 ;
     RECT  2.16 23.625 127.44 23.895 ;
     RECT  2.16 24.165 127.44 24.435 ;
     RECT  2.16 24.705 127.44 24.975 ;
     RECT  2.16 25.245 127.44 25.515 ;
     RECT  2.16 25.785 127.44 26.055 ;
     RECT  2.16 26.325 127.44 26.595 ;
     RECT  2.16 26.865 127.44 27.135 ;
     RECT  2.16 27.405 127.44 27.675 ;
     RECT  2.16 27.945 127.44 28.215 ;
     RECT  2.16 28.485 127.44 28.755 ;
     RECT  2.16 29.025 127.44 29.295 ;
     RECT  2.16 29.565 127.44 29.835 ;
     RECT  2.16 30.105 127.44 30.375 ;
     RECT  2.16 30.645 127.44 30.915 ;
     RECT  2.16 31.185 127.44 31.455 ;
     RECT  2.16 31.725 127.44 31.995 ;
     RECT  2.16 32.265 127.44 32.535 ;
     RECT  2.16 32.805 127.44 33.075 ;
     RECT  2.16 33.345 127.44 33.615 ;
     RECT  2.16 33.885 127.44 34.155 ;
     RECT  2.16 34.425 127.44 34.695 ;
     RECT  2.16 34.965 127.44 35.235 ;
     RECT  2.16 35.505 127.44 35.775 ;
     RECT  2.16 36.045 127.44 36.315 ;
     RECT  2.16 36.585 127.44 36.855 ;
     RECT  2.16 37.125 127.44 37.395 ;
     RECT  2.16 37.665 127.44 37.935 ;
     RECT  2.16 38.205 127.44 38.475 ;
     RECT  2.16 38.745 127.44 39.015 ;
     RECT  2.16 39.285 127.44 39.555 ;
     RECT  2.16 39.825 127.44 40.095 ;
     RECT  2.16 40.365 127.44 40.635 ;
     RECT  2.16 40.905 127.44 41.175 ;
     RECT  2.16 41.445 127.44 41.715 ;
     RECT  2.16 41.985 127.44 42.255 ;
     RECT  2.16 42.525 127.44 42.795 ;
     RECT  2.16 43.065 127.44 43.335 ;
     RECT  2.16 43.605 127.44 43.875 ;
     RECT  2.16 44.145 127.44 44.415 ;
     RECT  2.16 44.685 127.44 44.955 ;
     RECT  2.16 45.225 127.44 45.495 ;
     RECT  2.16 45.765 127.44 46.035 ;
     RECT  2.16 46.305 127.44 46.575 ;
     RECT  2.16 46.845 127.44 47.115 ;
     RECT  2.16 47.385 127.44 47.655 ;
     RECT  2.16 47.925 127.44 48.195 ;
     RECT  2.16 48.465 127.44 48.735 ;
     RECT  2.16 49.005 127.44 49.275 ;
     RECT  2.16 49.545 127.44 49.815 ;
     RECT  2.16 50.085 127.44 50.355 ;
     RECT  2.16 50.625 127.44 50.895 ;
     RECT  2.16 51.165 127.44 51.435 ;
     RECT  2.16 51.705 127.44 51.975 ;
     RECT  2.16 52.245 127.44 52.515 ;
     RECT  2.16 52.785 127.44 53.055 ;
     RECT  2.16 53.325 127.44 53.595 ;
     RECT  2.16 53.865 127.44 54.135 ;
     RECT  2.16 54.405 127.44 54.675 ;
     RECT  2.16 54.945 127.44 55.215 ;
     RECT  2.16 55.485 127.44 55.755 ;
     RECT  2.16 56.025 127.44 56.295 ;
     RECT  2.16 56.565 127.44 56.835 ;
     RECT  2.16 57.105 127.44 57.375 ;
     RECT  2.16 57.645 127.44 57.915 ;
     RECT  2.16 58.185 127.44 58.455 ;
     RECT  2.16 58.725 127.44 58.995 ;
     RECT  2.16 59.265 127.44 59.535 ;
     RECT  2.16 59.805 127.44 60.075 ;
     RECT  2.16 60.345 127.44 60.615 ;
     RECT  2.16 60.885 127.44 61.155 ;
     RECT  2.16 61.425 127.44 61.695 ;
     RECT  2.16 61.965 127.44 62.235 ;
     RECT  2.16 62.505 127.44 62.775 ;
     RECT  2.16 63.045 127.44 63.315 ;
     RECT  2.16 63.585 127.44 63.855 ;
     RECT  2.16 64.125 127.44 64.395 ;
     RECT  2.16 64.665 127.44 64.935 ;
     RECT  2.16 65.205 127.44 65.475 ;
     RECT  2.16 65.745 127.44 66.015 ;
     RECT  2.16 66.285 127.44 66.555 ;
     RECT  2.16 66.825 127.44 67.095 ;
     RECT  2.16 67.365 127.44 67.635 ;
     RECT  2.16 67.905 127.44 68.175 ;
     RECT  2.16 68.445 127.44 68.715 ;
     RECT  2.16 68.985 127.44 69.12 ;
    LAYER RVTP ;
     RECT  2.16 2.295 127.44 2.565 ;
     RECT  2.16 2.835 127.44 3.105 ;
     RECT  2.16 3.375 127.44 3.645 ;
     RECT  2.16 3.915 127.44 4.185 ;
     RECT  2.16 4.455 127.44 4.725 ;
     RECT  2.16 4.995 127.44 5.265 ;
     RECT  2.16 5.535 127.44 5.805 ;
     RECT  2.16 6.075 127.44 6.345 ;
     RECT  2.16 6.615 127.44 6.885 ;
     RECT  2.16 7.155 127.44 7.425 ;
     RECT  2.16 7.695 127.44 7.965 ;
     RECT  2.16 8.235 127.44 8.505 ;
     RECT  2.16 8.775 127.44 9.045 ;
     RECT  2.16 9.315 127.44 9.585 ;
     RECT  2.16 9.855 127.44 10.125 ;
     RECT  2.16 10.395 127.44 10.665 ;
     RECT  2.16 10.935 127.44 11.205 ;
     RECT  2.16 11.475 127.44 11.745 ;
     RECT  2.16 12.015 127.44 12.285 ;
     RECT  2.16 12.555 127.44 12.825 ;
     RECT  2.16 13.095 127.44 13.365 ;
     RECT  2.16 13.635 127.44 13.905 ;
     RECT  2.16 14.175 127.44 14.445 ;
     RECT  2.16 14.715 127.44 14.985 ;
     RECT  2.16 15.255 127.44 15.525 ;
     RECT  2.16 15.795 127.44 16.065 ;
     RECT  2.16 16.335 127.44 16.605 ;
     RECT  2.16 16.875 127.44 17.145 ;
     RECT  2.16 17.415 127.44 17.685 ;
     RECT  2.16 17.955 127.44 18.225 ;
     RECT  2.16 18.495 127.44 18.765 ;
     RECT  2.16 19.035 127.44 19.305 ;
     RECT  2.16 19.575 127.44 19.845 ;
     RECT  2.16 20.115 127.44 20.385 ;
     RECT  2.16 20.655 127.44 20.925 ;
     RECT  2.16 21.195 127.44 21.465 ;
     RECT  2.16 21.735 127.44 22.005 ;
     RECT  2.16 22.275 127.44 22.545 ;
     RECT  2.16 22.815 127.44 23.085 ;
     RECT  2.16 23.355 127.44 23.625 ;
     RECT  2.16 23.895 127.44 24.165 ;
     RECT  2.16 24.435 127.44 24.705 ;
     RECT  2.16 24.975 127.44 25.245 ;
     RECT  2.16 25.515 127.44 25.785 ;
     RECT  2.16 26.055 127.44 26.325 ;
     RECT  2.16 26.595 127.44 26.865 ;
     RECT  2.16 27.135 127.44 27.405 ;
     RECT  2.16 27.675 127.44 27.945 ;
     RECT  2.16 28.215 127.44 28.485 ;
     RECT  2.16 28.755 127.44 29.025 ;
     RECT  2.16 29.295 127.44 29.565 ;
     RECT  2.16 29.835 127.44 30.105 ;
     RECT  2.16 30.375 127.44 30.645 ;
     RECT  2.16 30.915 127.44 31.185 ;
     RECT  2.16 31.455 127.44 31.725 ;
     RECT  2.16 31.995 127.44 32.265 ;
     RECT  2.16 32.535 127.44 32.805 ;
     RECT  2.16 33.075 127.44 33.345 ;
     RECT  2.16 33.615 127.44 33.885 ;
     RECT  2.16 34.155 127.44 34.425 ;
     RECT  2.16 34.695 127.44 34.965 ;
     RECT  2.16 35.235 127.44 35.505 ;
     RECT  2.16 35.775 127.44 36.045 ;
     RECT  2.16 36.315 127.44 36.585 ;
     RECT  2.16 36.855 127.44 37.125 ;
     RECT  2.16 37.395 127.44 37.665 ;
     RECT  2.16 37.935 127.44 38.205 ;
     RECT  2.16 38.475 127.44 38.745 ;
     RECT  2.16 39.015 127.44 39.285 ;
     RECT  2.16 39.555 127.44 39.825 ;
     RECT  2.16 40.095 127.44 40.365 ;
     RECT  2.16 40.635 127.44 40.905 ;
     RECT  2.16 41.175 127.44 41.445 ;
     RECT  2.16 41.715 127.44 41.985 ;
     RECT  2.16 42.255 127.44 42.525 ;
     RECT  2.16 42.795 127.44 43.065 ;
     RECT  2.16 43.335 127.44 43.605 ;
     RECT  2.16 43.875 127.44 44.145 ;
     RECT  2.16 44.415 127.44 44.685 ;
     RECT  2.16 44.955 127.44 45.225 ;
     RECT  2.16 45.495 127.44 45.765 ;
     RECT  2.16 46.035 127.44 46.305 ;
     RECT  2.16 46.575 127.44 46.845 ;
     RECT  2.16 47.115 127.44 47.385 ;
     RECT  2.16 47.655 127.44 47.925 ;
     RECT  2.16 48.195 127.44 48.465 ;
     RECT  2.16 48.735 127.44 49.005 ;
     RECT  2.16 49.275 127.44 49.545 ;
     RECT  2.16 49.815 127.44 50.085 ;
     RECT  2.16 50.355 127.44 50.625 ;
     RECT  2.16 50.895 127.44 51.165 ;
     RECT  2.16 51.435 127.44 51.705 ;
     RECT  2.16 51.975 127.44 52.245 ;
     RECT  2.16 52.515 127.44 52.785 ;
     RECT  2.16 53.055 127.44 53.325 ;
     RECT  2.16 53.595 127.44 53.865 ;
     RECT  2.16 54.135 127.44 54.405 ;
     RECT  2.16 54.675 127.44 54.945 ;
     RECT  2.16 55.215 127.44 55.485 ;
     RECT  2.16 55.755 127.44 56.025 ;
     RECT  2.16 56.295 127.44 56.565 ;
     RECT  2.16 56.835 127.44 57.105 ;
     RECT  2.16 57.375 127.44 57.645 ;
     RECT  2.16 57.915 127.44 58.185 ;
     RECT  2.16 58.455 127.44 58.725 ;
     RECT  2.16 58.995 127.44 59.265 ;
     RECT  2.16 59.535 127.44 59.805 ;
     RECT  2.16 60.075 127.44 60.345 ;
     RECT  2.16 60.615 127.44 60.885 ;
     RECT  2.16 61.155 127.44 61.425 ;
     RECT  2.16 61.695 127.44 61.965 ;
     RECT  2.16 62.235 127.44 62.505 ;
     RECT  2.16 62.775 127.44 63.045 ;
     RECT  2.16 63.315 127.44 63.585 ;
     RECT  2.16 63.855 127.44 64.125 ;
     RECT  2.16 64.395 127.44 64.665 ;
     RECT  2.16 64.935 127.44 65.205 ;
     RECT  2.16 65.475 127.44 65.745 ;
     RECT  2.16 66.015 127.44 66.285 ;
     RECT  2.16 66.555 127.44 66.825 ;
     RECT  2.16 67.095 127.44 67.365 ;
     RECT  2.16 67.635 127.44 67.905 ;
     RECT  2.16 68.175 127.44 68.445 ;
     RECT  2.16 68.715 127.44 68.985 ;
    LAYER M1 ;
     RECT  2.16 2.151 127.44 69.129 ;
    LAYER M2 ;
     RECT  2.16 2.151 56.083 69.129 ;
     RECT  56.083 2.07 56.471 69.129 ;
     RECT  61.591 1.152 61.691 1.17 ;
     RECT  56.471 2.151 62.419 69.129 ;
     RECT  62.419 2.106 63.427 69.129 ;
     RECT  63.427 1.728 63.527 69.129 ;
     RECT  63.571 70.65 63.815 70.668 ;
     RECT  64.507 1.152 64.895 1.17 ;
     RECT  63.527 2.151 71.959 69.129 ;
     RECT  71.959 2.151 72.995 69.174 ;
     RECT  72.995 2.151 73.687 69.129 ;
     RECT  73.687 2.106 74.147 69.129 ;
     RECT  74.839 70.236 74.911 70.254 ;
     RECT  74.911 70.236 74.939 70.668 ;
     RECT  74.939 70.65 75.047 70.668 ;
     RECT  78.403 70.578 78.439 70.596 ;
     RECT  78.439 70.578 78.503 70.668 ;
     RECT  78.503 70.65 78.647 70.668 ;
     RECT  80.203 70.65 80.375 70.668 ;
     RECT  82.147 70.65 82.427 70.668 ;
     RECT  74.147 2.151 83.731 69.129 ;
     RECT  83.731 2.151 83.867 69.174 ;
     RECT  83.867 2.151 127.44 69.129 ;
    LAYER M3 ;
     RECT  62.784 0.091 62.802 0.139 ;
     RECT  74.232 0.091 74.25 0.139 ;
     RECT  66.276 0.139 66.294 0.187 ;
     RECT  67.032 0.139 67.05 0.187 ;
     RECT  76.68 0.139 76.698 0.187 ;
     RECT  41.832 0.139 41.85 0.235 ;
     RECT  56.448 0.139 56.466 0.235 ;
     RECT  76.464 0.187 76.698 0.283 ;
     RECT  61.308 0.139 61.326 0.331 ;
     RECT  42.984 0.139 43.002 0.379 ;
     RECT  41.724 0.235 41.85 0.427 ;
     RECT  42.984 0.379 43.254 0.427 ;
     RECT  50.22 0.187 50.238 0.427 ;
     RECT  60.768 0.331 61.326 0.427 ;
     RECT  74.232 0.139 74.754 0.427 ;
     RECT  75.636 0.379 75.654 0.427 ;
     RECT  47.628 0.139 47.898 0.475 ;
     RECT  60.768 0.427 61.614 0.475 ;
     RECT  62.352 0.139 64.494 0.475 ;
     RECT  73.44 0.427 73.458 0.475 ;
     RECT  74.232 0.427 75.654 0.475 ;
     RECT  41.724 0.427 43.254 0.523 ;
     RECT  44.064 0.139 44.082 0.523 ;
     RECT  47.016 0.475 47.898 0.523 ;
     RECT  49.968 0.427 50.238 0.523 ;
     RECT  51.3 0.139 51.75 0.523 ;
     RECT  60.696 0.475 64.494 0.523 ;
     RECT  65.592 0.187 67.05 0.523 ;
     RECT  76.464 0.283 76.806 0.571 ;
     RECT  46.728 0.523 47.898 0.619 ;
     RECT  52.596 0.235 52.614 1.147 ;
     RECT  76.464 0.571 77.058 1.147 ;
     RECT  52.596 1.147 53.118 1.195 ;
     RECT  41.724 0.523 44.082 1.723 ;
     RECT  46.548 0.619 47.97 1.723 ;
     RECT  49.032 0.571 49.05 1.723 ;
     RECT  49.968 0.523 51.75 1.723 ;
     RECT  52.596 1.195 53.226 1.723 ;
     RECT  56.448 0.235 56.754 1.723 ;
     RECT  60.696 0.523 67.194 1.723 ;
     RECT  68.22 0.187 68.238 1.723 ;
     RECT  73.44 0.475 75.654 1.723 ;
     RECT  76.464 1.147 77.094 1.723 ;
     RECT  41.724 1.723 44.262 1.771 ;
     RECT  46.116 1.723 49.122 1.771 ;
     RECT  49.968 1.723 53.226 1.771 ;
     RECT  73.44 1.723 77.094 1.771 ;
     RECT  45.18 1.723 45.198 1.819 ;
     RECT  46.116 1.771 49.23 1.819 ;
     RECT  55.908 1.723 56.898 1.819 ;
     RECT  49.968 1.771 53.262 1.963 ;
     RECT  40.788 1.723 40.806 2.143 ;
     RECT  45.18 1.819 49.23 2.191 ;
     RECT  49.968 1.963 53.298 2.191 ;
     RECT  60.696 1.723 68.238 2.191 ;
     RECT  73.44 1.771 77.166 2.191 ;
     RECT  78.015 2.143 78.105 2.191 ;
     RECT  45.18 2.191 53.298 2.203 ;
     RECT  40.215 2.143 40.806 2.255 ;
     RECT  41.724 1.771 44.334 2.263 ;
     RECT  45.144 2.203 53.298 2.263 ;
     RECT  41.724 2.263 53.298 2.371 ;
     RECT  2.415 2.143 2.505 2.413 ;
     RECT  7.815 2.143 7.905 2.413 ;
     RECT  13.215 2.143 13.305 2.413 ;
     RECT  18.615 2.143 18.705 2.413 ;
     RECT  24.015 2.143 24.105 2.413 ;
     RECT  29.415 2.143 29.505 2.413 ;
     RECT  34.815 2.143 34.905 2.413 ;
     RECT  72.615 2.143 72.705 2.413 ;
     RECT  73.44 2.191 78.105 2.413 ;
     RECT  83.415 2.143 83.505 2.413 ;
     RECT  88.815 2.143 88.905 2.413 ;
     RECT  94.215 2.143 94.305 2.413 ;
     RECT  99.615 2.143 99.705 2.413 ;
     RECT  105.015 2.143 105.105 2.413 ;
     RECT  110.415 2.143 110.505 2.413 ;
     RECT  115.815 2.143 115.905 2.413 ;
     RECT  121.215 2.143 121.305 2.413 ;
     RECT  126.615 2.143 126.705 2.413 ;
     RECT  41.724 2.371 53.514 2.525 ;
     RECT  41.76 2.525 53.514 2.641 ;
     RECT  55.908 1.819 56.934 2.641 ;
     RECT  60.696 2.191 68.382 2.641 ;
     RECT  41.76 2.641 53.55 2.731 ;
     RECT  60.696 2.641 68.814 2.839 ;
     RECT  41.76 2.731 53.622 2.911 ;
     RECT  55.908 2.641 56.97 2.911 ;
     RECT  55.62 2.911 56.97 3.145 ;
     RECT  41.76 2.911 53.658 3.181 ;
     RECT  55.548 3.145 56.97 3.181 ;
     RECT  58.14 2.191 58.158 3.181 ;
     RECT  72.615 2.413 78.297 3.181 ;
     RECT  55.548 3.181 58.158 3.335 ;
     RECT  41.76 3.181 53.874 3.721 ;
     RECT  41.76 3.721 54.378 4.145 ;
     RECT  41.796 4.145 54.378 4.415 ;
     RECT  41.868 4.415 54.378 4.757 ;
     RECT  55.692 3.335 58.158 5.161 ;
     RECT  59.904 5.575 59.922 5.611 ;
     RECT  59.724 5.611 59.922 5.701 ;
     RECT  60.66 2.839 68.814 5.701 ;
     RECT  59.724 5.701 68.814 5.845 ;
     RECT  55.692 5.161 58.302 5.881 ;
     RECT  69.984 5.809 70.002 5.881 ;
     RECT  71.1 5.845 71.118 5.881 ;
     RECT  72.615 3.181 78.462 5.881 ;
     RECT  69.984 5.881 78.462 6.007 ;
     RECT  69.912 6.007 78.462 6.091 ;
     RECT  79.56 5.881 79.578 6.091 ;
     RECT  55.152 5.881 58.302 6.115 ;
     RECT  42.156 4.757 54.378 6.151 ;
     RECT  55.152 6.115 58.806 6.151 ;
     RECT  59.724 5.845 68.886 6.151 ;
     RECT  69.912 6.091 79.578 6.151 ;
     RECT  42.048 6.151 54.378 6.241 ;
     RECT  55.152 6.151 58.914 6.241 ;
     RECT  59.652 6.151 79.578 6.241 ;
     RECT  42.048 6.241 58.914 6.691 ;
     RECT  59.652 6.241 80.118 6.691 ;
     RECT  42.048 6.691 80.118 6.749 ;
     RECT  59.112 6.749 80.118 6.797 ;
     RECT  42.048 6.749 58.338 6.808 ;
     RECT  41.976 6.808 58.338 6.961 ;
     RECT  41.652 6.961 58.338 7.115 ;
     RECT  59.184 6.797 80.118 7.231 ;
     RECT  42.048 7.115 58.338 7.385 ;
     RECT  59.184 7.231 80.622 7.501 ;
     RECT  81.792 7.627 81.81 7.771 ;
     RECT  83.415 2.413 83.697 7.771 ;
     RECT  59.184 7.501 80.982 7.933 ;
     RECT  81.792 7.771 82.278 7.933 ;
     RECT  59.184 7.933 82.278 8.041 ;
     RECT  83.052 7.771 83.697 8.041 ;
     RECT  42.408 7.385 58.338 8.203 ;
     RECT  59.184 8.041 83.697 8.203 ;
     RECT  42.408 8.203 83.697 8.339 ;
     RECT  42.552 8.339 83.697 8.573 ;
     RECT  42.588 8.573 83.697 8.969 ;
     RECT  40.215 2.255 40.497 9.391 ;
     RECT  40.215 9.391 41.202 9.689 ;
     RECT  42.624 8.969 83.697 10.967 ;
     RECT  42.624 10.967 82.314 11.083 ;
     RECT  42.336 11.083 82.314 11.129 ;
     RECT  42.588 11.129 82.314 11.273 ;
     RECT  42.588 11.273 82.134 11.435 ;
     RECT  41.832 11.821 41.85 11.885 ;
     RECT  42.588 11.435 81.162 11.899 ;
     RECT  82.116 11.435 82.134 11.939 ;
     RECT  42.408 11.899 81.162 11.984 ;
     RECT  42.66 11.984 81.162 12.221 ;
     RECT  42.768 12.221 81.162 12.317 ;
     RECT  43.272 12.317 81.162 12.361 ;
     RECT  43.272 12.361 81.522 12.389 ;
     RECT  43.308 12.389 81.522 12.413 ;
     RECT  40.215 9.689 40.497 12.475 ;
     RECT  41.256 12.361 41.454 12.475 ;
     RECT  43.308 12.413 81.126 12.479 ;
     RECT  43.308 12.479 78.462 12.509 ;
     RECT  40.215 12.475 41.454 12.515 ;
     RECT  41.436 12.515 41.454 12.557 ;
     RECT  41.76 12.865 41.778 13.037 ;
     RECT  42.084 13.051 42.21 13.243 ;
     RECT  43.452 12.509 78.462 13.243 ;
     RECT  79.236 12.479 81.126 13.289 ;
     RECT  79.236 13.289 80.55 13.397 ;
     RECT  42.084 13.243 78.462 13.405 ;
     RECT  79.236 13.397 80.37 13.405 ;
     RECT  42.084 13.405 80.37 13.568 ;
     RECT  42.696 13.568 80.37 13.661 ;
     RECT  42.696 13.661 42.714 14.237 ;
     RECT  43.488 13.661 80.37 14.819 ;
     RECT  43.56 14.819 80.37 14.909 ;
     RECT  43.704 14.909 80.37 15.215 ;
     RECT  43.956 15.215 80.37 15.485 ;
     RECT  45 15.485 80.37 15.827 ;
     RECT  42.768 15.163 42.786 16.109 ;
     RECT  43.956 15.485 43.974 16.259 ;
     RECT  45 15.827 79.758 16.673 ;
     RECT  45 16.673 58.662 16.799 ;
     RECT  45 16.799 58.41 16.807 ;
     RECT  44.964 16.807 58.41 16.871 ;
     RECT  44.964 16.871 57.546 17.041 ;
     RECT  59.652 16.673 79.758 17.077 ;
     RECT  44.928 17.041 57.546 17.117 ;
     RECT  59.652 17.077 80.226 17.213 ;
     RECT  59.652 17.213 75.726 17.339 ;
     RECT  59.652 17.339 75.114 17.405 ;
     RECT  45.144 17.117 57.546 17.411 ;
     RECT  83.415 10.967 83.697 17.419 ;
     RECT  59.652 17.405 75.006 17.447 ;
     RECT  76.572 17.213 80.226 17.581 ;
     RECT  54.144 17.411 54.99 17.609 ;
     RECT  82.98 17.419 83.697 17.659 ;
     RECT  54.792 17.609 54.99 17.681 ;
     RECT  54.792 17.681 54.918 17.717 ;
     RECT  58.392 16.871 58.41 17.753 ;
     RECT  59.652 17.447 74.826 17.761 ;
     RECT  54.792 17.717 54.882 17.879 ;
     RECT  59.616 17.761 74.826 17.879 ;
     RECT  45.144 17.411 53.262 18.023 ;
     RECT  45.144 18.023 52.83 18.149 ;
     RECT  82.548 17.659 83.697 18.149 ;
     RECT  82.908 18.149 83.697 18.173 ;
     RECT  76.572 17.581 80.442 18.301 ;
     RECT  59.652 17.879 74.79 18.491 ;
     RECT  76.212 18.301 80.442 18.571 ;
     RECT  45.144 18.149 52.65 18.599 ;
     RECT  45.144 18.599 52.614 18.797 ;
     RECT  60.516 18.491 74.79 18.841 ;
     RECT  60.516 18.841 75.474 19.111 ;
     RECT  76.212 18.571 80.514 19.111 ;
     RECT  59.652 18.491 59.67 20.191 ;
     RECT  60.516 19.111 80.514 20.191 ;
     RECT  55.764 17.411 57.546 20.219 ;
     RECT  59.652 20.191 80.514 20.623 ;
     RECT  81.936 20.623 81.954 20.695 ;
     RECT  44.208 20.539 44.226 20.731 ;
     RECT  45.144 18.797 52.542 20.731 ;
     RECT  59.652 20.623 80.946 20.731 ;
     RECT  81.828 20.695 81.954 20.731 ;
     RECT  44.208 20.731 52.542 20.849 ;
     RECT  44.208 20.849 44.226 20.885 ;
     RECT  45 20.849 52.542 20.885 ;
     RECT  58.716 20.827 58.734 20.957 ;
     RECT  59.652 20.731 82.062 21.263 ;
     RECT  60.12 21.263 82.062 21.271 ;
     RECT  45.072 20.885 52.542 21.425 ;
     RECT  60.12 21.271 82.134 21.469 ;
     RECT  82.98 18.173 83.697 21.469 ;
     RECT  60.12 21.469 83.697 21.811 ;
     RECT  60.12 21.811 83.754 21.973 ;
     RECT  60.12 21.973 83.826 22.081 ;
     RECT  60.12 22.081 84.078 22.207 ;
     RECT  60.12 22.207 84.15 22.441 ;
     RECT  60.12 22.441 84.222 22.621 ;
     RECT  60.12 22.621 84.258 23.431 ;
     RECT  60.12 23.431 84.294 23.855 ;
     RECT  83.196 23.855 84.294 23.935 ;
     RECT  60.12 23.855 82.278 24.637 ;
     RECT  83.196 23.935 84.33 24.637 ;
     RECT  60.12 24.637 84.33 25.313 ;
     RECT  60.12 25.313 83.697 25.583 ;
     RECT  60.12 25.583 79.542 26.393 ;
     RECT  65.376 26.393 79.542 26.401 ;
     RECT  80.316 25.583 83.697 26.401 ;
     RECT  65.376 26.401 83.697 26.627 ;
     RECT  65.376 26.627 80.982 26.789 ;
     RECT  81.756 26.627 83.697 26.789 ;
     RECT  60.12 26.393 64.602 27.409 ;
     RECT  65.376 26.789 80.946 27.409 ;
     RECT  60.12 27.409 80.946 27.643 ;
     RECT  81.756 26.789 82.17 27.643 ;
     RECT  60.12 27.643 82.17 29.021 ;
     RECT  65.304 29.021 82.17 29.093 ;
     RECT  65.556 29.093 65.934 29.219 ;
     RECT  65.556 29.219 65.79 29.363 ;
     RECT  66.708 29.093 82.17 29.795 ;
     RECT  65.7 29.363 65.79 29.867 ;
     RECT  66.852 29.795 82.17 29.875 ;
     RECT  83.196 26.789 83.697 29.875 ;
     RECT  66.852 29.875 83.697 29.903 ;
     RECT  66.924 29.903 83.697 29.939 ;
     RECT  65.7 29.867 65.718 30.335 ;
     RECT  67.104 29.939 83.697 30.569 ;
     RECT  69.228 30.569 83.697 30.749 ;
     RECT  67.215 30.569 67.95 30.911 ;
     RECT  69.984 30.749 83.697 31.109 ;
     RECT  60.12 29.021 64.386 31.339 ;
     RECT  60.12 31.339 64.962 31.379 ;
     RECT  67.215 30.911 67.497 31.525 ;
     RECT  66.492 31.525 67.497 31.565 ;
     RECT  76.32 31.109 83.697 31.649 ;
     RECT  69.984 31.109 75.474 34.159 ;
     RECT  76.356 31.649 83.697 35.581 ;
     RECT  76.32 35.581 83.697 35.645 ;
     RECT  67.215 31.565 67.497 49.579 ;
     RECT  67.215 49.579 68.022 49.675 ;
     RECT  67.215 49.675 68.382 49.739 ;
     RECT  69.228 30.749 69.246 60.719 ;
     RECT  69.984 34.159 75.546 61.051 ;
     RECT  76.356 35.645 83.697 61.051 ;
     RECT  69.984 61.051 83.697 61.493 ;
     RECT  45.144 21.425 52.542 61.619 ;
     RECT  67.215 49.739 67.497 61.867 ;
     RECT  67.215 61.867 67.59 61.997 ;
     RECT  54.864 17.879 54.882 62.339 ;
     RECT  56.376 20.219 57.546 62.339 ;
     RECT  57.528 62.339 57.546 62.609 ;
     RECT  69.984 61.493 70.002 62.635 ;
     RECT  69.804 62.635 70.002 62.699 ;
     RECT  69.984 62.699 70.002 62.851 ;
     RECT  45.144 61.619 51.822 62.941 ;
     RECT  60.12 31.379 64.386 62.969 ;
     RECT  56.376 62.339 56.697 63.211 ;
     RECT  45.144 62.941 52.038 63.239 ;
     RECT  58.716 63.067 58.734 63.245 ;
     RECT  69.984 62.851 70.11 63.245 ;
     RECT  56.304 63.211 56.697 63.248 ;
     RECT  60.156 62.969 64.386 63.691 ;
     RECT  58.032 63.547 58.23 63.751 ;
     RECT  57.924 63.751 58.23 63.779 ;
     RECT  60.156 63.691 64.674 63.779 ;
     RECT  53.244 63.691 53.262 63.787 ;
     RECT  53.244 63.787 53.37 63.821 ;
     RECT  54.828 63.691 54.846 63.821 ;
     RECT  57.924 63.779 58.05 63.821 ;
     RECT  53.352 63.821 53.37 63.851 ;
     RECT  69.984 63.245 70.002 63.959 ;
     RECT  68.976 63.883 68.994 64.021 ;
     RECT  65.484 63.931 65.502 64.049 ;
     RECT  68.652 64.021 68.994 64.061 ;
     RECT  45.144 63.239 51.75 64.121 ;
     RECT  70.92 61.493 83.697 64.171 ;
     RECT  60.516 63.779 64.674 64.201 ;
     RECT  68.976 64.061 68.994 64.205 ;
     RECT  45.144 64.121 51.297 64.229 ;
     RECT  56.376 63.248 56.697 64.229 ;
     RECT  70.668 64.171 83.697 64.229 ;
     RECT  60.516 64.201 65.358 64.253 ;
     RECT  70.92 64.229 83.697 64.427 ;
     RECT  70.992 64.427 83.697 64.741 ;
     RECT  60.516 64.253 65.178 64.769 ;
     RECT  66.276 64.201 66.294 64.891 ;
     RECT  67.215 61.997 67.497 64.891 ;
     RECT  70.992 64.741 83.79 64.925 ;
     RECT  66.276 64.891 67.497 64.931 ;
     RECT  60.912 64.769 65.178 64.973 ;
     RECT  45.576 64.229 51.297 65.003 ;
     RECT  71.388 64.925 83.79 65.281 ;
     RECT  45.615 65.003 51.297 65.515 ;
     RECT  71.388 65.281 83.826 65.579 ;
     RECT  60.912 64.973 65.034 65.821 ;
     RECT  71.424 65.579 83.826 65.821 ;
     RECT  60.912 65.821 65.214 66.091 ;
     RECT  71.424 65.821 83.898 66.361 ;
     RECT  60.876 66.091 65.214 66.631 ;
     RECT  71.424 66.361 84.114 66.631 ;
     RECT  71.244 66.631 84.114 66.785 ;
     RECT  71.424 66.785 84.114 66.901 ;
     RECT  60.804 66.631 65.43 67.289 ;
     RECT  66.276 64.931 66.294 67.631 ;
     RECT  45.615 65.515 51.534 67.739 ;
     RECT  60.876 67.289 65.358 67.829 ;
     RECT  71.424 66.901 84.474 68.215 ;
     RECT  71.424 68.215 84.51 68.369 ;
     RECT  60.876 67.829 65.214 68.711 ;
     RECT  71.424 68.369 84.474 68.791 ;
     RECT  2.415 2.413 2.697 68.867 ;
     RECT  7.815 2.413 8.097 68.867 ;
     RECT  13.215 2.413 13.497 68.867 ;
     RECT  18.615 2.413 18.897 68.867 ;
     RECT  24.015 2.413 24.297 68.867 ;
     RECT  29.415 2.413 29.697 68.867 ;
     RECT  34.815 2.413 35.097 68.867 ;
     RECT  40.215 12.515 40.497 68.867 ;
     RECT  45.615 67.739 51.297 68.867 ;
     RECT  56.415 64.229 56.697 68.867 ;
     RECT  67.215 64.931 67.497 68.867 ;
     RECT  88.815 2.413 89.097 68.867 ;
     RECT  94.215 2.413 94.497 68.867 ;
     RECT  99.615 2.413 99.897 68.867 ;
     RECT  105.015 2.413 105.297 68.867 ;
     RECT  110.415 2.413 110.697 68.867 ;
     RECT  115.815 2.413 116.097 68.867 ;
     RECT  121.215 2.413 121.497 68.867 ;
     RECT  126.615 2.413 126.897 68.867 ;
     RECT  60.876 68.711 65.178 68.909 ;
     RECT  45.615 68.867 51.105 68.945 ;
     RECT  60.876 68.909 64.998 68.945 ;
     RECT  71.244 68.791 84.474 68.945 ;
     RECT  61.272 68.945 64.71 68.962 ;
     RECT  71.46 68.945 80.406 68.962 ;
     RECT  61.308 68.962 64.71 68.981 ;
     RECT  81.144 68.945 84.474 68.981 ;
     RECT  46.836 68.945 51.105 69.005 ;
     RECT  46.836 69.005 49.014 69.053 ;
     RECT  71.46 68.962 80.37 69.053 ;
     RECT  49.752 69.005 51.105 69.089 ;
     RECT  61.308 68.981 64.494 69.101 ;
     RECT  77.256 69.053 80.37 69.101 ;
     RECT  2.415 68.867 2.505 69.137 ;
     RECT  7.815 68.867 7.905 69.137 ;
     RECT  13.215 68.867 13.305 69.137 ;
     RECT  18.615 68.867 18.705 69.137 ;
     RECT  24.015 68.867 24.105 69.137 ;
     RECT  29.415 68.867 29.505 69.137 ;
     RECT  34.815 68.867 34.905 69.137 ;
     RECT  40.215 68.867 40.305 69.137 ;
     RECT  45.615 68.945 45.705 69.137 ;
     RECT  49.896 69.089 51.105 69.137 ;
     RECT  56.415 68.867 56.505 69.137 ;
     RECT  67.215 68.867 67.305 69.137 ;
     RECT  88.815 68.867 88.905 69.137 ;
     RECT  94.215 68.867 94.305 69.137 ;
     RECT  99.615 68.867 99.705 69.137 ;
     RECT  105.015 68.867 105.105 69.137 ;
     RECT  110.415 68.867 110.505 69.137 ;
     RECT  115.815 68.867 115.905 69.137 ;
     RECT  121.215 68.867 121.305 69.137 ;
     RECT  126.615 68.867 126.705 69.137 ;
     RECT  49.896 69.137 50.778 69.149 ;
     RECT  71.46 69.053 76.374 69.149 ;
     RECT  71.46 69.149 76.338 69.245 ;
     RECT  81.144 68.981 83.934 69.245 ;
     RECT  50.256 69.149 50.778 69.533 ;
     RECT  71.46 69.245 76.302 69.533 ;
     RECT  77.796 69.101 80.37 69.533 ;
     RECT  81.144 69.245 83.754 69.533 ;
     RECT  77.796 69.533 78.822 69.581 ;
     RECT  61.308 69.101 63.81 70.109 ;
     RECT  77.796 69.581 78.786 70.109 ;
     RECT  71.568 69.533 76.302 70.205 ;
     RECT  78.408 70.109 78.786 70.601 ;
     RECT  61.74 70.109 63.81 70.673 ;
     RECT  78.444 70.601 78.786 70.673 ;
     RECT  79.884 69.533 80.37 70.673 ;
     RECT  81.144 69.533 82.422 70.673 ;
     RECT  46.836 69.053 48.978 70.685 ;
     RECT  61.74 70.673 63.774 70.685 ;
     RECT  71.568 70.205 73.242 70.685 ;
     RECT  47.412 70.685 48.978 70.733 ;
     RECT  62.388 70.685 63.774 70.733 ;
     RECT  71.568 70.685 72.594 70.733 ;
     RECT  74.016 70.205 76.302 70.733 ;
     RECT  78.48 70.673 78.786 70.733 ;
     RECT  81.144 70.673 82.17 70.733 ;
     RECT  83.304 69.533 83.754 70.733 ;
     RECT  72.576 70.733 72.594 70.781 ;
     RECT  83.304 70.733 83.322 70.781 ;
     RECT  71.568 70.733 71.586 70.829 ;
     RECT  81.216 70.733 82.17 70.829 ;
     RECT  81.504 70.829 82.17 70.877 ;
     RECT  48.024 70.733 48.978 70.987 ;
     RECT  78.48 70.733 78.642 71.021 ;
     RECT  79.884 70.673 80.226 71.021 ;
     RECT  62.496 70.733 63.774 71.069 ;
     RECT  74.34 70.733 76.302 71.069 ;
     RECT  79.884 71.021 79.902 71.069 ;
     RECT  48.024 70.987 49.086 71.117 ;
     RECT  50.76 69.533 50.778 71.117 ;
     RECT  62.496 71.069 63.594 71.117 ;
     RECT  74.34 71.069 75.978 71.117 ;
     RECT  78.552 71.021 78.642 71.117 ;
     RECT  81.756 70.877 82.17 71.117 ;
     RECT  78.552 71.117 78.57 71.165 ;
    LAYER M4 ;
     RECT  2.408 2.148 2.512 69.132 ;
     RECT  2.512 2.418 2.704 68.862 ;
     RECT  7.808 2.148 7.912 69.132 ;
     RECT  7.912 2.418 8.104 68.862 ;
     RECT  13.208 2.148 13.312 69.132 ;
     RECT  13.312 2.418 13.504 68.862 ;
     RECT  18.608 2.148 18.712 69.132 ;
     RECT  18.712 2.418 18.904 68.862 ;
     RECT  24.008 2.148 24.112 69.132 ;
     RECT  24.112 2.418 24.304 68.862 ;
     RECT  29.408 2.148 29.512 69.132 ;
     RECT  29.512 2.418 29.704 68.862 ;
     RECT  34.808 2.148 34.912 69.132 ;
     RECT  34.912 2.418 35.104 68.862 ;
     RECT  40.208 2.148 40.312 69.132 ;
     RECT  40.312 2.148 40.504 68.862 ;
     RECT  40.693 1.728 40.817 1.752 ;
     RECT  40.504 9.648 41.219 9.672 ;
     RECT  40.504 12.48 41.749 12.552 ;
     RECT  41.749 1.584 41.785 1.608 ;
     RECT  41.713 0.24 41.821 0.264 ;
     RECT  41.749 12.48 41.821 13.032 ;
     RECT  41.785 1.584 42.073 1.704 ;
     RECT  41.821 11.856 42.073 13.032 ;
     RECT  41.821 0.144 42.284 0.264 ;
     RECT  40.504 10.848 42.325 10.872 ;
     RECT  42.073 11.856 42.325 13.56 ;
     RECT  42.284 0.144 42.469 0.552 ;
     RECT  42.277 3.408 42.508 3.432 ;
     RECT  42.421 15.696 42.517 15.72 ;
     RECT  42.469 0.144 42.553 0.6 ;
     RECT  42.073 1.584 42.563 2.28 ;
     RECT  42.563 1.728 42.659 2.28 ;
     RECT  42.325 10.848 42.661 13.56 ;
     RECT  42.661 10.848 42.668 14.088 ;
     RECT  42.508 3.408 42.677 3.48 ;
     RECT  42.659 1.728 42.707 2.184 ;
     RECT  41.965 6.816 42.709 6.84 ;
     RECT  42.668 10.848 42.709 14.232 ;
     RECT  42.517 15.696 42.709 16.296 ;
     RECT  42.709 6.816 42.755 7.656 ;
     RECT  42.709 10.848 42.755 16.296 ;
     RECT  42.721 9.456 42.764 9.48 ;
     RECT  42.755 15.168 42.797 16.296 ;
     RECT  42.757 4.704 42.829 4.728 ;
     RECT  42.764 9.216 42.851 9.48 ;
     RECT  42.829 4.656 42.901 4.728 ;
     RECT  42.755 6.864 43.009 7.656 ;
     RECT  43.009 6.864 43.093 7.992 ;
     RECT  43.093 6.864 43.235 7.656 ;
     RECT  42.901 4.56 43.261 4.728 ;
     RECT  43.235 7.2 43.337 7.656 ;
     RECT  43.261 4.56 43.429 4.776 ;
     RECT  43.429 4.56 43.441 5.16 ;
     RECT  42.755 10.848 43.549 13.656 ;
     RECT  42.677 3.408 43.693 3.528 ;
     RECT  43.441 4.56 43.693 5.256 ;
     RECT  43.693 3.408 43.697 5.256 ;
     RECT  43.337 7.2 43.697 7.224 ;
     RECT  43.697 3.984 43.769 5.256 ;
     RECT  43.549 10.56 43.868 13.656 ;
     RECT  43.868 10.56 44.089 14.088 ;
     RECT  42.553 0.144 44.093 0.552 ;
     RECT  44.093 0.528 44.147 0.552 ;
     RECT  42.707 1.728 44.156 1.848 ;
     RECT  44.089 10.464 44.156 14.088 ;
     RECT  42.797 15.264 44.156 16.296 ;
     RECT  42.851 9.456 44.161 9.48 ;
     RECT  44.156 10.464 44.161 16.296 ;
     RECT  40.504 20.832 44.197 20.856 ;
     RECT  44.156 1.728 44.243 2.28 ;
     RECT  44.161 9.456 44.243 16.296 ;
     RECT  44.197 20.544 44.281 20.856 ;
     RECT  44.243 9.456 44.3 10.584 ;
     RECT  43.769 3.984 44.345 4.584 ;
     RECT  44.3 9.072 44.387 10.584 ;
     RECT  44.701 6.816 44.732 6.84 ;
     RECT  44.732 6.816 44.809 7.608 ;
     RECT  44.809 6.72 44.828 7.608 ;
     RECT  44.828 6.72 44.869 7.944 ;
     RECT  44.243 11.616 44.917 16.296 ;
     RECT  44.281 20.832 45.061 20.856 ;
     RECT  44.243 1.728 45.205 2.232 ;
     RECT  44.387 9.648 45.397 10.584 ;
     RECT  44.917 11.616 45.397 17.112 ;
     RECT  45.205 1.728 45.608 2.28 ;
     RECT  45.313 3.984 45.608 4.008 ;
     RECT  45.205 5.136 45.608 5.16 ;
     RECT  44.869 6.72 45.608 8.472 ;
     RECT  45.397 9.648 45.608 17.112 ;
     RECT  45.061 20.832 45.608 21.144 ;
     RECT  45.565 64.368 45.608 64.392 ;
     RECT  45.608 1.728 45.712 69.132 ;
     RECT  45.712 1.728 45.904 68.862 ;
     RECT  45.904 20.544 46.019 20.856 ;
     RECT  45.904 6.432 46.211 16.872 ;
     RECT  46.537 0.624 46.717 0.648 ;
     RECT  46.717 0.528 46.741 0.648 ;
     RECT  46.741 0.528 46.828 0.696 ;
     RECT  46.828 0.528 47.005 0.648 ;
     RECT  45.904 1.728 47.036 2.04 ;
     RECT  46.825 70.656 47.041 70.68 ;
     RECT  45.904 68.256 47.149 68.76 ;
     RECT  45.904 64.944 47.153 64.968 ;
     RECT  47.149 68.256 47.293 69.528 ;
     RECT  47.041 70.56 47.401 70.68 ;
     RECT  45.904 3.408 47.537 4.008 ;
     RECT  46.933 5.136 47.537 5.16 ;
     RECT  47.005 0.48 47.573 0.648 ;
     RECT  47.293 68.208 47.581 69.528 ;
     RECT  47.401 70.56 47.581 70.728 ;
     RECT  46.211 6.528 47.585 16.872 ;
     RECT  45.904 62.976 47.617 63 ;
     RECT  47.537 3.408 47.729 5.16 ;
     RECT  47.581 68.208 47.747 70.728 ;
     RECT  47.729 5.136 47.761 5.16 ;
     RECT  47.761 5.136 47.845 5.304 ;
     RECT  47.585 8.112 47.873 16.872 ;
     RECT  47.747 68.256 47.893 70.728 ;
     RECT  47.573 0.144 47.909 0.648 ;
     RECT  47.909 0.624 47.981 0.648 ;
     RECT  47.617 62.16 48.121 63 ;
     RECT  47.585 6.528 48.227 6.84 ;
     RECT  47.893 68.256 48.269 71.112 ;
     RECT  48.227 6.528 48.301 6.552 ;
     RECT  47.729 3.408 48.313 4.104 ;
     RECT  48.121 61.536 48.373 63 ;
     RECT  48.325 66.384 48.553 66.408 ;
     RECT  47.845 5.136 48.593 5.16 ;
     RECT  48.553 66.384 48.593 66.744 ;
     RECT  48.269 68.4 48.601 71.112 ;
     RECT  47.873 8.112 48.629 13.8 ;
     RECT  48.373 61.536 48.805 63.288 ;
     RECT  48.301 6.24 48.841 6.552 ;
     RECT  48.593 66.72 48.881 66.744 ;
     RECT  48.601 68.928 48.881 71.112 ;
     RECT  48.805 61.008 48.917 63.768 ;
     RECT  47.036 1.728 48.947 2.28 ;
     RECT  48.917 61.536 48.995 63.768 ;
     RECT  48.313 3.408 49.025 4.008 ;
     RECT  47.873 14.832 49.057 16.872 ;
     RECT  48.977 0.576 49.061 0.6 ;
     RECT  48.995 62.16 49.093 63.768 ;
     RECT  48.877 64.944 49.093 64.968 ;
     RECT  48.881 70.992 49.097 71.112 ;
     RECT  48.947 1.728 49.133 1.8 ;
     RECT  48.841 5.472 49.169 6.552 ;
     RECT  49.025 3.984 49.177 4.008 ;
     RECT  49.133 1.776 49.241 1.8 ;
     RECT  48.629 8.256 49.381 13.8 ;
     RECT  49.057 14.784 49.381 16.872 ;
     RECT  48.881 68.928 49.421 69.528 ;
     RECT  49.169 6.528 49.457 6.552 ;
     RECT  49.421 68.976 49.493 69.528 ;
     RECT  49.093 62.16 49.529 64.968 ;
     RECT  49.529 62.736 49.669 64.968 ;
     RECT  49.169 5.472 49.741 5.496 ;
     RECT  49.381 8.256 49.813 16.872 ;
     RECT  49.669 62.736 49.817 65.592 ;
     RECT  49.453 67.536 49.817 67.56 ;
     RECT  49.493 69.12 49.925 69.528 ;
     RECT  49.741 5.136 49.957 5.496 ;
     RECT  50.053 2.832 50.065 2.856 ;
     RECT  49.957 0.432 50.137 0.456 ;
     RECT  50.137 0.432 50.209 0.552 ;
     RECT  50.065 2.16 50.209 2.856 ;
     RECT  50.209 2.16 50.245 3 ;
     RECT  49.925 69.168 50.285 69.528 ;
     RECT  50.209 0.192 50.293 0.552 ;
     RECT  50.245 1.728 50.293 3.528 ;
     RECT  49.957 4.512 50.293 5.496 ;
     RECT  50.293 0.192 50.341 0.648 ;
     RECT  50.285 69.168 50.501 69.192 ;
     RECT  49.813 6.864 50.713 16.872 ;
     RECT  50.341 0.192 50.723 0.744 ;
     RECT  50.293 1.728 50.78 5.496 ;
     RECT  49.097 71.088 50.789 71.112 ;
     RECT  50.78 1.68 51.008 5.496 ;
     RECT  50.713 6.576 51.008 16.872 ;
     RECT  46.019 20.832 51.008 20.856 ;
     RECT  49.817 63.6 51.008 65.592 ;
     RECT  50.723 0.192 51.107 0.648 ;
     RECT  51.008 1.68 51.112 69.132 ;
     RECT  51.107 0.192 51.155 0.552 ;
     RECT  51.155 0.192 51.289 0.408 ;
     RECT  51.112 1.68 51.304 68.862 ;
     RECT  51.304 1.68 51.365 5.496 ;
     RECT  51.365 1.68 51.443 4.104 ;
     RECT  51.443 1.728 51.491 4.104 ;
     RECT  51.304 6.672 51.58 17.832 ;
     RECT  51.289 0.144 51.782 0.408 ;
     RECT  51.782 0.24 51.827 0.408 ;
     RECT  51.491 1.728 51.905 2.712 ;
     RECT  51.491 3.984 51.913 4.104 ;
     RECT  51.905 1.728 52.085 1.848 ;
     RECT  51.365 5.472 52.163 5.496 ;
     RECT  51.58 6.672 52.373 17.112 ;
     RECT  51.827 0.24 52.625 0.264 ;
     RECT  52.373 7.392 52.945 17.112 ;
     RECT  51.913 3.984 52.979 4.008 ;
     RECT  52.801 6.24 52.979 6.264 ;
     RECT  52.945 7.392 53.021 17.16 ;
     RECT  52.085 1.728 53.029 1.752 ;
     RECT  53.029 1.152 53.053 1.752 ;
     RECT  53.053 1.152 53.129 1.896 ;
     RECT  53.129 1.2 53.237 1.896 ;
     RECT  53.237 1.776 53.269 1.896 ;
     RECT  53.269 1.776 53.273 1.992 ;
     RECT  53.273 1.968 53.353 1.992 ;
     RECT  53.377 5.664 53.461 5.688 ;
     RECT  53.021 7.92 54.217 17.16 ;
     RECT  53.989 6.816 54.317 6.84 ;
     RECT  54.217 10.656 54.637 17.16 ;
     RECT  54.637 10.656 55.109 17.208 ;
     RECT  54.217 7.92 55.249 9.432 ;
     RECT  55.249 7.392 55.381 9.432 ;
     RECT  55.381 7.392 55.429 9.576 ;
     RECT  55.429 7.344 55.573 9.576 ;
     RECT  55.109 10.656 55.573 16.872 ;
     RECT  55.573 7.344 55.765 16.872 ;
     RECT  55.765 6.816 56.257 16.872 ;
     RECT  55.897 1.728 56.293 1.752 ;
     RECT  56.293 1.728 56.408 2.04 ;
     RECT  56.257 6.816 56.408 16.92 ;
     RECT  51.304 20.832 56.408 20.856 ;
     RECT  51.304 63.216 56.408 63.816 ;
     RECT  56.437 0.144 56.485 0.168 ;
     RECT  56.408 1.728 56.512 69.132 ;
     RECT  56.485 0.144 56.521 0.264 ;
     RECT  56.512 1.728 56.704 68.862 ;
     RECT  56.521 0.24 56.765 0.264 ;
     RECT  56.704 1.728 56.873 1.896 ;
     RECT  56.873 1.728 56.909 1.848 ;
     RECT  56.909 1.824 56.945 1.848 ;
     RECT  56.704 20.832 58.705 20.856 ;
     RECT  56.704 63.216 58.705 63.816 ;
     RECT  58.705 20.832 58.745 20.952 ;
     RECT  56.704 6.816 58.777 16.92 ;
     RECT  58.777 6.144 58.787 16.92 ;
     RECT  58.787 6.144 58.979 12.744 ;
     RECT  58.979 6.768 59.821 12.744 ;
     RECT  58.787 13.872 59.821 16.92 ;
     RECT  59.797 18.096 59.884 18.12 ;
     RECT  59.845 5.616 59.933 5.64 ;
     RECT  59.821 6.768 60.325 16.92 ;
     RECT  60.685 0.48 60.757 0.504 ;
     RECT  60.325 5.712 60.757 16.92 ;
     RECT  60.86 2.256 60.865 2.28 ;
     RECT  58.705 63.072 60.937 63.816 ;
     RECT  60.757 5.712 61.004 17.16 ;
     RECT  60.757 0.336 61.261 0.504 ;
     RECT  61.004 5.712 61.285 17.592 ;
     RECT  61.261 0.336 61.297 0.552 ;
     RECT  60.865 1.68 61.333 2.28 ;
     RECT  61.405 68.736 61.441 68.76 ;
     RECT  61.297 70.08 61.441 70.104 ;
     RECT  61.333 1.68 61.477 2.76 ;
     RECT  61.477 1.68 61.513 3.672 ;
     RECT  61.285 5.136 61.513 17.592 ;
     RECT  60.937 63.072 61.525 63.864 ;
     RECT  58.745 20.928 61.549 20.952 ;
     RECT  61.297 0.144 61.669 0.552 ;
     RECT  61.513 1.68 61.669 17.592 ;
     RECT  61.369 61.632 61.669 61.656 ;
     RECT  61.669 1.68 61.729 18.168 ;
     RECT  61.441 68.736 61.729 70.104 ;
     RECT  61.729 1.68 61.808 18.216 ;
     RECT  61.549 20.928 61.808 21 ;
     RECT  60.937 23.376 61.808 23.4 ;
     RECT  61.56 25.824 61.808 25.848 ;
     RECT  61.669 61.104 61.808 61.656 ;
     RECT  61.525 63.024 61.808 63.864 ;
     RECT  60.937 64.944 61.808 64.968 ;
     RECT  61.729 68.736 61.808 70.68 ;
     RECT  61.808 1.68 62.104 70.68 ;
     RECT  61.669 0.144 62.269 0.648 ;
     RECT  62.104 1.68 62.269 18.888 ;
     RECT  62.104 68.736 62.291 70.68 ;
     RECT  62.291 68.928 62.377 70.68 ;
     RECT  62.377 68.928 62.389 70.728 ;
     RECT  62.269 0.144 62.417 18.888 ;
     RECT  62.389 68.928 62.425 71.112 ;
     RECT  62.104 20.4 62.497 22.872 ;
     RECT  62.417 0.144 62.531 2.232 ;
     RECT  62.531 1.728 62.561 2.232 ;
     RECT  62.417 3.216 62.633 18.888 ;
     RECT  62.104 67.248 62.716 67.272 ;
     RECT  62.633 3.216 62.741 18.648 ;
     RECT  62.531 0.144 62.773 0.744 ;
     RECT  62.773 0.096 62.819 0.744 ;
     RECT  62.819 0.096 62.857 0.6 ;
     RECT  62.104 66.096 63.148 66.12 ;
     RECT  62.104 61.44 63.157 61.464 ;
     RECT  62.104 62.688 63.157 64.392 ;
     RECT  63.157 61.44 63.203 64.392 ;
     RECT  63.203 62.4 63.245 64.392 ;
     RECT  62.425 68.976 63.245 71.112 ;
     RECT  63.245 62.688 63.251 64.392 ;
     RECT  63.251 63.072 63.299 64.392 ;
     RECT  62.497 20.4 63.317 22.68 ;
     RECT  63.253 65.376 63.34 65.4 ;
     RECT  63.299 63.072 63.443 63.912 ;
     RECT  63.245 68.976 63.461 69.672 ;
     RECT  62.857 0.144 63.469 0.6 ;
     RECT  63.317 21.264 63.493 22.68 ;
     RECT  63.461 68.976 63.529 69.576 ;
     RECT  63.245 71.04 63.605 71.112 ;
     RECT  62.561 1.728 63.673 1.896 ;
     RECT  63.529 68.88 63.749 69.576 ;
     RECT  63.541 66.768 63.785 66.792 ;
     RECT  63.605 71.04 63.785 71.064 ;
     RECT  62.104 26.928 64.001 26.952 ;
     RECT  63.749 68.88 64.037 69.096 ;
     RECT  64.037 69.024 64.145 69.096 ;
     RECT  62.741 3.408 64.177 18.648 ;
     RECT  63.493 21.264 64.181 23.4 ;
     RECT  64.177 3.408 64.285 18.84 ;
     RECT  64.181 22.224 64.285 23.4 ;
     RECT  63.443 63.216 64.321 63.912 ;
     RECT  64.033 64.896 64.321 64.92 ;
     RECT  64.285 3.408 64.364 19.272 ;
     RECT  64.321 20.64 64.364 20.808 ;
     RECT  64.285 22.224 64.364 23.448 ;
     RECT  64.364 22.224 64.451 24.36 ;
     RECT  63.673 1.728 64.501 1.944 ;
     RECT  64.145 69.072 64.505 69.096 ;
     RECT  63.469 0.144 64.645 0.552 ;
     RECT  64.501 1.728 64.645 2.184 ;
     RECT  64.451 23.808 64.691 23.832 ;
     RECT  64.465 24.864 64.691 24.888 ;
     RECT  64.645 0.144 64.739 2.184 ;
     RECT  64.739 1.632 64.897 2.184 ;
     RECT  63.817 67.824 64.901 67.848 ;
     RECT  64.364 3.408 64.931 20.808 ;
     RECT  64.069 27.888 64.969 27.912 ;
     RECT  64.453 31.344 64.973 31.368 ;
     RECT  64.897 1.632 65.027 2.28 ;
     RECT  65.027 1.632 65.075 2.184 ;
     RECT  65.075 1.632 65.123 2.088 ;
     RECT  64.321 63.216 65.149 64.92 ;
     RECT  64.451 22.224 65.333 22.824 ;
     RECT  64.931 20.592 65.437 20.808 ;
     RECT  64.969 27.888 65.473 28.584 ;
     RECT  64.931 3.408 65.509 19.272 ;
     RECT  65.333 22.608 65.509 22.824 ;
     RECT  65.509 3.216 65.651 19.272 ;
     RECT  65.651 3.216 65.699 3.672 ;
     RECT  65.509 22.608 65.873 22.872 ;
     RECT  65.473 27.888 65.945 29.064 ;
     RECT  65.437 20.592 66.053 21.528 ;
     RECT  65.941 25.296 66.085 25.32 ;
     RECT  66.085 25.296 66.193 25.464 ;
     RECT  66.053 21.12 66.197 21.528 ;
     RECT  64.739 0.144 66.229 0.6 ;
     RECT  65.123 1.632 66.229 1.848 ;
     RECT  65.651 5.136 66.229 19.272 ;
     RECT  66.229 0.144 66.371 1.848 ;
     RECT  66.371 1.68 66.62 1.848 ;
     RECT  65.699 3.408 66.757 3.672 ;
     RECT  66.62 1.68 66.805 1.944 ;
     RECT  66.757 3.408 66.805 4.008 ;
     RECT  65.945 27.888 66.949 27.912 ;
     RECT  66.805 1.68 67.043 4.104 ;
     RECT  66.193 25.104 67.129 25.464 ;
     RECT  66.197 21.216 67.165 21.528 ;
     RECT  65.945 28.944 67.201 29.064 ;
     RECT  67.043 1.728 67.208 4.104 ;
     RECT  66.229 5.136 67.208 19.608 ;
     RECT  67.165 21.168 67.208 21.528 ;
     RECT  65.873 22.848 67.208 22.872 ;
     RECT  67.129 24.624 67.208 25.464 ;
     RECT  66.949 27.408 67.208 27.912 ;
     RECT  67.201 28.944 67.208 29.592 ;
     RECT  66.476 31.536 67.208 31.56 ;
     RECT  66.517 49.584 67.208 49.608 ;
     RECT  64.933 61.968 67.208 61.992 ;
     RECT  65.149 63.216 67.208 64.968 ;
     RECT  66.371 0.144 67.235 0.552 ;
     RECT  67.208 1.728 67.312 69.132 ;
     RECT  67.312 1.728 67.504 68.862 ;
     RECT  67.504 61.872 67.601 61.992 ;
     RECT  67.235 0.144 67.619 0.36 ;
     RECT  67.504 3.408 67.637 5.256 ;
     RECT  67.619 0.192 67.667 0.36 ;
     RECT  67.504 1.728 67.709 1.896 ;
     RECT  67.667 0.192 67.715 0.264 ;
     RECT  67.637 3.408 67.715 5.16 ;
     RECT  67.709 1.728 67.781 1.752 ;
     RECT  67.504 29.04 67.781 29.064 ;
     RECT  67.715 4.848 67.853 5.16 ;
     RECT  67.504 6.24 67.889 21.192 ;
     RECT  67.715 3.408 67.925 3.432 ;
     RECT  67.889 6.24 67.925 20.952 ;
     RECT  67.504 26.16 67.961 27.432 ;
     RECT  67.504 49.584 68.033 49.704 ;
     RECT  67.853 5.136 68.069 5.16 ;
     RECT  67.715 0.192 68.249 0.216 ;
     RECT  67.961 26.16 68.357 27.24 ;
     RECT  68.033 49.68 68.428 49.704 ;
     RECT  68.357 26.832 68.861 27.24 ;
     RECT  67.925 6.24 68.897 19.608 ;
     RECT  68.897 6.672 69.073 19.608 ;
     RECT  69.073 6.672 69.221 19.752 ;
     RECT  69.221 8.736 69.473 19.752 ;
     RECT  67.925 20.928 69.493 20.952 ;
     RECT  69.473 8.736 69.58 19.272 ;
     RECT  67.601 61.872 69.793 61.896 ;
     RECT  67.504 63.216 69.793 64.92 ;
     RECT  69.493 20.928 69.869 21.144 ;
     RECT  69.901 22.32 70.045 22.344 ;
     RECT  70.045 22.32 70.081 22.488 ;
     RECT  69.58 19.248 70.163 19.272 ;
     RECT  68.861 27.168 70.225 27.24 ;
     RECT  69.221 6.672 70.357 7.608 ;
     RECT  69.58 8.736 70.357 18.216 ;
     RECT  69.869 21.12 70.373 21.144 ;
     RECT  70.357 6.672 70.412 18.216 ;
     RECT  70.081 22.32 70.517 22.776 ;
     RECT  69.937 30.528 70.589 30.552 ;
     RECT  67.504 24.624 70.693 24.648 ;
     RECT  70.693 24.624 70.729 25.464 ;
     RECT  70.225 26.736 70.765 27.24 ;
     RECT  70.765 26.544 70.945 27.24 ;
     RECT  69.793 61.872 71.021 64.92 ;
     RECT  70.945 26.544 71.029 27.384 ;
     RECT  70.412 6.432 71.057 18.216 ;
     RECT  70.729 24.624 71.057 25.56 ;
     RECT  71.057 6.432 71.089 17.976 ;
     RECT  71.029 26.544 71.165 26.568 ;
     RECT  71.057 24.624 71.269 25.464 ;
     RECT  71.089 5.952 71.281 17.976 ;
     RECT  71.269 23.904 71.345 25.464 ;
     RECT  71.021 61.872 71.525 64.872 ;
     RECT  70.517 22.32 71.557 22.632 ;
     RECT  71.525 61.872 71.593 64.488 ;
     RECT  71.345 23.904 71.773 25.272 ;
     RECT  71.557 22.32 71.845 22.776 ;
     RECT  71.773 23.856 71.845 25.272 ;
     RECT  71.873 19.872 71.893 19.896 ;
     RECT  71.893 19.584 72.037 19.896 ;
     RECT  71.953 30.384 72.092 30.408 ;
     RECT  72.092 30 72.097 30.408 ;
     RECT  71.557 70.8 72.097 70.824 ;
     RECT  71.281 8.976 72.169 17.976 ;
     RECT  71.449 69.504 72.169 69.528 ;
     RECT  72.097 70.704 72.169 70.824 ;
     RECT  71.485 67.824 72.241 67.848 ;
     RECT  71.281 5.952 72.277 7.944 ;
     RECT  72.169 8.976 72.277 18.504 ;
     RECT  72.061 27.696 72.493 27.72 ;
     RECT  72.277 5.952 72.608 18.504 ;
     RECT  72.037 19.584 72.608 20.184 ;
     RECT  71.845 22.32 72.608 25.272 ;
     RECT  72.493 27.696 72.608 27.96 ;
     RECT  72.133 28.944 72.608 28.968 ;
     RECT  72.097 30 72.608 30.792 ;
     RECT  71.989 31.92 72.608 31.944 ;
     RECT  67.504 34.368 72.608 34.392 ;
     RECT  71.948 60.384 72.608 60.408 ;
     RECT  71.593 61.536 72.608 64.488 ;
     RECT  72.241 67.824 72.608 67.944 ;
     RECT  72.169 69.504 72.608 70.824 ;
     RECT  72.608 2.148 72.712 70.824 ;
     RECT  72.712 2.418 72.904 70.824 ;
     RECT  72.904 6.672 72.965 18.888 ;
     RECT  72.904 19.968 73.001 20.184 ;
     RECT  72.965 6.672 73.043 7.032 ;
     RECT  72.904 60.384 73.043 62.616 ;
     RECT  73.043 6.816 73.073 7.032 ;
     RECT  73.043 60.48 73.117 62.616 ;
     RECT  72.904 64.032 73.189 65.544 ;
     RECT  72.904 66.624 73.189 70.824 ;
     RECT  72.904 35.904 73.225 35.928 ;
     RECT  73.117 60.528 73.361 62.616 ;
     RECT  72.904 26.88 73.397 28.968 ;
     RECT  73.189 66.624 73.433 67.944 ;
     RECT  73.073 6.816 73.441 6.84 ;
     RECT  73.189 64.032 73.468 65.016 ;
     RECT  73.433 66.816 73.475 67.944 ;
     RECT  73.429 0.432 73.501 0.456 ;
     RECT  72.904 22.128 73.516 24.936 ;
     RECT  72.904 30.528 73.523 31.56 ;
     RECT  73.397 26.88 73.541 26.904 ;
     RECT  73.523 30.528 73.619 30.696 ;
     RECT  73.397 28.56 73.66 28.968 ;
     RECT  72.904 34.608 73.693 34.776 ;
     RECT  73.66 28.56 73.865 28.584 ;
     RECT  72.904 49.008 73.973 49.032 ;
     RECT  73.516 22.608 74.041 24.936 ;
     RECT  74.041 22.608 74.045 24.984 ;
     RECT  73.501 0.432 74.069 0.552 ;
     RECT  73.361 61.008 74.081 62.616 ;
     RECT  73.189 68.976 74.101 70.824 ;
     RECT  73.897 1.68 74.113 1.704 ;
     RECT  72.965 8.16 74.113 18.888 ;
     RECT  73.001 19.968 74.113 19.992 ;
     RECT  74.113 8.16 74.117 19.992 ;
     RECT  74.113 1.68 74.185 2.232 ;
     RECT  74.069 0.432 74.221 0.648 ;
     RECT  74.045 22.608 74.225 23.64 ;
     RECT  74.204 33.504 74.291 33.528 ;
     RECT  73.693 34.608 74.291 34.632 ;
     RECT  74.101 68.976 74.291 71.112 ;
     RECT  74.117 19.392 74.297 19.992 ;
     RECT  74.117 8.16 74.329 17.976 ;
     RECT  74.252 49.44 74.339 49.464 ;
     RECT  74.297 19.776 74.387 19.992 ;
     RECT  74.081 61.056 74.389 62.616 ;
     RECT  73.468 64.032 74.389 64.968 ;
     RECT  73.475 67.248 74.389 67.944 ;
     RECT  74.329 7.824 74.396 17.976 ;
     RECT  74.396 6.72 74.437 6.744 ;
     RECT  74.396 7.776 74.437 17.976 ;
     RECT  74.225 22.608 74.441 22.872 ;
     RECT  74.437 6.72 74.483 17.976 ;
     RECT  74.185 1.68 74.509 2.952 ;
     RECT  74.113 3.984 74.509 4.008 ;
     RECT  74.483 6.816 74.513 17.976 ;
     RECT  74.389 61.056 74.513 64.968 ;
     RECT  74.441 22.608 74.581 22.776 ;
     RECT  74.513 6.816 74.657 17.64 ;
     RECT  72.904 58.704 74.657 58.728 ;
     RECT  74.387 19.776 74.693 19.8 ;
     RECT  74.293 35.616 74.801 35.64 ;
     RECT  74.509 1.68 74.837 4.008 ;
     RECT  74.581 27.888 74.869 27.912 ;
     RECT  74.869 66.144 74.905 66.168 ;
     RECT  74.389 67.248 74.905 68.424 ;
     RECT  74.221 0.096 74.963 0.648 ;
     RECT  74.905 66.144 75.053 68.424 ;
     RECT  74.963 0.096 75.059 0.552 ;
     RECT  74.581 22.272 75.089 22.776 ;
     RECT  73.619 30.672 75.157 30.696 ;
     RECT  74.837 1.68 75.277 3.432 ;
     RECT  75.053 67.68 75.341 68.424 ;
     RECT  74.291 69.456 75.349 71.112 ;
     RECT  75.157 30.672 75.374 30.888 ;
     RECT  74.045 24.624 75.377 24.984 ;
     RECT  75.277 1.68 75.395 3.144 ;
     RECT  75.059 0.384 75.443 0.552 ;
     RECT  74.869 27.888 75.548 28.536 ;
     RECT  75.541 29.616 75.548 29.64 ;
     RECT  75.548 27.888 75.557 29.64 ;
     RECT  75.374 30.672 75.587 30.84 ;
     RECT  74.657 6.816 75.617 17.448 ;
     RECT  75.395 1.68 75.635 1.848 ;
     RECT  75.557 28.464 75.635 29.64 ;
     RECT  75.349 68.976 75.635 71.112 ;
     RECT  74.869 4.56 75.661 4.584 ;
     RECT  75.377 24.912 75.661 24.984 ;
     RECT  74.513 61.056 75.769 64.68 ;
     RECT  75.661 4.56 75.805 5.16 ;
     RECT  75.617 6.288 75.805 17.448 ;
     RECT  75.443 0.384 75.875 0.504 ;
     RECT  75.661 24.912 75.917 25.032 ;
     RECT  75.829 30.144 75.917 30.264 ;
     RECT  75.875 0.384 75.923 0.408 ;
     RECT  75.917 30.24 75.925 30.264 ;
     RECT  75.635 28.464 75.989 29.112 ;
     RECT  75.635 70.704 75.989 71.112 ;
     RECT  75.805 4.56 76.019 17.448 ;
     RECT  75.917 24.912 76.061 24.936 ;
     RECT  75.989 70.704 76.067 71.064 ;
     RECT  75.053 66.144 76.069 66.696 ;
     RECT  75.341 67.68 76.069 67.848 ;
     RECT  75.769 61.056 76.097 65.112 ;
     RECT  76.069 66.144 76.157 67.848 ;
     RECT  76.019 4.56 76.277 7.416 ;
     RECT  75.841 22.848 76.277 22.872 ;
     RECT  75.635 68.976 76.277 69.528 ;
     RECT  76.067 71.04 76.313 71.064 ;
     RECT  76.277 4.56 76.321 4.584 ;
     RECT  76.277 68.976 76.349 69.24 ;
     RECT  76.268 35.616 76.355 35.64 ;
     RECT  72.904 42.144 76.355 42.168 ;
     RECT  75.395 2.88 76.373 3.144 ;
     RECT  76.349 68.976 76.385 69.144 ;
     RECT  76.373 2.832 76.417 3.144 ;
     RECT  76.277 5.904 76.421 7.416 ;
     RECT  76.019 8.4 76.451 17.448 ;
     RECT  76.309 22.08 76.489 22.104 ;
     RECT  75.635 1.728 76.508 1.848 ;
     RECT  76.417 2.832 76.508 4.008 ;
     RECT  76.097 61.872 76.525 65.112 ;
     RECT  76.157 66.096 76.525 67.848 ;
     RECT  76.385 68.976 76.529 69.096 ;
     RECT  76.489 21.648 76.573 22.104 ;
     RECT  76.525 61.872 76.597 67.848 ;
     RECT  76.421 5.904 76.643 6.888 ;
     RECT  76.597 61.872 76.681 67.896 ;
     RECT  76.021 0.144 76.709 0.312 ;
     RECT  76.508 1.728 76.745 4.008 ;
     RECT  75.989 29.088 76.781 29.112 ;
     RECT  76.529 69.024 76.781 69.096 ;
     RECT  76.709 0.288 76.817 0.312 ;
     RECT  76.681 61.872 76.853 67.848 ;
     RECT  76.849 27.408 76.993 27.432 ;
     RECT  76.745 1.728 76.997 3.48 ;
     RECT  76.993 27.408 77.033 28.68 ;
     RECT  76.981 0.576 77.065 0.6 ;
     RECT  76.997 1.728 77.065 3.432 ;
     RECT  77.065 0.576 77.069 3.432 ;
     RECT  77.065 25.104 77.101 25.128 ;
     RECT  77.069 1.152 77.149 3.432 ;
     RECT  77.149 1.776 77.177 3.432 ;
     RECT  77.065 18.96 77.209 18.984 ;
     RECT  77.209 18.768 77.245 18.984 ;
     RECT  77.245 18.432 77.461 18.984 ;
     RECT  76.451 9.792 77.497 17.448 ;
     RECT  76.643 6.048 77.564 6.888 ;
     RECT  76.451 8.4 77.564 8.472 ;
     RECT  77.317 31.344 77.66 31.368 ;
     RECT  76.573 22.032 77.677 22.104 ;
     RECT  77.497 9.552 77.749 17.448 ;
     RECT  77.461 18.432 77.749 19.944 ;
     RECT  76.781 69.072 77.797 69.096 ;
     RECT  77.564 6.048 77.821 8.472 ;
     RECT  77.749 9.552 77.821 19.944 ;
     RECT  77.101 24.192 77.821 25.128 ;
     RECT  77.797 68.976 77.845 69.096 ;
     RECT  77.785 70.08 77.845 70.104 ;
     RECT  77.033 27.888 77.893 28.68 ;
     RECT  77.209 29.664 77.893 29.688 ;
     RECT  77.701 35.328 77.893 35.352 ;
     RECT  77.177 2.148 78.008 3.432 ;
     RECT  77.821 6.048 78.008 19.944 ;
     RECT  77.677 22.032 78.008 22.824 ;
     RECT  77.821 24.192 78.008 25.176 ;
     RECT  77.893 27.888 78.008 29.688 ;
     RECT  77.66 30.96 78.008 31.368 ;
     RECT  77.852 32.448 78.008 32.472 ;
     RECT  77.893 34.8 78.008 35.352 ;
     RECT  76.853 62.256 78.008 67.848 ;
     RECT  77.845 68.976 78.008 70.104 ;
     RECT  78.008 2.148 78.112 70.104 ;
     RECT  78.112 2.418 78.181 70.104 ;
     RECT  77.701 71.088 78.181 71.112 ;
     RECT  78.181 2.418 78.304 71.112 ;
     RECT  78.304 26.832 78.365 28.44 ;
     RECT  78.304 6.048 78.419 7.416 ;
     RECT  78.304 20.736 78.467 23.304 ;
     RECT  78.467 20.736 78.473 22.104 ;
     RECT  78.304 8.448 78.509 17.688 ;
     RECT  78.365 26.832 78.509 28.2 ;
     RECT  78.473 20.736 78.515 22.056 ;
     RECT  78.509 26.832 78.515 27.432 ;
     RECT  78.304 61.872 78.541 71.112 ;
     RECT  78.419 6.096 78.545 7.416 ;
     RECT  78.515 20.832 78.545 22.056 ;
     RECT  78.545 20.832 78.611 21.672 ;
     RECT  78.541 61.872 78.625 71.16 ;
     RECT  78.611 21.648 78.653 21.672 ;
     RECT  78.545 7.392 78.761 7.416 ;
     RECT  78.625 61.872 78.851 71.112 ;
     RECT  78.467 23.28 78.941 23.304 ;
     RECT  78.851 61.872 78.977 69.528 ;
     RECT  78.304 30.24 79.091 31.032 ;
     RECT  78.545 6.096 79.193 6.12 ;
     RECT  78.977 65.52 79.193 69.528 ;
     RECT  78.509 15.456 79.235 17.688 ;
     RECT  79.235 15.456 79.283 15.48 ;
     RECT  79.193 65.52 79.301 69.096 ;
     RECT  79.091 30.24 79.337 30.6 ;
     RECT  78.851 70.656 79.379 71.112 ;
     RECT  79.379 70.656 79.427 71.064 ;
     RECT  79.301 65.52 79.453 66.744 ;
     RECT  78.509 8.448 79.481 14.424 ;
     RECT  78.515 26.832 79.549 26.856 ;
     RECT  78.977 61.872 79.553 64.44 ;
     RECT  79.453 65.616 79.589 66.744 ;
     RECT  78.304 24.816 79.697 24.84 ;
     RECT  79.621 32.448 79.705 32.472 ;
     RECT  79.481 8.832 79.765 14.424 ;
     RECT  79.301 67.872 79.805 69.096 ;
     RECT  79.235 16.848 79.811 17.688 ;
     RECT  79.765 8.832 79.849 14.808 ;
     RECT  79.589 65.616 79.913 66.36 ;
     RECT  79.427 70.992 79.913 71.064 ;
     RECT  79.549 26.832 79.949 27.096 ;
     RECT  79.805 67.872 79.949 69 ;
     RECT  79.949 26.832 79.985 26.904 ;
     RECT  79.849 8.832 80.057 14.136 ;
     RECT  79.949 67.872 80.057 68.376 ;
     RECT  80.012 7.392 80.099 7.416 ;
     RECT  79.985 26.88 80.129 26.904 ;
     RECT  80.057 11.232 80.165 14.136 ;
     RECT  80.165 11.376 80.201 14.136 ;
     RECT  79.913 70.992 80.237 71.016 ;
     RECT  80.201 11.376 80.273 12.792 ;
     RECT  80.057 67.872 80.341 67.944 ;
     RECT  80.057 8.832 80.387 10.2 ;
     RECT  80.273 11.376 80.417 12.408 ;
     RECT  79.553 61.872 80.417 64.296 ;
     RECT  80.417 62.352 80.557 64.296 ;
     RECT  79.913 66.24 80.557 66.36 ;
     RECT  80.341 67.728 80.557 67.944 ;
     RECT  80.449 29.04 80.561 29.064 ;
     RECT  80.557 66.24 80.633 67.944 ;
     RECT  80.557 62.352 80.741 65.016 ;
     RECT  80.387 8.832 80.957 9 ;
     RECT  80.201 14.112 80.963 14.136 ;
     RECT  80.957 8.976 81.029 9 ;
     RECT  81.133 70.704 81.169 70.728 ;
     RECT  79.337 30.24 81.203 30.264 ;
     RECT  81.169 70.08 81.205 70.728 ;
     RECT  80.387 10.176 81.301 10.2 ;
     RECT  80.417 11.856 81.347 12.408 ;
     RECT  81.025 22.8 81.425 22.824 ;
     RECT  81.205 70.08 81.452 70.824 ;
     RECT  80.633 66.288 81.521 67.944 ;
     RECT  81.347 12 81.533 12.408 ;
     RECT  81.452 70.08 81.589 70.872 ;
     RECT  81.301 10.176 81.644 10.776 ;
     RECT  81.521 66.288 81.685 68.376 ;
     RECT  80.741 62.352 81.745 64.584 ;
     RECT  81.025 7.968 81.821 7.992 ;
     RECT  81.533 12 81.827 12.024 ;
     RECT  81.241 25.344 81.857 25.368 ;
     RECT  81.745 62.352 81.893 65.208 ;
     RECT  81.893 62.352 81.923 65.016 ;
     RECT  81.685 66.288 81.925 68.424 ;
     RECT  81.673 23.904 82.037 23.928 ;
     RECT  81.923 62.496 82.037 65.016 ;
     RECT  82.037 63.168 82.067 65.016 ;
     RECT  81.589 70.08 82.181 71.112 ;
     RECT  81.644 10.032 82.213 10.776 ;
     RECT  81.925 66.288 82.213 69.096 ;
     RECT  82.213 66.24 82.249 69.096 ;
     RECT  82.213 9.648 82.253 10.776 ;
     RECT  82.249 66.144 82.261 69.096 ;
     RECT  82.181 70.08 82.261 70.776 ;
     RECT  82.261 66.144 82.361 70.776 ;
     RECT  82.361 66.144 82.757 69.528 ;
     RECT  79.811 17.424 82.837 17.688 ;
     RECT  82.933 23.136 83.041 23.16 ;
     RECT  82.757 66.144 83.225 69.432 ;
     RECT  83.041 22.512 83.293 23.16 ;
     RECT  83.293 22.512 83.329 23.4 ;
     RECT  82.361 70.704 83.333 70.776 ;
     RECT  82.253 9.648 83.408 10.584 ;
     RECT  82.837 17.424 83.408 18.168 ;
     RECT  83.329 22.512 83.408 23.688 ;
     RECT  82.825 26.208 83.408 26.232 ;
     RECT  82.067 63.168 83.408 64.584 ;
     RECT  83.225 66.144 83.408 69.24 ;
     RECT  83.408 2.148 83.512 69.24 ;
     RECT  83.512 2.418 83.704 69.24 ;
     RECT  83.704 21.984 83.729 23.16 ;
     RECT  83.704 24.624 83.729 24.648 ;
     RECT  83.333 70.704 83.765 70.728 ;
     RECT  83.704 69.024 83.801 69.24 ;
     RECT  83.801 69.216 83.945 69.24 ;
     RECT  83.729 22.512 84.017 23.16 ;
     RECT  84.017 22.512 84.233 22.536 ;
     RECT  88.808 2.148 88.912 69.132 ;
     RECT  88.912 2.418 89.104 68.862 ;
     RECT  94.208 2.148 94.312 69.132 ;
     RECT  94.312 2.418 94.504 68.862 ;
     RECT  99.608 2.148 99.712 69.132 ;
     RECT  99.712 2.418 99.904 68.862 ;
     RECT  105.008 2.148 105.112 69.132 ;
     RECT  105.112 2.418 105.304 68.862 ;
     RECT  110.408 2.148 110.512 69.132 ;
     RECT  110.512 2.418 110.704 68.862 ;
     RECT  115.808 2.148 115.912 69.132 ;
     RECT  115.912 2.418 116.104 68.862 ;
     RECT  121.208 2.148 121.312 69.132 ;
     RECT  121.312 2.418 121.504 68.862 ;
     RECT  126.608 2.148 126.712 69.132 ;
     RECT  126.712 2.418 126.904 68.862 ;
    LAYER M5 ;
     RECT  61.392 0.016 67.512 0.133 ;
     RECT  42.192 0.016 44.328 0.179 ;
     RECT  61.392 0.133 67.608 0.229 ;
     RECT  42.24 0.179 44.328 0.275 ;
     RECT  74.064 0.016 77.112 0.563 ;
     RECT  74.112 0.563 77.112 0.659 ;
     RECT  40.656 0.016 40.728 1.763 ;
     RECT  50.256 0.016 53.304 1.763 ;
     RECT  46.704 0.016 49.176 1.811 ;
     RECT  50.304 1.763 53.304 1.859 ;
     RECT  56.4 0.016 56.856 1.859 ;
     RECT  56.4 1.859 56.76 1.907 ;
     RECT  52.944 1.859 53.304 2.003 ;
     RECT  40.656 1.763 40.68 2.137 ;
     RECT  74.208 0.659 77.112 2.137 ;
     RECT  2.4 2.137 2.52 2.151 ;
     RECT  7.8 2.137 7.92 2.151 ;
     RECT  13.2 2.137 13.32 2.151 ;
     RECT  18.6 2.137 18.72 2.151 ;
     RECT  24 2.137 24.12 2.151 ;
     RECT  29.4 2.137 29.52 2.151 ;
     RECT  34.8 2.137 34.92 2.151 ;
     RECT  45.36 0.016 45.72 2.151 ;
     RECT  46.704 1.811 49.128 2.151 ;
     RECT  72.6 2.137 72.72 2.151 ;
     RECT  74.208 2.137 78.12 2.151 ;
     RECT  83.4 2.137 83.52 2.151 ;
     RECT  88.8 2.137 88.92 2.151 ;
     RECT  94.2 2.137 94.32 2.151 ;
     RECT  99.6 2.137 99.72 2.151 ;
     RECT  105 2.137 105.12 2.151 ;
     RECT  110.4 2.137 110.52 2.151 ;
     RECT  115.8 2.137 115.92 2.151 ;
     RECT  121.2 2.137 121.32 2.151 ;
     RECT  126.6 2.137 126.72 2.151 ;
     RECT  61.392 0.229 67.704 2.245 ;
     RECT  45.36 2.151 49.128 2.291 ;
     RECT  45.504 2.291 49.128 2.821 ;
     RECT  50.304 1.859 51.96 2.821 ;
     RECT  74.208 2.151 78.312 2.963 ;
     RECT  42.288 0.275 44.328 3.443 ;
     RECT  42.576 3.443 44.328 3.491 ;
     RECT  45.504 2.821 51.96 3.491 ;
     RECT  42.72 3.491 44.328 3.539 ;
     RECT  45.504 3.491 45.912 4.019 ;
     RECT  47.04 3.491 51.96 4.019 ;
     RECT  52.944 2.003 52.968 4.019 ;
     RECT  60.912 2.245 67.704 4.019 ;
     RECT  74.352 2.963 78.312 4.019 ;
     RECT  47.568 4.019 48.264 4.115 ;
     RECT  49.968 4.019 51.864 4.115 ;
     RECT  42.912 3.539 44.328 4.595 ;
     RECT  47.568 4.115 47.832 4.595 ;
     RECT  60.912 4.019 67.656 4.595 ;
     RECT  47.664 4.595 47.832 4.643 ;
     RECT  42.912 4.595 43.752 4.739 ;
     RECT  43.296 4.739 43.752 4.787 ;
     RECT  43.44 4.787 43.752 5.171 ;
     RECT  43.488 5.171 43.752 5.267 ;
     RECT  47.808 4.643 47.832 5.315 ;
     RECT  49.968 4.115 51.432 5.461 ;
     RECT  59.856 5.605 59.88 5.701 ;
     RECT  60.912 4.595 67.608 5.701 ;
     RECT  74.592 4.019 78.312 6.037 ;
     RECT  59.856 5.701 67.608 6.133 ;
     RECT  48.96 5.605 48.984 6.181 ;
     RECT  49.968 5.461 52.152 6.181 ;
     RECT  48.96 6.181 52.152 6.229 ;
     RECT  53.424 5.653 53.448 6.229 ;
     RECT  58.944 6.133 67.608 6.229 ;
     RECT  71.28 5.941 71.304 6.229 ;
     RECT  72.6 2.151 72.912 6.229 ;
     RECT  45.6 4.019 45.912 6.421 ;
     RECT  71.28 6.229 72.912 6.421 ;
     RECT  70.464 6.421 72.912 6.661 ;
     RECT  45.6 6.421 46.2 6.709 ;
     RECT  74.592 6.037 78.408 6.709 ;
     RECT  44.832 6.709 46.2 6.805 ;
     RECT  48.96 6.229 53.448 6.805 ;
     RECT  56.4 1.907 56.712 6.805 ;
     RECT  69.552 6.661 73.032 6.805 ;
     RECT  42.72 6.805 42.744 6.853 ;
     RECT  42.72 6.853 43.224 7.189 ;
     RECT  44.784 6.805 46.2 7.237 ;
     RECT  55.776 6.805 56.712 7.333 ;
     RECT  44.784 7.237 46.488 7.381 ;
     RECT  48.192 6.805 54.024 7.381 ;
     RECT  74.448 6.709 78.408 7.381 ;
     RECT  55.536 7.333 56.712 7.765 ;
     RECT  57.84 7.189 57.864 7.765 ;
     RECT  44.784 7.381 54.024 7.909 ;
     RECT  44.784 7.909 54.168 7.957 ;
     RECT  58.944 6.229 68.424 7.957 ;
     RECT  69.552 6.805 73.416 7.957 ;
     RECT  44.784 7.957 54.504 8.101 ;
     RECT  55.536 7.765 57.864 8.101 ;
     RECT  44.784 8.101 57.864 8.293 ;
     RECT  58.944 7.957 73.416 8.293 ;
     RECT  74.448 7.381 78.744 8.485 ;
     RECT  80.064 7.381 80.088 8.485 ;
     RECT  74.448 8.485 80.088 8.821 ;
     RECT  74.448 8.821 80.376 8.867 ;
     RECT  42.72 7.189 43.416 9.061 ;
     RECT  44.784 8.293 73.416 9.061 ;
     RECT  74.448 8.867 79.272 9.061 ;
     RECT  80.352 8.867 80.376 9.251 ;
     RECT  42.72 9.061 79.272 9.347 ;
     RECT  40.2 2.137 40.68 9.637 ;
     RECT  83.4 2.151 83.712 9.637 ;
     RECT  59.808 9.347 79.272 9.923 ;
     RECT  81.696 10.021 81.72 10.165 ;
     RECT  42.72 9.347 58.488 10.307 ;
     RECT  81.024 10.165 81.72 10.549 ;
     RECT  59.808 9.923 71.256 10.597 ;
     RECT  59.472 10.597 71.256 10.835 ;
     RECT  44.544 10.307 58.488 10.837 ;
     RECT  59.472 10.835 68.712 10.837 ;
     RECT  40.2 9.637 41.208 10.883 ;
     RECT  44.544 10.837 68.712 10.883 ;
     RECT  42.72 10.307 43.416 11.365 ;
     RECT  44.544 10.883 57.864 11.365 ;
     RECT  72.336 9.923 79.272 11.459 ;
     RECT  58.992 10.883 68.712 11.507 ;
     RECT  42.72 11.365 57.864 11.651 ;
     RECT  81.024 10.549 81.816 11.845 ;
     RECT  42.72 11.651 42.84 11.939 ;
     RECT  60.768 11.507 68.712 11.941 ;
     RECT  69.84 10.835 71.256 11.941 ;
     RECT  80.928 11.845 81.816 12.035 ;
     RECT  42.72 11.939 42.744 12.469 ;
     RECT  58.992 11.507 59.496 12.517 ;
     RECT  60.768 11.941 71.256 12.517 ;
     RECT  44.208 11.651 57.864 12.755 ;
     RECT  72.336 11.459 79.224 12.901 ;
     RECT  44.208 12.755 57.48 13.045 ;
     RECT  43.92 13.045 57.48 13.187 ;
     RECT  43.92 13.187 57.192 13.283 ;
     RECT  42.336 12.469 42.744 13.427 ;
     RECT  58.992 12.517 71.256 13.621 ;
     RECT  43.92 13.283 48.216 13.763 ;
     RECT  43.92 13.763 48.12 13.811 ;
     RECT  43.92 13.811 46.68 14.099 ;
     RECT  80.928 12.035 81.192 14.147 ;
     RECT  58.752 13.621 71.256 14.197 ;
     RECT  72.336 12.901 79.8 14.197 ;
     RECT  49.488 13.283 57.192 14.387 ;
     RECT  58.752 14.197 79.8 14.867 ;
     RECT  49.584 14.387 57.192 14.869 ;
     RECT  58.752 14.867 69.672 14.869 ;
     RECT  49.584 14.869 69.672 14.915 ;
     RECT  70.992 14.867 79.8 14.915 ;
     RECT  56.4 14.915 69.672 14.963 ;
     RECT  56.4 14.963 65.352 15.011 ;
     RECT  58.752 15.011 65.352 15.155 ;
     RECT  42.432 13.427 42.744 15.203 ;
     RECT  58.752 15.155 59.832 15.299 ;
     RECT  49.584 14.915 54.264 15.443 ;
     RECT  44.208 14.099 46.68 15.539 ;
     RECT  49.632 15.443 54.264 15.635 ;
     RECT  42.432 15.203 42.648 15.731 ;
     RECT  59.232 15.299 59.832 15.875 ;
     RECT  66.336 14.963 69.672 15.973 ;
     RECT  70.992 14.915 71.016 15.973 ;
     RECT  42.528 15.731 42.648 16.019 ;
     RECT  60.816 15.155 65.352 16.117 ;
     RECT  66.336 15.973 71.016 16.117 ;
     RECT  55.344 16.021 55.368 16.163 ;
     RECT  44.208 15.539 46.488 16.259 ;
     RECT  56.4 15.011 57.192 16.259 ;
     RECT  42.528 16.019 42.552 16.307 ;
     RECT  60.816 16.117 71.016 16.357 ;
     RECT  72.048 14.915 79.8 16.357 ;
     RECT  60.816 16.357 79.8 16.451 ;
     RECT  61.056 16.451 79.8 16.499 ;
     RECT  49.632 15.635 51.528 16.595 ;
     RECT  52.512 15.635 54.264 16.595 ;
     RECT  61.056 16.499 71.016 16.787 ;
     RECT  53.088 16.595 53.976 16.835 ;
     RECT  72.048 16.499 79.8 16.883 ;
     RECT  53.088 16.835 53.688 17.123 ;
     RECT  61.056 16.787 68.952 17.123 ;
     RECT  61.056 17.123 68.376 17.699 ;
     RECT  72.048 16.883 79.224 17.699 ;
     RECT  51 16.595 51.528 17.843 ;
     RECT  59.808 15.875 59.832 18.131 ;
     RECT  82.896 9.637 83.712 18.133 ;
     RECT  63.504 17.699 68.376 18.851 ;
     RECT  70.128 16.787 71.016 19.141 ;
     RECT  69.504 19.141 71.016 19.283 ;
     RECT  70.992 19.283 71.016 19.573 ;
     RECT  72.048 17.699 78.792 19.573 ;
     RECT  66.528 18.851 68.376 19.619 ;
     RECT  70.992 19.573 78.792 19.907 ;
     RECT  63.504 18.851 64.92 19.955 ;
     RECT  72.048 19.907 78.792 20.195 ;
     RECT  44.208 16.259 46.008 20.579 ;
     RECT  66.528 19.619 67.512 20.821 ;
     RECT  40.2 10.883 40.68 20.867 ;
     RECT  66.528 20.821 67.752 21.011 ;
     RECT  45.072 20.579 45.912 21.155 ;
     RECT  69.504 19.283 69.528 21.155 ;
     RECT  61.056 17.699 62.472 22.883 ;
     RECT  61.056 22.883 62.112 23.411 ;
     RECT  63.504 19.955 64.68 23.411 ;
     RECT  72.48 20.195 78.792 23.509 ;
     RECT  72.096 23.509 78.792 23.987 ;
     RECT  64.416 23.411 64.68 24.371 ;
     RECT  64.464 24.371 64.68 24.899 ;
     RECT  61.632 23.411 62.112 25.859 ;
     RECT  82.848 18.133 83.712 26.243 ;
     RECT  70.992 19.907 71.016 27.395 ;
     RECT  72.48 23.987 78.792 28.547 ;
     RECT  72.48 28.547 74.28 28.933 ;
     RECT  75.6 28.547 78.792 29.605 ;
     RECT  75.552 29.605 78.792 29.699 ;
     RECT  81.168 14.147 81.192 30.275 ;
     RECT  72.144 28.933 74.28 30.373 ;
     RECT  75.552 29.699 76.344 30.853 ;
     RECT  77.472 29.699 78.792 30.997 ;
     RECT  64.464 24.899 64.488 31.379 ;
     RECT  77.472 30.997 79.08 31.379 ;
     RECT  72 30.373 74.28 31.955 ;
     RECT  77.712 31.379 79.08 32.437 ;
     RECT  66.528 21.011 67.512 34.357 ;
     RECT  72.6 31.955 74.28 34.643 ;
     RECT  77.712 32.437 79.656 35.363 ;
     RECT  72.6 34.643 73.656 35.605 ;
     RECT  75.312 30.853 76.344 42.179 ;
     RECT  66.528 34.357 68.376 49.619 ;
     RECT  72.6 35.605 74.328 60.373 ;
     RECT  61.68 25.859 62.112 61.139 ;
     RECT  72 60.373 74.328 61.571 ;
     RECT  72.384 61.571 74.328 61.619 ;
     RECT  48.96 61.525 48.984 62.149 ;
     RECT  48.96 62.149 49.368 62.293 ;
     RECT  75.312 42.179 75.864 62.437 ;
     RECT  72.384 61.619 73.032 62.581 ;
     RECT  74.304 61.619 74.328 62.581 ;
     RECT  63.168 61.429 63.192 62.677 ;
     RECT  72.384 62.581 74.328 62.677 ;
     RECT  75.312 62.437 76.392 62.677 ;
     RECT  48.816 62.293 49.368 62.723 ;
     RECT  48.816 62.723 49.128 62.725 ;
     RECT  61.8 61.139 62.112 63.013 ;
     RECT  63.168 62.677 63.24 63.061 ;
     RECT  81.888 62.341 81.912 63.157 ;
     RECT  83.4 26.243 83.712 63.157 ;
     RECT  61.536 63.013 62.112 63.205 ;
     RECT  63.168 63.061 63.432 63.205 ;
     RECT  61.536 63.205 63.432 63.251 ;
     RECT  81.888 63.157 83.712 63.299 ;
     RECT  51 17.843 51.312 63.589 ;
     RECT  56.4 16.259 56.712 63.589 ;
     RECT  64.944 61.957 64.968 63.731 ;
     RECT  56.304 63.589 56.712 63.779 ;
     RECT  72.384 62.677 76.392 63.781 ;
     RECT  54.72 63.541 54.744 63.827 ;
     RECT  61.536 63.251 63.24 63.875 ;
     RECT  61.8 63.875 63.24 64.019 ;
     RECT  78 35.363 79.656 64.117 ;
     RECT  80.688 63.061 80.712 64.117 ;
     RECT  78 64.117 80.712 64.261 ;
     RECT  82.032 63.299 83.712 64.261 ;
     RECT  67.2 49.619 68.376 64.355 ;
     RECT  48.528 62.725 49.128 64.451 ;
     RECT  72.384 63.781 77.016 64.499 ;
     RECT  65.376 64.213 65.4 64.931 ;
     RECT  50.688 63.589 51.312 65.027 ;
     RECT  78 64.261 83.712 65.027 ;
     RECT  63.264 64.357 63.288 65.411 ;
     RECT  61.8 64.019 62.112 66.085 ;
     RECT  48.528 64.451 48.552 66.373 ;
     RECT  72.6 64.499 77.016 66.755 ;
     RECT  61.8 66.085 63.096 66.757 ;
     RECT  78 65.027 81.528 66.901 ;
     RECT  82.512 65.027 83.712 66.901 ;
     RECT  78 66.901 83.712 67.141 ;
     RECT  77.712 67.141 83.712 67.283 ;
     RECT  77.712 67.283 81.144 67.859 ;
     RECT  72.6 66.755 76.632 67.907 ;
     RECT  77.712 67.859 80.088 67.955 ;
     RECT  48.336 66.373 48.552 68.197 ;
     RECT  82.32 67.283 82.344 68.341 ;
     RECT  83.4 67.283 83.712 68.341 ;
     RECT  47.712 68.197 48.552 68.725 ;
     RECT  47.568 68.725 48.552 68.917 ;
     RECT  47.472 68.917 48.552 68.965 ;
     RECT  2.4 2.151 2.712 69.129 ;
     RECT  7.8 2.151 8.112 69.129 ;
     RECT  13.2 2.151 13.512 69.129 ;
     RECT  18.6 2.151 18.912 69.129 ;
     RECT  24 2.151 24.312 69.129 ;
     RECT  29.4 2.151 29.712 69.129 ;
     RECT  34.8 2.151 35.112 69.129 ;
     RECT  40.2 20.867 40.512 69.129 ;
     RECT  45.6 21.155 45.912 69.129 ;
     RECT  51 65.027 51.312 69.129 ;
     RECT  56.4 63.779 56.712 69.129 ;
     RECT  67.2 64.355 67.512 69.129 ;
     RECT  81.552 68.341 83.712 69.129 ;
     RECT  88.8 2.151 89.112 69.129 ;
     RECT  94.2 2.151 94.512 69.129 ;
     RECT  99.6 2.151 99.912 69.129 ;
     RECT  105 2.151 105.312 69.129 ;
     RECT  110.4 2.151 110.712 69.129 ;
     RECT  115.8 2.151 116.112 69.129 ;
     RECT  121.2 2.151 121.512 69.129 ;
     RECT  126.6 2.151 126.912 69.129 ;
     RECT  2.4 69.129 2.52 69.143 ;
     RECT  7.8 69.129 7.92 69.143 ;
     RECT  13.2 69.129 13.32 69.143 ;
     RECT  18.6 69.129 18.72 69.143 ;
     RECT  24 69.129 24.12 69.143 ;
     RECT  29.4 69.129 29.52 69.143 ;
     RECT  34.8 69.129 34.92 69.143 ;
     RECT  40.2 69.129 40.32 69.143 ;
     RECT  45.6 69.129 45.72 69.143 ;
     RECT  51 69.129 51.12 69.143 ;
     RECT  56.4 69.129 56.52 69.143 ;
     RECT  61.8 66.757 63.576 69.143 ;
     RECT  67.2 69.129 67.32 69.143 ;
     RECT  72.6 67.907 76.2 69.143 ;
     RECT  81.552 69.129 83.52 69.143 ;
     RECT  88.8 69.129 88.92 69.143 ;
     RECT  94.2 69.129 94.32 69.143 ;
     RECT  99.6 69.129 99.72 69.143 ;
     RECT  105 69.129 105.12 69.143 ;
     RECT  110.4 69.129 110.52 69.143 ;
     RECT  115.8 69.129 115.92 69.143 ;
     RECT  121.2 69.129 121.32 69.143 ;
     RECT  126.6 69.129 126.72 69.143 ;
     RECT  47.472 68.965 48.936 69.157 ;
     RECT  73.2 69.143 76.2 69.205 ;
     RECT  47.472 69.157 48.984 69.493 ;
     RECT  81.552 69.143 82.776 70.069 ;
     RECT  77.712 67.955 79.416 70.691 ;
     RECT  77.712 70.691 79.368 71.123 ;
     RECT  47.424 69.493 48.984 71.248 ;
     RECT  62.064 69.143 63.576 71.248 ;
     RECT  73.2 69.205 76.248 71.248 ;
     RECT  77.808 71.123 79.32 71.248 ;
     RECT  81.264 70.069 82.776 71.248 ;
     RECT  44.376 0.016 45.216 0.132 ;
     RECT  40.728 0.132 42.192 0.179 ;
     RECT  44.328 0.132 45.36 2.291 ;
     RECT  45.72 0.132 46.704 2.151 ;
     RECT  49.176 0.132 50.256 1.763 ;
     RECT  40.728 0.179 42.24 0.275 ;
     RECT  74.112 0.659 74.208 2.137 ;
     RECT  49.176 1.763 50.304 1.811 ;
     RECT  49.128 1.811 50.304 2.821 ;
     RECT  51.96 1.859 52.944 4.019 ;
     RECT  72.72 2.137 74.208 2.151 ;
     RECT  72.912 2.151 74.208 2.963 ;
     RECT  44.328 2.291 45.504 4.019 ;
     RECT  72.912 2.963 74.352 4.019 ;
     RECT  45.912 3.491 47.04 4.019 ;
     RECT  44.328 4.019 45.6 4.595 ;
     RECT  51.864 4.019 52.152 4.115 ;
     RECT  51.432 4.115 52.152 5.461 ;
     RECT  48.984 5.605 49.968 6.181 ;
     RECT  59.88 5.605 60.912 5.701 ;
     RECT  52.152 5.653 53.424 6.229 ;
     RECT  71.304 5.941 72.6 6.229 ;
     RECT  68.424 6.661 69.552 7.957 ;
     RECT  73.032 6.709 74.448 6.805 ;
     RECT  73.416 6.805 74.448 9.061 ;
     RECT  43.416 7.189 44.784 9.061 ;
     RECT  56.712 7.189 57.84 7.765 ;
     RECT  57.864 7.189 58.944 8.293 ;
     RECT  54.024 7.333 55.536 7.909 ;
     RECT  78.744 7.381 80.064 8.485 ;
     RECT  54.168 7.909 55.536 7.957 ;
     RECT  54.504 7.957 55.536 8.101 ;
     RECT  79.272 8.867 80.352 9.251 ;
     RECT  58.488 9.347 59.808 10.597 ;
     RECT  41.208 9.637 42.72 10.883 ;
     RECT  71.256 9.923 72.336 14.197 ;
     RECT  81.72 10.021 82.896 10.549 ;
     RECT  43.416 10.307 44.544 11.365 ;
     RECT  81.816 10.549 82.896 12.035 ;
     RECT  58.488 10.597 59.472 10.837 ;
     RECT  68.712 10.835 69.84 11.941 ;
     RECT  57.864 10.883 58.992 12.755 ;
     RECT  79.224 11.459 79.272 12.901 ;
     RECT  59.496 11.507 60.768 12.517 ;
     RECT  42.84 11.651 44.208 11.939 ;
     RECT  42.744 11.939 44.208 13.045 ;
     RECT  57.48 12.755 58.992 13.187 ;
     RECT  79.8 12.901 80.928 14.147 ;
     RECT  42.744 13.045 43.92 14.099 ;
     RECT  58.752 13.187 58.992 13.621 ;
     RECT  48.216 13.283 49.488 13.763 ;
     RECT  48.12 13.763 49.488 13.811 ;
     RECT  42.744 14.099 44.208 15.203 ;
     RECT  79.8 14.147 81.168 16.883 ;
     RECT  69.672 14.867 70.992 15.973 ;
     RECT  54.264 14.915 56.4 16.021 ;
     RECT  71.016 14.915 72.048 16.357 ;
     RECT  65.352 14.963 66.336 16.117 ;
     RECT  59.832 15.155 60.816 16.451 ;
     RECT  51.528 15.635 52.512 16.595 ;
     RECT  54.264 16.021 55.344 16.163 ;
     RECT  55.368 16.021 56.4 16.163 ;
     RECT  59.832 16.451 61.056 18.131 ;
     RECT  71.016 16.499 72.048 19.573 ;
     RECT  68.952 16.787 70.128 17.123 ;
     RECT  62.472 17.699 63.504 22.883 ;
     RECT  68.376 19.141 69.504 19.619 ;
     RECT  69.528 19.283 70.992 21.155 ;
     RECT  67.512 19.619 67.752 20.821 ;
     RECT  71.016 19.907 72.048 20.195 ;
     RECT  71.016 20.195 72.48 23.509 ;
     RECT  62.112 22.883 63.504 23.411 ;
     RECT  71.016 23.509 72.096 23.987 ;
     RECT  71.016 23.987 72.48 27.395 ;
     RECT  74.28 28.547 75.6 29.605 ;
     RECT  74.28 29.605 75.552 30.853 ;
     RECT  76.344 29.699 77.472 31.379 ;
     RECT  74.28 30.853 75.312 34.643 ;
     RECT  76.344 31.379 77.712 35.363 ;
     RECT  73.656 34.643 75.312 35.605 ;
     RECT  74.328 35.605 75.312 62.677 ;
     RECT  62.112 61.429 63.168 63.205 ;
     RECT  73.032 61.619 74.304 62.581 ;
     RECT  81.912 62.341 83.4 63.157 ;
     RECT  63.432 63.061 64.944 63.251 ;
     RECT  79.656 63.061 80.688 64.117 ;
     RECT  80.712 63.061 81.888 63.299 ;
     RECT  63.24 63.251 63.288 64.019 ;
     RECT  80.712 63.299 82.032 64.261 ;
     RECT  77.016 63.781 78 66.755 ;
     RECT  62.112 64.019 63.288 64.357 ;
     RECT  62.112 64.357 63.264 65.411 ;
     RECT  81.528 65.027 82.512 66.901 ;
     RECT  62.112 65.411 63.288 66.085 ;
     RECT  63.096 66.085 63.288 66.757 ;
     RECT  76.632 66.755 78 67.141 ;
     RECT  76.632 67.141 77.712 67.907 ;
     RECT  81.144 67.283 82.32 67.859 ;
     RECT  82.344 67.283 83.4 68.341 ;
     RECT  80.088 67.859 82.32 67.955 ;
     RECT  76.2 67.907 77.712 69.205 ;
     RECT  81.552 67.955 82.32 68.341 ;
     RECT  76.248 69.205 77.712 71.123 ;
  END
END ot_hgi_qdq_fr_one_payload
END LIBRARY
